VERSION 5.8 ;
BUSBITCHARS "[]" ;
DIVIDERCHAR "/" ;
UNITS
    DATABASE MICRONS 1000 ;
END UNITS

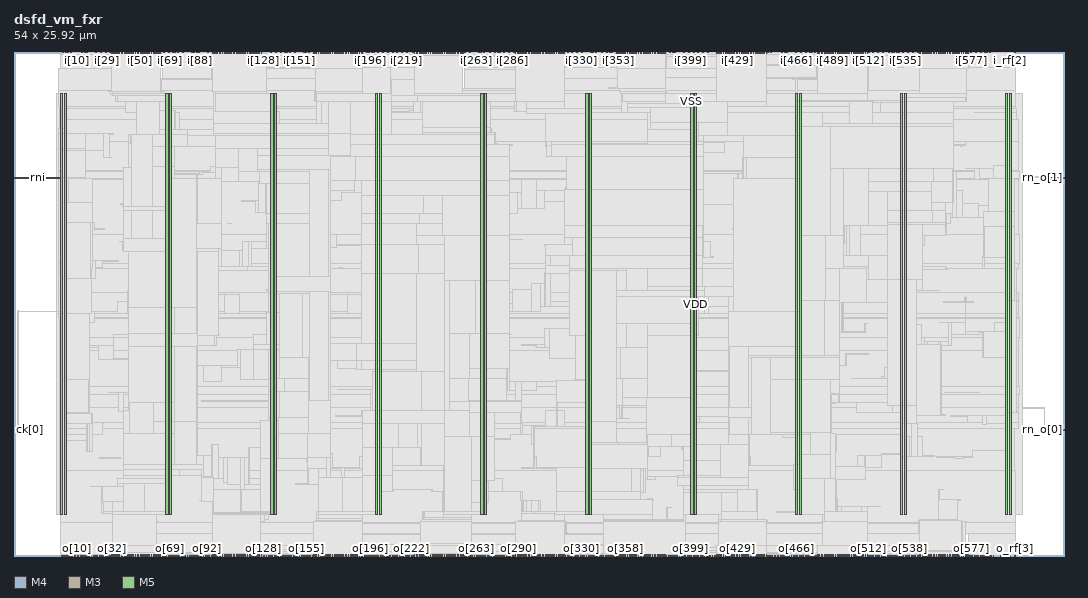
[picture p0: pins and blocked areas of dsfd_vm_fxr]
MACRO dsfd_vm_fxr
  FOREIGN dsfd_vm_fxr 0 0 ;
  CLASS BLOCK ;
  SIZE 54 BY 25.92 ;
  PIN ck[0]
    DIRECTION INPUT ;
    USE SIGNAL ;
    PORT
      LAYER M4 ;
        RECT  0 6.48 0.084 6.504 ;
    END
    PORT
      LAYER M4 ;
        RECT  0.06 6.48 0.227 6.504 ;
    END
  END ck[0]
  PIN i[0]
    DIRECTION INPUT ;
    USE SIGNAL ;
    PORT
      LAYER M3 ;
        RECT  2.448 25.882 2.466 25.92 ;
    END
  END i[0]
  PIN i[100]
    DIRECTION INPUT ;
    USE SIGNAL ;
    PORT
      LAYER M5 ;
        RECT  10.56 25.836 10.584 25.92 ;
    END
  END i[100]
  PIN i[101]
    DIRECTION INPUT ;
    USE SIGNAL ;
    PORT
      LAYER M5 ;
        RECT  10.608 25.836 10.632 25.92 ;
    END
  END i[101]
  PIN i[102]
    DIRECTION INPUT ;
    USE SIGNAL ;
    PORT
      LAYER M5 ;
        RECT  10.704 25.836 10.728 25.92 ;
    END
  END i[102]
  PIN i[103]
    DIRECTION INPUT ;
    USE SIGNAL ;
    PORT
      LAYER M5 ;
        RECT  10.8 25.836 10.824 25.92 ;
    END
  END i[103]
  PIN i[104]
    DIRECTION INPUT ;
    USE SIGNAL ;
    PORT
      LAYER M5 ;
        RECT  10.848 25.836 10.872 25.92 ;
    END
  END i[104]
  PIN i[105]
    DIRECTION INPUT ;
    USE SIGNAL ;
    PORT
      LAYER M5 ;
        RECT  10.944 25.836 10.968 25.92 ;
    END
  END i[105]
  PIN i[106]
    DIRECTION INPUT ;
    USE SIGNAL ;
    PORT
      LAYER M5 ;
        RECT  11.04 25.836 11.064 25.92 ;
    END
  END i[106]
  PIN i[107]
    DIRECTION INPUT ;
    USE SIGNAL ;
    PORT
      LAYER M5 ;
        RECT  11.088 25.836 11.112 25.92 ;
    END
  END i[107]
  PIN i[108]
    DIRECTION INPUT ;
    USE SIGNAL ;
    PORT
      LAYER M5 ;
        RECT  11.184 25.836 11.208 25.92 ;
    END
  END i[108]
  PIN i[109]
    DIRECTION INPUT ;
    USE SIGNAL ;
    PORT
      LAYER M5 ;
        RECT  11.28 25.836 11.304 25.92 ;
    END
  END i[109]
  PIN i[10]
    DIRECTION INPUT ;
    USE SIGNAL ;
    PORT
      LAYER M3 ;
        RECT  3.24 25.882 3.258 25.92 ;
    END
  END i[10]
  PIN i[110]
    DIRECTION INPUT ;
    USE SIGNAL ;
    PORT
      LAYER M5 ;
        RECT  11.328 25.836 11.352 25.92 ;
    END
  END i[110]
  PIN i[111]
    DIRECTION INPUT ;
    USE SIGNAL ;
    PORT
      LAYER M5 ;
        RECT  11.424 25.836 11.448 25.92 ;
    END
  END i[111]
  PIN i[112]
    DIRECTION INPUT ;
    USE SIGNAL ;
    PORT
      LAYER M5 ;
        RECT  11.52 25.836 11.544 25.92 ;
    END
  END i[112]
  PIN i[113]
    DIRECTION INPUT ;
    USE SIGNAL ;
    PORT
      LAYER M5 ;
        RECT  11.568 25.836 11.592 25.92 ;
    END
  END i[113]
  PIN i[114]
    DIRECTION INPUT ;
    USE SIGNAL ;
    PORT
      LAYER M5 ;
        RECT  11.664 25.836 11.688 25.92 ;
    END
  END i[114]
  PIN i[115]
    DIRECTION INPUT ;
    USE SIGNAL ;
    PORT
      LAYER M5 ;
        RECT  11.76 25.836 11.784 25.92 ;
    END
  END i[115]
  PIN i[116]
    DIRECTION INPUT ;
    USE SIGNAL ;
    PORT
      LAYER M5 ;
        RECT  11.856 25.836 11.88 25.92 ;
    END
  END i[116]
  PIN i[117]
    DIRECTION INPUT ;
    USE SIGNAL ;
    PORT
      LAYER M5 ;
        RECT  11.904 25.836 11.928 25.92 ;
    END
  END i[117]
  PIN i[118]
    DIRECTION INPUT ;
    USE SIGNAL ;
    PORT
      LAYER M5 ;
        RECT  12 25.836 12.024 25.92 ;
    END
  END i[118]
  PIN i[119]
    DIRECTION INPUT ;
    USE SIGNAL ;
    PORT
      LAYER M5 ;
        RECT  12.096 25.836 12.12 25.92 ;
    END
  END i[119]
  PIN i[11]
    DIRECTION INPUT ;
    USE SIGNAL ;
    PORT
      LAYER M3 ;
        RECT  3.312 25.882 3.33 25.92 ;
    END
  END i[11]
  PIN i[120]
    DIRECTION INPUT ;
    USE SIGNAL ;
    PORT
      LAYER M5 ;
        RECT  12.144 25.836 12.168 25.92 ;
    END
  END i[120]
  PIN i[121]
    DIRECTION INPUT ;
    USE SIGNAL ;
    PORT
      LAYER M5 ;
        RECT  12.24 25.836 12.264 25.92 ;
    END
  END i[121]
  PIN i[122]
    DIRECTION INPUT ;
    USE SIGNAL ;
    PORT
      LAYER M5 ;
        RECT  12.336 25.836 12.36 25.92 ;
    END
  END i[122]
  PIN i[123]
    DIRECTION INPUT ;
    USE SIGNAL ;
    PORT
      LAYER M5 ;
        RECT  12.384 25.836 12.408 25.92 ;
    END
  END i[123]
  PIN i[124]
    DIRECTION INPUT ;
    USE SIGNAL ;
    PORT
      LAYER M5 ;
        RECT  12.48 25.836 12.504 25.92 ;
    END
  END i[124]
  PIN i[125]
    DIRECTION INPUT ;
    USE SIGNAL ;
    PORT
      LAYER M5 ;
        RECT  12.576 25.836 12.6 25.92 ;
    END
  END i[125]
  PIN i[126]
    DIRECTION INPUT ;
    USE SIGNAL ;
    PORT
      LAYER M5 ;
        RECT  12.624 25.836 12.648 25.92 ;
    END
  END i[126]
  PIN i[127]
    DIRECTION INPUT ;
    USE SIGNAL ;
    PORT
      LAYER M5 ;
        RECT  12.72 25.836 12.744 25.92 ;
    END
  END i[127]
  PIN i[128]
    DIRECTION INPUT ;
    USE SIGNAL ;
    PORT
      LAYER M3 ;
        RECT  12.816 25.882 12.834 25.92 ;
    END
  END i[128]
  PIN i[129]
    DIRECTION INPUT ;
    USE SIGNAL ;
    PORT
      LAYER M3 ;
        RECT  12.888 25.882 12.906 25.92 ;
    END
  END i[129]
  PIN i[12]
    DIRECTION INPUT ;
    USE SIGNAL ;
    PORT
      LAYER M3 ;
        RECT  3.42 25.882 3.438 25.92 ;
    END
  END i[12]
  PIN i[130]
    DIRECTION INPUT ;
    USE SIGNAL ;
    PORT
      LAYER M3 ;
        RECT  12.96 25.882 12.978 25.92 ;
    END
  END i[130]
  PIN i[131]
    DIRECTION INPUT ;
    USE SIGNAL ;
    PORT
      LAYER M3 ;
        RECT  13.068 25.882 13.086 25.92 ;
    END
  END i[131]
  PIN i[132]
    DIRECTION INPUT ;
    USE SIGNAL ;
    PORT
      LAYER M3 ;
        RECT  13.14 25.882 13.158 25.92 ;
    END
  END i[132]
  PIN i[133]
    DIRECTION INPUT ;
    USE SIGNAL ;
    PORT
      LAYER M3 ;
        RECT  13.212 25.882 13.23 25.92 ;
    END
  END i[133]
  PIN i[134]
    DIRECTION INPUT ;
    USE SIGNAL ;
    PORT
      LAYER M3 ;
        RECT  13.284 25.882 13.302 25.92 ;
    END
  END i[134]
  PIN i[135]
    DIRECTION INPUT ;
    USE SIGNAL ;
    PORT
      LAYER M3 ;
        RECT  13.392 25.882 13.41 25.92 ;
    END
  END i[135]
  PIN i[136]
    DIRECTION INPUT ;
    USE SIGNAL ;
    PORT
      LAYER M3 ;
        RECT  13.464 25.882 13.482 25.92 ;
    END
  END i[136]
  PIN i[137]
    DIRECTION INPUT ;
    USE SIGNAL ;
    PORT
      LAYER M3 ;
        RECT  13.536 25.882 13.554 25.92 ;
    END
  END i[137]
  PIN i[138]
    DIRECTION INPUT ;
    USE SIGNAL ;
    PORT
      LAYER M3 ;
        RECT  13.608 25.882 13.626 25.92 ;
    END
  END i[138]
  PIN i[139]
    DIRECTION INPUT ;
    USE SIGNAL ;
    PORT
      LAYER M3 ;
        RECT  13.716 25.882 13.734 25.92 ;
    END
  END i[139]
  PIN i[13]
    DIRECTION INPUT ;
    USE SIGNAL ;
    PORT
      LAYER M3 ;
        RECT  3.492 25.882 3.51 25.92 ;
    END
  END i[13]
  PIN i[140]
    DIRECTION INPUT ;
    USE SIGNAL ;
    PORT
      LAYER M3 ;
        RECT  13.788 25.882 13.806 25.92 ;
    END
  END i[140]
  PIN i[141]
    DIRECTION INPUT ;
    USE SIGNAL ;
    PORT
      LAYER M3 ;
        RECT  13.86 25.882 13.878 25.92 ;
    END
  END i[141]
  PIN i[142]
    DIRECTION INPUT ;
    USE SIGNAL ;
    PORT
      LAYER M3 ;
        RECT  13.932 25.882 13.95 25.92 ;
    END
  END i[142]
  PIN i[143]
    DIRECTION INPUT ;
    USE SIGNAL ;
    PORT
      LAYER M3 ;
        RECT  14.04 25.882 14.058 25.92 ;
    END
  END i[143]
  PIN i[144]
    DIRECTION INPUT ;
    USE SIGNAL ;
    PORT
      LAYER M3 ;
        RECT  14.112 25.882 14.13 25.92 ;
    END
  END i[144]
  PIN i[145]
    DIRECTION INPUT ;
    USE SIGNAL ;
    PORT
      LAYER M3 ;
        RECT  14.184 25.882 14.202 25.92 ;
    END
  END i[145]
  PIN i[146]
    DIRECTION INPUT ;
    USE SIGNAL ;
    PORT
      LAYER M3 ;
        RECT  14.256 25.882 14.274 25.92 ;
    END
  END i[146]
  PIN i[147]
    DIRECTION INPUT ;
    USE SIGNAL ;
    PORT
      LAYER M3 ;
        RECT  14.364 25.882 14.382 25.92 ;
    END
  END i[147]
  PIN i[148]
    DIRECTION INPUT ;
    USE SIGNAL ;
    PORT
      LAYER M3 ;
        RECT  14.436 25.882 14.454 25.92 ;
    END
  END i[148]
  PIN i[149]
    DIRECTION INPUT ;
    USE SIGNAL ;
    PORT
      LAYER M3 ;
        RECT  14.508 25.882 14.526 25.92 ;
    END
  END i[149]
  PIN i[14]
    DIRECTION INPUT ;
    USE SIGNAL ;
    PORT
      LAYER M3 ;
        RECT  3.564 25.882 3.582 25.92 ;
    END
  END i[14]
  PIN i[150]
    DIRECTION INPUT ;
    USE SIGNAL ;
    PORT
      LAYER M3 ;
        RECT  14.58 25.882 14.598 25.92 ;
    END
  END i[150]
  PIN i[151]
    DIRECTION INPUT ;
    USE SIGNAL ;
    PORT
      LAYER M3 ;
        RECT  14.688 25.882 14.706 25.92 ;
    END
  END i[151]
  PIN i[152]
    DIRECTION INPUT ;
    USE SIGNAL ;
    PORT
      LAYER M3 ;
        RECT  14.76 25.882 14.778 25.92 ;
    END
  END i[152]
  PIN i[153]
    DIRECTION INPUT ;
    USE SIGNAL ;
    PORT
      LAYER M3 ;
        RECT  14.832 25.882 14.85 25.92 ;
    END
  END i[153]
  PIN i[154]
    DIRECTION INPUT ;
    USE SIGNAL ;
    PORT
      LAYER M3 ;
        RECT  14.904 25.882 14.922 25.92 ;
    END
  END i[154]
  PIN i[155]
    DIRECTION INPUT ;
    USE SIGNAL ;
    PORT
      LAYER M3 ;
        RECT  15.012 25.882 15.03 25.92 ;
    END
  END i[155]
  PIN i[156]
    DIRECTION INPUT ;
    USE SIGNAL ;
    PORT
      LAYER M3 ;
        RECT  15.084 25.882 15.102 25.92 ;
    END
  END i[156]
  PIN i[157]
    DIRECTION INPUT ;
    USE SIGNAL ;
    PORT
      LAYER M3 ;
        RECT  15.156 25.882 15.174 25.92 ;
    END
  END i[157]
  PIN i[158]
    DIRECTION INPUT ;
    USE SIGNAL ;
    PORT
      LAYER M3 ;
        RECT  15.228 25.882 15.246 25.92 ;
    END
  END i[158]
  PIN i[159]
    DIRECTION INPUT ;
    USE SIGNAL ;
    PORT
      LAYER M3 ;
        RECT  15.336 25.882 15.354 25.92 ;
    END
  END i[159]
  PIN i[15]
    DIRECTION INPUT ;
    USE SIGNAL ;
    PORT
      LAYER M3 ;
        RECT  3.636 25.882 3.654 25.92 ;
    END
  END i[15]
  PIN i[160]
    DIRECTION INPUT ;
    USE SIGNAL ;
    PORT
      LAYER M5 ;
        RECT  15.408 25.836 15.432 25.92 ;
    END
  END i[160]
  PIN i[161]
    DIRECTION INPUT ;
    USE SIGNAL ;
    PORT
      LAYER M5 ;
        RECT  15.504 25.836 15.528 25.92 ;
    END
  END i[161]
  PIN i[162]
    DIRECTION INPUT ;
    USE SIGNAL ;
    PORT
      LAYER M5 ;
        RECT  15.552 25.836 15.576 25.92 ;
    END
  END i[162]
  PIN i[163]
    DIRECTION INPUT ;
    USE SIGNAL ;
    PORT
      LAYER M5 ;
        RECT  15.648 25.836 15.672 25.92 ;
    END
  END i[163]
  PIN i[164]
    DIRECTION INPUT ;
    USE SIGNAL ;
    PORT
      LAYER M5 ;
        RECT  15.744 25.836 15.768 25.92 ;
    END
  END i[164]
  PIN i[165]
    DIRECTION INPUT ;
    USE SIGNAL ;
    PORT
      LAYER M5 ;
        RECT  15.792 25.836 15.816 25.92 ;
    END
  END i[165]
  PIN i[166]
    DIRECTION INPUT ;
    USE SIGNAL ;
    PORT
      LAYER M5 ;
        RECT  15.888 25.836 15.912 25.92 ;
    END
  END i[166]
  PIN i[167]
    DIRECTION INPUT ;
    USE SIGNAL ;
    PORT
      LAYER M5 ;
        RECT  15.984 25.836 16.008 25.92 ;
    END
  END i[167]
  PIN i[168]
    DIRECTION INPUT ;
    USE SIGNAL ;
    PORT
      LAYER M5 ;
        RECT  16.032 25.836 16.056 25.92 ;
    END
  END i[168]
  PIN i[169]
    DIRECTION INPUT ;
    USE SIGNAL ;
    PORT
      LAYER M5 ;
        RECT  16.128 25.836 16.152 25.92 ;
    END
  END i[169]
  PIN i[16]
    DIRECTION INPUT ;
    USE SIGNAL ;
    PORT
      LAYER M3 ;
        RECT  3.744 25.882 3.762 25.92 ;
    END
  END i[16]
  PIN i[170]
    DIRECTION INPUT ;
    USE SIGNAL ;
    PORT
      LAYER M5 ;
        RECT  16.224 25.836 16.248 25.92 ;
    END
  END i[170]
  PIN i[171]
    DIRECTION INPUT ;
    USE SIGNAL ;
    PORT
      LAYER M5 ;
        RECT  16.272 25.836 16.296 25.92 ;
    END
  END i[171]
  PIN i[172]
    DIRECTION INPUT ;
    USE SIGNAL ;
    PORT
      LAYER M5 ;
        RECT  16.368 25.836 16.392 25.92 ;
    END
  END i[172]
  PIN i[173]
    DIRECTION INPUT ;
    USE SIGNAL ;
    PORT
      LAYER M5 ;
        RECT  16.464 25.836 16.488 25.92 ;
    END
  END i[173]
  PIN i[174]
    DIRECTION INPUT ;
    USE SIGNAL ;
    PORT
      LAYER M5 ;
        RECT  16.56 25.836 16.584 25.92 ;
    END
  END i[174]
  PIN i[175]
    DIRECTION INPUT ;
    USE SIGNAL ;
    PORT
      LAYER M5 ;
        RECT  16.608 25.836 16.632 25.92 ;
    END
  END i[175]
  PIN i[176]
    DIRECTION INPUT ;
    USE SIGNAL ;
    PORT
      LAYER M5 ;
        RECT  16.704 25.836 16.728 25.92 ;
    END
  END i[176]
  PIN i[177]
    DIRECTION INPUT ;
    USE SIGNAL ;
    PORT
      LAYER M5 ;
        RECT  16.8 25.836 16.824 25.92 ;
    END
  END i[177]
  PIN i[178]
    DIRECTION INPUT ;
    USE SIGNAL ;
    PORT
      LAYER M5 ;
        RECT  16.848 25.836 16.872 25.92 ;
    END
  END i[178]
  PIN i[179]
    DIRECTION INPUT ;
    USE SIGNAL ;
    PORT
      LAYER M5 ;
        RECT  16.944 25.836 16.968 25.92 ;
    END
  END i[179]
  PIN i[17]
    DIRECTION INPUT ;
    USE SIGNAL ;
    PORT
      LAYER M3 ;
        RECT  3.816 25.882 3.834 25.92 ;
    END
  END i[17]
  PIN i[180]
    DIRECTION INPUT ;
    USE SIGNAL ;
    PORT
      LAYER M5 ;
        RECT  17.04 25.836 17.064 25.92 ;
    END
  END i[180]
  PIN i[181]
    DIRECTION INPUT ;
    USE SIGNAL ;
    PORT
      LAYER M5 ;
        RECT  17.088 25.836 17.112 25.92 ;
    END
  END i[181]
  PIN i[182]
    DIRECTION INPUT ;
    USE SIGNAL ;
    PORT
      LAYER M5 ;
        RECT  17.184 25.836 17.208 25.92 ;
    END
  END i[182]
  PIN i[183]
    DIRECTION INPUT ;
    USE SIGNAL ;
    PORT
      LAYER M5 ;
        RECT  17.28 25.836 17.304 25.92 ;
    END
  END i[183]
  PIN i[184]
    DIRECTION INPUT ;
    USE SIGNAL ;
    PORT
      LAYER M5 ;
        RECT  17.328 25.836 17.352 25.92 ;
    END
  END i[184]
  PIN i[185]
    DIRECTION INPUT ;
    USE SIGNAL ;
    PORT
      LAYER M5 ;
        RECT  17.424 25.836 17.448 25.92 ;
    END
  END i[185]
  PIN i[186]
    DIRECTION INPUT ;
    USE SIGNAL ;
    PORT
      LAYER M5 ;
        RECT  17.52 25.836 17.544 25.92 ;
    END
  END i[186]
  PIN i[187]
    DIRECTION INPUT ;
    USE SIGNAL ;
    PORT
      LAYER M5 ;
        RECT  17.568 25.836 17.592 25.92 ;
    END
  END i[187]
  PIN i[188]
    DIRECTION INPUT ;
    USE SIGNAL ;
    PORT
      LAYER M5 ;
        RECT  17.664 25.836 17.688 25.92 ;
    END
  END i[188]
  PIN i[189]
    DIRECTION INPUT ;
    USE SIGNAL ;
    PORT
      LAYER M5 ;
        RECT  17.76 25.836 17.784 25.92 ;
    END
  END i[189]
  PIN i[18]
    DIRECTION INPUT ;
    USE SIGNAL ;
    PORT
      LAYER M3 ;
        RECT  3.888 25.882 3.906 25.92 ;
    END
  END i[18]
  PIN i[190]
    DIRECTION INPUT ;
    USE SIGNAL ;
    PORT
      LAYER M5 ;
        RECT  17.856 25.836 17.88 25.92 ;
    END
  END i[190]
  PIN i[191]
    DIRECTION INPUT ;
    USE SIGNAL ;
    PORT
      LAYER M5 ;
        RECT  17.904 25.836 17.928 25.92 ;
    END
  END i[191]
  PIN i[192]
    DIRECTION INPUT ;
    USE SIGNAL ;
    PORT
      LAYER M3 ;
        RECT  18 25.882 18.018 25.92 ;
    END
  END i[192]
  PIN i[193]
    DIRECTION INPUT ;
    USE SIGNAL ;
    PORT
      LAYER M3 ;
        RECT  18.072 25.882 18.09 25.92 ;
    END
  END i[193]
  PIN i[194]
    DIRECTION INPUT ;
    USE SIGNAL ;
    PORT
      LAYER M3 ;
        RECT  18.144 25.882 18.162 25.92 ;
    END
  END i[194]
  PIN i[195]
    DIRECTION INPUT ;
    USE SIGNAL ;
    PORT
      LAYER M3 ;
        RECT  18.252 25.882 18.27 25.92 ;
    END
  END i[195]
  PIN i[196]
    DIRECTION INPUT ;
    USE SIGNAL ;
    PORT
      LAYER M3 ;
        RECT  18.324 25.882 18.342 25.92 ;
    END
  END i[196]
  PIN i[197]
    DIRECTION INPUT ;
    USE SIGNAL ;
    PORT
      LAYER M3 ;
        RECT  18.396 25.882 18.414 25.92 ;
    END
  END i[197]
  PIN i[198]
    DIRECTION INPUT ;
    USE SIGNAL ;
    PORT
      LAYER M3 ;
        RECT  18.504 25.882 18.522 25.92 ;
    END
  END i[198]
  PIN i[199]
    DIRECTION INPUT ;
    USE SIGNAL ;
    PORT
      LAYER M3 ;
        RECT  18.576 25.882 18.594 25.92 ;
    END
  END i[199]
  PIN i[19]
    DIRECTION INPUT ;
    USE SIGNAL ;
    PORT
      LAYER M3 ;
        RECT  3.96 25.882 3.978 25.92 ;
    END
  END i[19]
  PIN i[1]
    DIRECTION INPUT ;
    USE SIGNAL ;
    PORT
      LAYER M3 ;
        RECT  2.52 25.882 2.538 25.92 ;
    END
  END i[1]
  PIN i[200]
    DIRECTION INPUT ;
    USE SIGNAL ;
    PORT
      LAYER M3 ;
        RECT  18.648 25.882 18.666 25.92 ;
    END
  END i[200]
  PIN i[201]
    DIRECTION INPUT ;
    USE SIGNAL ;
    PORT
      LAYER M3 ;
        RECT  18.72 25.882 18.738 25.92 ;
    END
  END i[201]
  PIN i[202]
    DIRECTION INPUT ;
    USE SIGNAL ;
    PORT
      LAYER M3 ;
        RECT  18.828 25.882 18.846 25.92 ;
    END
  END i[202]
  PIN i[203]
    DIRECTION INPUT ;
    USE SIGNAL ;
    PORT
      LAYER M3 ;
        RECT  18.9 25.882 18.918 25.92 ;
    END
  END i[203]
  PIN i[204]
    DIRECTION INPUT ;
    USE SIGNAL ;
    PORT
      LAYER M3 ;
        RECT  18.972 25.882 18.99 25.92 ;
    END
  END i[204]
  PIN i[205]
    DIRECTION INPUT ;
    USE SIGNAL ;
    PORT
      LAYER M3 ;
        RECT  19.044 25.882 19.062 25.92 ;
    END
  END i[205]
  PIN i[206]
    DIRECTION INPUT ;
    USE SIGNAL ;
    PORT
      LAYER M3 ;
        RECT  19.152 25.882 19.17 25.92 ;
    END
  END i[206]
  PIN i[207]
    DIRECTION INPUT ;
    USE SIGNAL ;
    PORT
      LAYER M3 ;
        RECT  19.224 25.882 19.242 25.92 ;
    END
  END i[207]
  PIN i[208]
    DIRECTION INPUT ;
    USE SIGNAL ;
    PORT
      LAYER M3 ;
        RECT  19.296 25.882 19.314 25.92 ;
    END
  END i[208]
  PIN i[209]
    DIRECTION INPUT ;
    USE SIGNAL ;
    PORT
      LAYER M3 ;
        RECT  19.368 25.882 19.386 25.92 ;
    END
  END i[209]
  PIN i[20]
    DIRECTION INPUT ;
    USE SIGNAL ;
    PORT
      LAYER M3 ;
        RECT  4.068 25.882 4.086 25.92 ;
    END
  END i[20]
  PIN i[210]
    DIRECTION INPUT ;
    USE SIGNAL ;
    PORT
      LAYER M3 ;
        RECT  19.476 25.882 19.494 25.92 ;
    END
  END i[210]
  PIN i[211]
    DIRECTION INPUT ;
    USE SIGNAL ;
    PORT
      LAYER M3 ;
        RECT  19.548 25.882 19.566 25.92 ;
    END
  END i[211]
  PIN i[212]
    DIRECTION INPUT ;
    USE SIGNAL ;
    PORT
      LAYER M3 ;
        RECT  19.62 25.882 19.638 25.92 ;
    END
  END i[212]
  PIN i[213]
    DIRECTION INPUT ;
    USE SIGNAL ;
    PORT
      LAYER M3 ;
        RECT  19.692 25.882 19.71 25.92 ;
    END
  END i[213]
  PIN i[214]
    DIRECTION INPUT ;
    USE SIGNAL ;
    PORT
      LAYER M3 ;
        RECT  19.8 25.882 19.818 25.92 ;
    END
  END i[214]
  PIN i[215]
    DIRECTION INPUT ;
    USE SIGNAL ;
    PORT
      LAYER M3 ;
        RECT  19.872 25.882 19.89 25.92 ;
    END
  END i[215]
  PIN i[216]
    DIRECTION INPUT ;
    USE SIGNAL ;
    PORT
      LAYER M3 ;
        RECT  19.944 25.882 19.962 25.92 ;
    END
  END i[216]
  PIN i[217]
    DIRECTION INPUT ;
    USE SIGNAL ;
    PORT
      LAYER M3 ;
        RECT  20.016 25.882 20.034 25.92 ;
    END
  END i[217]
  PIN i[218]
    DIRECTION INPUT ;
    USE SIGNAL ;
    PORT
      LAYER M3 ;
        RECT  20.124 25.882 20.142 25.92 ;
    END
  END i[218]
  PIN i[219]
    DIRECTION INPUT ;
    USE SIGNAL ;
    PORT
      LAYER M3 ;
        RECT  20.196 25.882 20.214 25.92 ;
    END
  END i[219]
  PIN i[21]
    DIRECTION INPUT ;
    USE SIGNAL ;
    PORT
      LAYER M3 ;
        RECT  4.14 25.882 4.158 25.92 ;
    END
  END i[21]
  PIN i[220]
    DIRECTION INPUT ;
    USE SIGNAL ;
    PORT
      LAYER M3 ;
        RECT  20.268 25.882 20.286 25.92 ;
    END
  END i[220]
  PIN i[221]
    DIRECTION INPUT ;
    USE SIGNAL ;
    PORT
      LAYER M3 ;
        RECT  20.34 25.882 20.358 25.92 ;
    END
  END i[221]
  PIN i[222]
    DIRECTION INPUT ;
    USE SIGNAL ;
    PORT
      LAYER M3 ;
        RECT  20.448 25.882 20.466 25.92 ;
    END
  END i[222]
  PIN i[223]
    DIRECTION INPUT ;
    USE SIGNAL ;
    PORT
      LAYER M3 ;
        RECT  20.52 25.882 20.538 25.92 ;
    END
  END i[223]
  PIN i[224]
    DIRECTION INPUT ;
    USE SIGNAL ;
    PORT
      LAYER M5 ;
        RECT  20.592 25.836 20.616 25.92 ;
    END
  END i[224]
  PIN i[225]
    DIRECTION INPUT ;
    USE SIGNAL ;
    PORT
      LAYER M5 ;
        RECT  20.688 25.836 20.712 25.92 ;
    END
  END i[225]
  PIN i[226]
    DIRECTION INPUT ;
    USE SIGNAL ;
    PORT
      LAYER M5 ;
        RECT  20.736 25.836 20.76 25.92 ;
    END
  END i[226]
  PIN i[227]
    DIRECTION INPUT ;
    USE SIGNAL ;
    PORT
      LAYER M5 ;
        RECT  20.832 25.836 20.856 25.92 ;
    END
  END i[227]
  PIN i[228]
    DIRECTION INPUT ;
    USE SIGNAL ;
    PORT
      LAYER M5 ;
        RECT  20.928 25.836 20.952 25.92 ;
    END
  END i[228]
  PIN i[229]
    DIRECTION INPUT ;
    USE SIGNAL ;
    PORT
      LAYER M5 ;
        RECT  20.976 25.836 21 25.92 ;
    END
  END i[229]
  PIN i[22]
    DIRECTION INPUT ;
    USE SIGNAL ;
    PORT
      LAYER M3 ;
        RECT  4.212 25.882 4.23 25.92 ;
    END
  END i[22]
  PIN i[230]
    DIRECTION INPUT ;
    USE SIGNAL ;
    PORT
      LAYER M5 ;
        RECT  21.072 25.836 21.096 25.92 ;
    END
  END i[230]
  PIN i[231]
    DIRECTION INPUT ;
    USE SIGNAL ;
    PORT
      LAYER M5 ;
        RECT  21.168 25.836 21.192 25.92 ;
    END
  END i[231]
  PIN i[232]
    DIRECTION INPUT ;
    USE SIGNAL ;
    PORT
      LAYER M5 ;
        RECT  21.216 25.836 21.24 25.92 ;
    END
  END i[232]
  PIN i[233]
    DIRECTION INPUT ;
    USE SIGNAL ;
    PORT
      LAYER M5 ;
        RECT  21.312 25.836 21.336 25.92 ;
    END
  END i[233]
  PIN i[234]
    DIRECTION INPUT ;
    USE SIGNAL ;
    PORT
      LAYER M5 ;
        RECT  21.408 25.836 21.432 25.92 ;
    END
  END i[234]
  PIN i[235]
    DIRECTION INPUT ;
    USE SIGNAL ;
    PORT
      LAYER M5 ;
        RECT  21.504 25.836 21.528 25.92 ;
    END
  END i[235]
  PIN i[236]
    DIRECTION INPUT ;
    USE SIGNAL ;
    PORT
      LAYER M5 ;
        RECT  21.552 25.836 21.576 25.92 ;
    END
  END i[236]
  PIN i[237]
    DIRECTION INPUT ;
    USE SIGNAL ;
    PORT
      LAYER M5 ;
        RECT  21.648 25.836 21.672 25.92 ;
    END
  END i[237]
  PIN i[238]
    DIRECTION INPUT ;
    USE SIGNAL ;
    PORT
      LAYER M5 ;
        RECT  21.744 25.836 21.768 25.92 ;
    END
  END i[238]
  PIN i[239]
    DIRECTION INPUT ;
    USE SIGNAL ;
    PORT
      LAYER M5 ;
        RECT  21.792 25.836 21.816 25.92 ;
    END
  END i[239]
  PIN i[23]
    DIRECTION INPUT ;
    USE SIGNAL ;
    PORT
      LAYER M3 ;
        RECT  4.284 25.882 4.302 25.92 ;
    END
  END i[23]
  PIN i[240]
    DIRECTION INPUT ;
    USE SIGNAL ;
    PORT
      LAYER M5 ;
        RECT  21.888 25.836 21.912 25.92 ;
    END
  END i[240]
  PIN i[241]
    DIRECTION INPUT ;
    USE SIGNAL ;
    PORT
      LAYER M5 ;
        RECT  21.984 25.836 22.008 25.92 ;
    END
  END i[241]
  PIN i[242]
    DIRECTION INPUT ;
    USE SIGNAL ;
    PORT
      LAYER M5 ;
        RECT  22.032 25.836 22.056 25.92 ;
    END
  END i[242]
  PIN i[243]
    DIRECTION INPUT ;
    USE SIGNAL ;
    PORT
      LAYER M5 ;
        RECT  22.128 25.836 22.152 25.92 ;
    END
  END i[243]
  PIN i[244]
    DIRECTION INPUT ;
    USE SIGNAL ;
    PORT
      LAYER M5 ;
        RECT  22.224 25.836 22.248 25.92 ;
    END
  END i[244]
  PIN i[245]
    DIRECTION INPUT ;
    USE SIGNAL ;
    PORT
      LAYER M5 ;
        RECT  22.272 25.836 22.296 25.92 ;
    END
  END i[245]
  PIN i[246]
    DIRECTION INPUT ;
    USE SIGNAL ;
    PORT
      LAYER M5 ;
        RECT  22.368 25.836 22.392 25.92 ;
    END
  END i[246]
  PIN i[247]
    DIRECTION INPUT ;
    USE SIGNAL ;
    PORT
      LAYER M5 ;
        RECT  22.464 25.836 22.488 25.92 ;
    END
  END i[247]
  PIN i[248]
    DIRECTION INPUT ;
    USE SIGNAL ;
    PORT
      LAYER M5 ;
        RECT  22.56 25.836 22.584 25.92 ;
    END
  END i[248]
  PIN i[249]
    DIRECTION INPUT ;
    USE SIGNAL ;
    PORT
      LAYER M5 ;
        RECT  22.608 25.836 22.632 25.92 ;
    END
  END i[249]
  PIN i[24]
    DIRECTION INPUT ;
    USE SIGNAL ;
    PORT
      LAYER M3 ;
        RECT  4.392 25.882 4.41 25.92 ;
    END
  END i[24]
  PIN i[250]
    DIRECTION INPUT ;
    USE SIGNAL ;
    PORT
      LAYER M5 ;
        RECT  22.704 25.836 22.728 25.92 ;
    END
  END i[250]
  PIN i[251]
    DIRECTION INPUT ;
    USE SIGNAL ;
    PORT
      LAYER M5 ;
        RECT  22.8 25.836 22.824 25.92 ;
    END
  END i[251]
  PIN i[252]
    DIRECTION INPUT ;
    USE SIGNAL ;
    PORT
      LAYER M5 ;
        RECT  22.848 25.836 22.872 25.92 ;
    END
  END i[252]
  PIN i[253]
    DIRECTION INPUT ;
    USE SIGNAL ;
    PORT
      LAYER M5 ;
        RECT  22.944 25.836 22.968 25.92 ;
    END
  END i[253]
  PIN i[254]
    DIRECTION INPUT ;
    USE SIGNAL ;
    PORT
      LAYER M5 ;
        RECT  23.04 25.836 23.064 25.92 ;
    END
  END i[254]
  PIN i[255]
    DIRECTION INPUT ;
    USE SIGNAL ;
    PORT
      LAYER M5 ;
        RECT  23.088 25.836 23.112 25.92 ;
    END
  END i[255]
  PIN i[256]
    DIRECTION INPUT ;
    USE SIGNAL ;
    PORT
      LAYER M3 ;
        RECT  23.184 25.882 23.202 25.92 ;
    END
  END i[256]
  PIN i[257]
    DIRECTION INPUT ;
    USE SIGNAL ;
    PORT
      LAYER M3 ;
        RECT  23.256 25.882 23.274 25.92 ;
    END
  END i[257]
  PIN i[258]
    DIRECTION INPUT ;
    USE SIGNAL ;
    PORT
      LAYER M3 ;
        RECT  23.364 25.882 23.382 25.92 ;
    END
  END i[258]
  PIN i[259]
    DIRECTION INPUT ;
    USE SIGNAL ;
    PORT
      LAYER M3 ;
        RECT  23.436 25.882 23.454 25.92 ;
    END
  END i[259]
  PIN i[25]
    DIRECTION INPUT ;
    USE SIGNAL ;
    PORT
      LAYER M3 ;
        RECT  4.464 25.882 4.482 25.92 ;
    END
  END i[25]
  PIN i[260]
    DIRECTION INPUT ;
    USE SIGNAL ;
    PORT
      LAYER M3 ;
        RECT  23.508 25.882 23.526 25.92 ;
    END
  END i[260]
  PIN i[261]
    DIRECTION INPUT ;
    USE SIGNAL ;
    PORT
      LAYER M3 ;
        RECT  23.58 25.882 23.598 25.92 ;
    END
  END i[261]
  PIN i[262]
    DIRECTION INPUT ;
    USE SIGNAL ;
    PORT
      LAYER M3 ;
        RECT  23.688 25.882 23.706 25.92 ;
    END
  END i[262]
  PIN i[263]
    DIRECTION INPUT ;
    USE SIGNAL ;
    PORT
      LAYER M3 ;
        RECT  23.76 25.882 23.778 25.92 ;
    END
  END i[263]
  PIN i[264]
    DIRECTION INPUT ;
    USE SIGNAL ;
    PORT
      LAYER M3 ;
        RECT  23.832 25.882 23.85 25.92 ;
    END
  END i[264]
  PIN i[265]
    DIRECTION INPUT ;
    USE SIGNAL ;
    PORT
      LAYER M3 ;
        RECT  23.904 25.882 23.922 25.92 ;
    END
  END i[265]
  PIN i[266]
    DIRECTION INPUT ;
    USE SIGNAL ;
    PORT
      LAYER M3 ;
        RECT  24.012 25.882 24.03 25.92 ;
    END
  END i[266]
  PIN i[267]
    DIRECTION INPUT ;
    USE SIGNAL ;
    PORT
      LAYER M3 ;
        RECT  24.084 25.882 24.102 25.92 ;
    END
  END i[267]
  PIN i[268]
    DIRECTION INPUT ;
    USE SIGNAL ;
    PORT
      LAYER M3 ;
        RECT  24.156 25.882 24.174 25.92 ;
    END
  END i[268]
  PIN i[269]
    DIRECTION INPUT ;
    USE SIGNAL ;
    PORT
      LAYER M3 ;
        RECT  24.228 25.882 24.246 25.92 ;
    END
  END i[269]
  PIN i[26]
    DIRECTION INPUT ;
    USE SIGNAL ;
    PORT
      LAYER M3 ;
        RECT  4.536 25.882 4.554 25.92 ;
    END
  END i[26]
  PIN i[270]
    DIRECTION INPUT ;
    USE SIGNAL ;
    PORT
      LAYER M3 ;
        RECT  24.336 25.882 24.354 25.92 ;
    END
  END i[270]
  PIN i[271]
    DIRECTION INPUT ;
    USE SIGNAL ;
    PORT
      LAYER M3 ;
        RECT  24.408 25.882 24.426 25.92 ;
    END
  END i[271]
  PIN i[272]
    DIRECTION INPUT ;
    USE SIGNAL ;
    PORT
      LAYER M3 ;
        RECT  24.48 25.882 24.498 25.92 ;
    END
  END i[272]
  PIN i[273]
    DIRECTION INPUT ;
    USE SIGNAL ;
    PORT
      LAYER M3 ;
        RECT  24.552 25.882 24.57 25.92 ;
    END
  END i[273]
  PIN i[274]
    DIRECTION INPUT ;
    USE SIGNAL ;
    PORT
      LAYER M3 ;
        RECT  24.66 25.882 24.678 25.92 ;
    END
  END i[274]
  PIN i[275]
    DIRECTION INPUT ;
    USE SIGNAL ;
    PORT
      LAYER M3 ;
        RECT  24.732 25.882 24.75 25.92 ;
    END
  END i[275]
  PIN i[276]
    DIRECTION INPUT ;
    USE SIGNAL ;
    PORT
      LAYER M3 ;
        RECT  24.804 25.882 24.822 25.92 ;
    END
  END i[276]
  PIN i[277]
    DIRECTION INPUT ;
    USE SIGNAL ;
    PORT
      LAYER M3 ;
        RECT  24.876 25.882 24.894 25.92 ;
    END
  END i[277]
  PIN i[278]
    DIRECTION INPUT ;
    USE SIGNAL ;
    PORT
      LAYER M3 ;
        RECT  24.984 25.882 25.002 25.92 ;
    END
  END i[278]
  PIN i[279]
    DIRECTION INPUT ;
    USE SIGNAL ;
    PORT
      LAYER M3 ;
        RECT  25.056 25.882 25.074 25.92 ;
    END
  END i[279]
  PIN i[27]
    DIRECTION INPUT ;
    USE SIGNAL ;
    PORT
      LAYER M3 ;
        RECT  4.608 25.882 4.626 25.92 ;
    END
  END i[27]
  PIN i[280]
    DIRECTION INPUT ;
    USE SIGNAL ;
    PORT
      LAYER M3 ;
        RECT  25.128 25.882 25.146 25.92 ;
    END
  END i[280]
  PIN i[281]
    DIRECTION INPUT ;
    USE SIGNAL ;
    PORT
      LAYER M3 ;
        RECT  25.2 25.882 25.218 25.92 ;
    END
  END i[281]
  PIN i[282]
    DIRECTION INPUT ;
    USE SIGNAL ;
    PORT
      LAYER M3 ;
        RECT  25.308 25.882 25.326 25.92 ;
    END
  END i[282]
  PIN i[283]
    DIRECTION INPUT ;
    USE SIGNAL ;
    PORT
      LAYER M3 ;
        RECT  25.38 25.882 25.398 25.92 ;
    END
  END i[283]
  PIN i[284]
    DIRECTION INPUT ;
    USE SIGNAL ;
    PORT
      LAYER M3 ;
        RECT  25.452 25.882 25.47 25.92 ;
    END
  END i[284]
  PIN i[285]
    DIRECTION INPUT ;
    USE SIGNAL ;
    PORT
      LAYER M3 ;
        RECT  25.524 25.882 25.542 25.92 ;
    END
  END i[285]
  PIN i[286]
    DIRECTION INPUT ;
    USE SIGNAL ;
    PORT
      LAYER M3 ;
        RECT  25.632 25.882 25.65 25.92 ;
    END
  END i[286]
  PIN i[287]
    DIRECTION INPUT ;
    USE SIGNAL ;
    PORT
      LAYER M3 ;
        RECT  25.704 25.882 25.722 25.92 ;
    END
  END i[287]
  PIN i[288]
    DIRECTION INPUT ;
    USE SIGNAL ;
    PORT
      LAYER M5 ;
        RECT  25.776 25.836 25.8 25.92 ;
    END
  END i[288]
  PIN i[289]
    DIRECTION INPUT ;
    USE SIGNAL ;
    PORT
      LAYER M5 ;
        RECT  25.872 25.836 25.896 25.92 ;
    END
  END i[289]
  PIN i[28]
    DIRECTION INPUT ;
    USE SIGNAL ;
    PORT
      LAYER M3 ;
        RECT  4.716 25.882 4.734 25.92 ;
    END
  END i[28]
  PIN i[290]
    DIRECTION INPUT ;
    USE SIGNAL ;
    PORT
      LAYER M5 ;
        RECT  25.92 25.836 25.944 25.92 ;
    END
  END i[290]
  PIN i[291]
    DIRECTION INPUT ;
    USE SIGNAL ;
    PORT
      LAYER M5 ;
        RECT  26.016 25.836 26.04 25.92 ;
    END
  END i[291]
  PIN i[292]
    DIRECTION INPUT ;
    USE SIGNAL ;
    PORT
      LAYER M5 ;
        RECT  26.112 25.836 26.136 25.92 ;
    END
  END i[292]
  PIN i[293]
    DIRECTION INPUT ;
    USE SIGNAL ;
    PORT
      LAYER M5 ;
        RECT  26.208 25.836 26.232 25.92 ;
    END
  END i[293]
  PIN i[294]
    DIRECTION INPUT ;
    USE SIGNAL ;
    PORT
      LAYER M5 ;
        RECT  26.256 25.836 26.28 25.92 ;
    END
  END i[294]
  PIN i[295]
    DIRECTION INPUT ;
    USE SIGNAL ;
    PORT
      LAYER M5 ;
        RECT  26.352 25.836 26.376 25.92 ;
    END
  END i[295]
  PIN i[296]
    DIRECTION INPUT ;
    USE SIGNAL ;
    PORT
      LAYER M5 ;
        RECT  26.448 25.836 26.472 25.92 ;
    END
  END i[296]
  PIN i[297]
    DIRECTION INPUT ;
    USE SIGNAL ;
    PORT
      LAYER M5 ;
        RECT  26.496 25.836 26.52 25.92 ;
    END
  END i[297]
  PIN i[298]
    DIRECTION INPUT ;
    USE SIGNAL ;
    PORT
      LAYER M5 ;
        RECT  26.592 25.836 26.616 25.92 ;
    END
  END i[298]
  PIN i[299]
    DIRECTION INPUT ;
    USE SIGNAL ;
    PORT
      LAYER M5 ;
        RECT  26.688 25.836 26.712 25.92 ;
    END
  END i[299]
  PIN i[29]
    DIRECTION INPUT ;
    USE SIGNAL ;
    PORT
      LAYER M3 ;
        RECT  4.788 25.882 4.806 25.92 ;
    END
  END i[29]
  PIN i[2]
    DIRECTION INPUT ;
    USE SIGNAL ;
    PORT
      LAYER M3 ;
        RECT  2.592 25.882 2.61 25.92 ;
    END
  END i[2]
  PIN i[300]
    DIRECTION INPUT ;
    USE SIGNAL ;
    PORT
      LAYER M5 ;
        RECT  26.736 25.836 26.76 25.92 ;
    END
  END i[300]
  PIN i[301]
    DIRECTION INPUT ;
    USE SIGNAL ;
    PORT
      LAYER M5 ;
        RECT  26.832 25.836 26.856 25.92 ;
    END
  END i[301]
  PIN i[302]
    DIRECTION INPUT ;
    USE SIGNAL ;
    PORT
      LAYER M5 ;
        RECT  26.928 25.836 26.952 25.92 ;
    END
  END i[302]
  PIN i[303]
    DIRECTION INPUT ;
    USE SIGNAL ;
    PORT
      LAYER M5 ;
        RECT  26.976 25.836 27 25.92 ;
    END
  END i[303]
  PIN i[304]
    DIRECTION INPUT ;
    USE SIGNAL ;
    PORT
      LAYER M5 ;
        RECT  27.072 25.836 27.096 25.92 ;
    END
  END i[304]
  PIN i[305]
    DIRECTION INPUT ;
    USE SIGNAL ;
    PORT
      LAYER M5 ;
        RECT  27.168 25.836 27.192 25.92 ;
    END
  END i[305]
  PIN i[306]
    DIRECTION INPUT ;
    USE SIGNAL ;
    PORT
      LAYER M5 ;
        RECT  27.216 25.836 27.24 25.92 ;
    END
  END i[306]
  PIN i[307]
    DIRECTION INPUT ;
    USE SIGNAL ;
    PORT
      LAYER M5 ;
        RECT  27.312 25.836 27.336 25.92 ;
    END
  END i[307]
  PIN i[308]
    DIRECTION INPUT ;
    USE SIGNAL ;
    PORT
      LAYER M5 ;
        RECT  27.408 25.836 27.432 25.92 ;
    END
  END i[308]
  PIN i[309]
    DIRECTION INPUT ;
    USE SIGNAL ;
    PORT
      LAYER M5 ;
        RECT  27.504 25.836 27.528 25.92 ;
    END
  END i[309]
  PIN i[30]
    DIRECTION INPUT ;
    USE SIGNAL ;
    PORT
      LAYER M3 ;
        RECT  4.86 25.882 4.878 25.92 ;
    END
  END i[30]
  PIN i[310]
    DIRECTION INPUT ;
    USE SIGNAL ;
    PORT
      LAYER M5 ;
        RECT  27.552 25.836 27.576 25.92 ;
    END
  END i[310]
  PIN i[311]
    DIRECTION INPUT ;
    USE SIGNAL ;
    PORT
      LAYER M5 ;
        RECT  27.648 25.836 27.672 25.92 ;
    END
  END i[311]
  PIN i[312]
    DIRECTION INPUT ;
    USE SIGNAL ;
    PORT
      LAYER M5 ;
        RECT  27.744 25.836 27.768 25.92 ;
    END
  END i[312]
  PIN i[313]
    DIRECTION INPUT ;
    USE SIGNAL ;
    PORT
      LAYER M5 ;
        RECT  27.792 25.836 27.816 25.92 ;
    END
  END i[313]
  PIN i[314]
    DIRECTION INPUT ;
    USE SIGNAL ;
    PORT
      LAYER M5 ;
        RECT  27.888 25.836 27.912 25.92 ;
    END
  END i[314]
  PIN i[315]
    DIRECTION INPUT ;
    USE SIGNAL ;
    PORT
      LAYER M5 ;
        RECT  27.984 25.836 28.008 25.92 ;
    END
  END i[315]
  PIN i[316]
    DIRECTION INPUT ;
    USE SIGNAL ;
    PORT
      LAYER M5 ;
        RECT  28.032 25.836 28.056 25.92 ;
    END
  END i[316]
  PIN i[317]
    DIRECTION INPUT ;
    USE SIGNAL ;
    PORT
      LAYER M5 ;
        RECT  28.128 25.836 28.152 25.92 ;
    END
  END i[317]
  PIN i[318]
    DIRECTION INPUT ;
    USE SIGNAL ;
    PORT
      LAYER M5 ;
        RECT  28.224 25.836 28.248 25.92 ;
    END
  END i[318]
  PIN i[319]
    DIRECTION INPUT ;
    USE SIGNAL ;
    PORT
      LAYER M5 ;
        RECT  28.272 25.836 28.296 25.92 ;
    END
  END i[319]
  PIN i[31]
    DIRECTION INPUT ;
    USE SIGNAL ;
    PORT
      LAYER M3 ;
        RECT  4.932 25.882 4.95 25.92 ;
    END
  END i[31]
  PIN i[320]
    DIRECTION INPUT ;
    USE SIGNAL ;
    PORT
      LAYER M3 ;
        RECT  28.368 25.882 28.386 25.92 ;
    END
  END i[320]
  PIN i[321]
    DIRECTION INPUT ;
    USE SIGNAL ;
    PORT
      LAYER M3 ;
        RECT  28.476 25.882 28.494 25.92 ;
    END
  END i[321]
  PIN i[322]
    DIRECTION INPUT ;
    USE SIGNAL ;
    PORT
      LAYER M3 ;
        RECT  28.548 25.882 28.566 25.92 ;
    END
  END i[322]
  PIN i[323]
    DIRECTION INPUT ;
    USE SIGNAL ;
    PORT
      LAYER M3 ;
        RECT  28.62 25.882 28.638 25.92 ;
    END
  END i[323]
  PIN i[324]
    DIRECTION INPUT ;
    USE SIGNAL ;
    PORT
      LAYER M3 ;
        RECT  28.692 25.882 28.71 25.92 ;
    END
  END i[324]
  PIN i[325]
    DIRECTION INPUT ;
    USE SIGNAL ;
    PORT
      LAYER M3 ;
        RECT  28.8 25.882 28.818 25.92 ;
    END
  END i[325]
  PIN i[326]
    DIRECTION INPUT ;
    USE SIGNAL ;
    PORT
      LAYER M3 ;
        RECT  28.872 25.882 28.89 25.92 ;
    END
  END i[326]
  PIN i[327]
    DIRECTION INPUT ;
    USE SIGNAL ;
    PORT
      LAYER M3 ;
        RECT  28.944 25.882 28.962 25.92 ;
    END
  END i[327]
  PIN i[328]
    DIRECTION INPUT ;
    USE SIGNAL ;
    PORT
      LAYER M3 ;
        RECT  29.016 25.882 29.034 25.92 ;
    END
  END i[328]
  PIN i[329]
    DIRECTION INPUT ;
    USE SIGNAL ;
    PORT
      LAYER M3 ;
        RECT  29.124 25.882 29.142 25.92 ;
    END
  END i[329]
  PIN i[32]
    DIRECTION INPUT ;
    USE SIGNAL ;
    PORT
      LAYER M5 ;
        RECT  5.04 25.836 5.064 25.92 ;
    END
  END i[32]
  PIN i[330]
    DIRECTION INPUT ;
    USE SIGNAL ;
    PORT
      LAYER M3 ;
        RECT  29.196 25.882 29.214 25.92 ;
    END
  END i[330]
  PIN i[331]
    DIRECTION INPUT ;
    USE SIGNAL ;
    PORT
      LAYER M3 ;
        RECT  29.268 25.882 29.286 25.92 ;
    END
  END i[331]
  PIN i[332]
    DIRECTION INPUT ;
    USE SIGNAL ;
    PORT
      LAYER M3 ;
        RECT  29.34 25.882 29.358 25.92 ;
    END
  END i[332]
  PIN i[333]
    DIRECTION INPUT ;
    USE SIGNAL ;
    PORT
      LAYER M3 ;
        RECT  29.448 25.882 29.466 25.92 ;
    END
  END i[333]
  PIN i[334]
    DIRECTION INPUT ;
    USE SIGNAL ;
    PORT
      LAYER M3 ;
        RECT  29.52 25.882 29.538 25.92 ;
    END
  END i[334]
  PIN i[335]
    DIRECTION INPUT ;
    USE SIGNAL ;
    PORT
      LAYER M3 ;
        RECT  29.592 25.882 29.61 25.92 ;
    END
  END i[335]
  PIN i[336]
    DIRECTION INPUT ;
    USE SIGNAL ;
    PORT
      LAYER M3 ;
        RECT  29.664 25.882 29.682 25.92 ;
    END
  END i[336]
  PIN i[337]
    DIRECTION INPUT ;
    USE SIGNAL ;
    PORT
      LAYER M3 ;
        RECT  29.772 25.882 29.79 25.92 ;
    END
  END i[337]
  PIN i[338]
    DIRECTION INPUT ;
    USE SIGNAL ;
    PORT
      LAYER M3 ;
        RECT  29.844 25.882 29.862 25.92 ;
    END
  END i[338]
  PIN i[339]
    DIRECTION INPUT ;
    USE SIGNAL ;
    PORT
      LAYER M3 ;
        RECT  29.916 25.882 29.934 25.92 ;
    END
  END i[339]
  PIN i[33]
    DIRECTION INPUT ;
    USE SIGNAL ;
    PORT
      LAYER M5 ;
        RECT  5.088 25.836 5.112 25.92 ;
    END
  END i[33]
  PIN i[340]
    DIRECTION INPUT ;
    USE SIGNAL ;
    PORT
      LAYER M3 ;
        RECT  29.988 25.882 30.006 25.92 ;
    END
  END i[340]
  PIN i[341]
    DIRECTION INPUT ;
    USE SIGNAL ;
    PORT
      LAYER M3 ;
        RECT  30.096 25.882 30.114 25.92 ;
    END
  END i[341]
  PIN i[342]
    DIRECTION INPUT ;
    USE SIGNAL ;
    PORT
      LAYER M3 ;
        RECT  30.168 25.882 30.186 25.92 ;
    END
  END i[342]
  PIN i[343]
    DIRECTION INPUT ;
    USE SIGNAL ;
    PORT
      LAYER M3 ;
        RECT  30.24 25.882 30.258 25.92 ;
    END
  END i[343]
  PIN i[344]
    DIRECTION INPUT ;
    USE SIGNAL ;
    PORT
      LAYER M3 ;
        RECT  30.312 25.882 30.33 25.92 ;
    END
  END i[344]
  PIN i[345]
    DIRECTION INPUT ;
    USE SIGNAL ;
    PORT
      LAYER M3 ;
        RECT  30.42 25.882 30.438 25.92 ;
    END
  END i[345]
  PIN i[346]
    DIRECTION INPUT ;
    USE SIGNAL ;
    PORT
      LAYER M3 ;
        RECT  30.492 25.882 30.51 25.92 ;
    END
  END i[346]
  PIN i[347]
    DIRECTION INPUT ;
    USE SIGNAL ;
    PORT
      LAYER M3 ;
        RECT  30.564 25.882 30.582 25.92 ;
    END
  END i[347]
  PIN i[348]
    DIRECTION INPUT ;
    USE SIGNAL ;
    PORT
      LAYER M3 ;
        RECT  30.636 25.882 30.654 25.92 ;
    END
  END i[348]
  PIN i[349]
    DIRECTION INPUT ;
    USE SIGNAL ;
    PORT
      LAYER M3 ;
        RECT  30.744 25.882 30.762 25.92 ;
    END
  END i[349]
  PIN i[34]
    DIRECTION INPUT ;
    USE SIGNAL ;
    PORT
      LAYER M5 ;
        RECT  5.184 25.836 5.208 25.92 ;
    END
  END i[34]
  PIN i[350]
    DIRECTION INPUT ;
    USE SIGNAL ;
    PORT
      LAYER M3 ;
        RECT  30.816 25.882 30.834 25.92 ;
    END
  END i[350]
  PIN i[351]
    DIRECTION INPUT ;
    USE SIGNAL ;
    PORT
      LAYER M3 ;
        RECT  30.888 25.882 30.906 25.92 ;
    END
  END i[351]
  PIN i[352]
    DIRECTION INPUT ;
    USE SIGNAL ;
    PORT
      LAYER M5 ;
        RECT  30.96 25.836 30.984 25.92 ;
    END
  END i[352]
  PIN i[353]
    DIRECTION INPUT ;
    USE SIGNAL ;
    PORT
      LAYER M5 ;
        RECT  31.056 25.836 31.08 25.92 ;
    END
  END i[353]
  PIN i[354]
    DIRECTION INPUT ;
    USE SIGNAL ;
    PORT
      LAYER M5 ;
        RECT  31.152 25.836 31.176 25.92 ;
    END
  END i[354]
  PIN i[355]
    DIRECTION INPUT ;
    USE SIGNAL ;
    PORT
      LAYER M5 ;
        RECT  31.2 25.836 31.224 25.92 ;
    END
  END i[355]
  PIN i[356]
    DIRECTION INPUT ;
    USE SIGNAL ;
    PORT
      LAYER M5 ;
        RECT  31.296 25.836 31.32 25.92 ;
    END
  END i[356]
  PIN i[357]
    DIRECTION INPUT ;
    USE SIGNAL ;
    PORT
      LAYER M5 ;
        RECT  31.392 25.836 31.416 25.92 ;
    END
  END i[357]
  PIN i[358]
    DIRECTION INPUT ;
    USE SIGNAL ;
    PORT
      LAYER M5 ;
        RECT  31.44 25.836 31.464 25.92 ;
    END
  END i[358]
  PIN i[359]
    DIRECTION INPUT ;
    USE SIGNAL ;
    PORT
      LAYER M5 ;
        RECT  31.536 25.836 31.56 25.92 ;
    END
  END i[359]
  PIN i[35]
    DIRECTION INPUT ;
    USE SIGNAL ;
    PORT
      LAYER M5 ;
        RECT  5.28 25.836 5.304 25.92 ;
    END
  END i[35]
  PIN i[360]
    DIRECTION INPUT ;
    USE SIGNAL ;
    PORT
      LAYER M5 ;
        RECT  31.632 25.836 31.656 25.92 ;
    END
  END i[360]
  PIN i[361]
    DIRECTION INPUT ;
    USE SIGNAL ;
    PORT
      LAYER M5 ;
        RECT  31.68 25.836 31.704 25.92 ;
    END
  END i[361]
  PIN i[362]
    DIRECTION INPUT ;
    USE SIGNAL ;
    PORT
      LAYER M5 ;
        RECT  31.776 25.836 31.8 25.92 ;
    END
  END i[362]
  PIN i[363]
    DIRECTION INPUT ;
    USE SIGNAL ;
    PORT
      LAYER M5 ;
        RECT  31.872 25.836 31.896 25.92 ;
    END
  END i[363]
  PIN i[364]
    DIRECTION INPUT ;
    USE SIGNAL ;
    PORT
      LAYER M5 ;
        RECT  31.92 25.836 31.944 25.92 ;
    END
  END i[364]
  PIN i[365]
    DIRECTION INPUT ;
    USE SIGNAL ;
    PORT
      LAYER M5 ;
        RECT  32.016 25.836 32.04 25.92 ;
    END
  END i[365]
  PIN i[366]
    DIRECTION INPUT ;
    USE SIGNAL ;
    PORT
      LAYER M5 ;
        RECT  32.112 25.836 32.136 25.92 ;
    END
  END i[366]
  PIN i[367]
    DIRECTION INPUT ;
    USE SIGNAL ;
    PORT
      LAYER M5 ;
        RECT  32.208 25.836 32.232 25.92 ;
    END
  END i[367]
  PIN i[368]
    DIRECTION INPUT ;
    USE SIGNAL ;
    PORT
      LAYER M5 ;
        RECT  32.256 25.836 32.28 25.92 ;
    END
  END i[368]
  PIN i[369]
    DIRECTION INPUT ;
    USE SIGNAL ;
    PORT
      LAYER M5 ;
        RECT  32.352 25.836 32.376 25.92 ;
    END
  END i[369]
  PIN i[36]
    DIRECTION INPUT ;
    USE SIGNAL ;
    PORT
      LAYER M5 ;
        RECT  5.328 25.836 5.352 25.92 ;
    END
  END i[36]
  PIN i[370]
    DIRECTION INPUT ;
    USE SIGNAL ;
    PORT
      LAYER M5 ;
        RECT  32.448 25.836 32.472 25.92 ;
    END
  END i[370]
  PIN i[371]
    DIRECTION INPUT ;
    USE SIGNAL ;
    PORT
      LAYER M5 ;
        RECT  32.496 25.836 32.52 25.92 ;
    END
  END i[371]
  PIN i[372]
    DIRECTION INPUT ;
    USE SIGNAL ;
    PORT
      LAYER M5 ;
        RECT  32.592 25.836 32.616 25.92 ;
    END
  END i[372]
  PIN i[373]
    DIRECTION INPUT ;
    USE SIGNAL ;
    PORT
      LAYER M5 ;
        RECT  32.688 25.836 32.712 25.92 ;
    END
  END i[373]
  PIN i[374]
    DIRECTION INPUT ;
    USE SIGNAL ;
    PORT
      LAYER M5 ;
        RECT  32.736 25.836 32.76 25.92 ;
    END
  END i[374]
  PIN i[375]
    DIRECTION INPUT ;
    USE SIGNAL ;
    PORT
      LAYER M5 ;
        RECT  32.832 25.836 32.856 25.92 ;
    END
  END i[375]
  PIN i[376]
    DIRECTION INPUT ;
    USE SIGNAL ;
    PORT
      LAYER M5 ;
        RECT  32.928 25.836 32.952 25.92 ;
    END
  END i[376]
  PIN i[377]
    DIRECTION INPUT ;
    USE SIGNAL ;
    PORT
      LAYER M5 ;
        RECT  32.976 25.836 33 25.92 ;
    END
  END i[377]
  PIN i[378]
    DIRECTION INPUT ;
    USE SIGNAL ;
    PORT
      LAYER M5 ;
        RECT  33.072 25.836 33.096 25.92 ;
    END
  END i[378]
  PIN i[379]
    DIRECTION INPUT ;
    USE SIGNAL ;
    PORT
      LAYER M5 ;
        RECT  33.168 25.836 33.192 25.92 ;
    END
  END i[379]
  PIN i[37]
    DIRECTION INPUT ;
    USE SIGNAL ;
    PORT
      LAYER M5 ;
        RECT  5.424 25.836 5.448 25.92 ;
    END
  END i[37]
  PIN i[380]
    DIRECTION INPUT ;
    USE SIGNAL ;
    PORT
      LAYER M5 ;
        RECT  33.216 25.836 33.24 25.92 ;
    END
  END i[380]
  PIN i[381]
    DIRECTION INPUT ;
    USE SIGNAL ;
    PORT
      LAYER M5 ;
        RECT  33.312 25.836 33.336 25.92 ;
    END
  END i[381]
  PIN i[382]
    DIRECTION INPUT ;
    USE SIGNAL ;
    PORT
      LAYER M5 ;
        RECT  33.408 25.836 33.432 25.92 ;
    END
  END i[382]
  PIN i[383]
    DIRECTION INPUT ;
    USE SIGNAL ;
    PORT
      LAYER M5 ;
        RECT  33.504 25.836 33.528 25.92 ;
    END
  END i[383]
  PIN i[384]
    DIRECTION INPUT ;
    USE SIGNAL ;
    PORT
      LAYER M3 ;
        RECT  33.552 25.882 33.57 25.92 ;
    END
  END i[384]
  PIN i[385]
    DIRECTION INPUT ;
    USE SIGNAL ;
    PORT
      LAYER M3 ;
        RECT  33.66 25.882 33.678 25.92 ;
    END
  END i[385]
  PIN i[386]
    DIRECTION INPUT ;
    USE SIGNAL ;
    PORT
      LAYER M3 ;
        RECT  33.732 25.882 33.75 25.92 ;
    END
  END i[386]
  PIN i[387]
    DIRECTION INPUT ;
    USE SIGNAL ;
    PORT
      LAYER M3 ;
        RECT  33.804 25.882 33.822 25.92 ;
    END
  END i[387]
  PIN i[388]
    DIRECTION INPUT ;
    USE SIGNAL ;
    PORT
      LAYER M3 ;
        RECT  33.876 25.882 33.894 25.92 ;
    END
  END i[388]
  PIN i[389]
    DIRECTION INPUT ;
    USE SIGNAL ;
    PORT
      LAYER M3 ;
        RECT  33.984 25.882 34.002 25.92 ;
    END
  END i[389]
  PIN i[38]
    DIRECTION INPUT ;
    USE SIGNAL ;
    PORT
      LAYER M5 ;
        RECT  5.52 25.836 5.544 25.92 ;
    END
  END i[38]
  PIN i[390]
    DIRECTION INPUT ;
    USE SIGNAL ;
    PORT
      LAYER M3 ;
        RECT  34.056 25.882 34.074 25.92 ;
    END
  END i[390]
  PIN i[391]
    DIRECTION INPUT ;
    USE SIGNAL ;
    PORT
      LAYER M3 ;
        RECT  34.128 25.882 34.146 25.92 ;
    END
  END i[391]
  PIN i[392]
    DIRECTION INPUT ;
    USE SIGNAL ;
    PORT
      LAYER M3 ;
        RECT  34.2 25.882 34.218 25.92 ;
    END
  END i[392]
  PIN i[393]
    DIRECTION INPUT ;
    USE SIGNAL ;
    PORT
      LAYER M3 ;
        RECT  34.308 25.882 34.326 25.92 ;
    END
  END i[393]
  PIN i[394]
    DIRECTION INPUT ;
    USE SIGNAL ;
    PORT
      LAYER M3 ;
        RECT  34.38 25.882 34.398 25.92 ;
    END
  END i[394]
  PIN i[395]
    DIRECTION INPUT ;
    USE SIGNAL ;
    PORT
      LAYER M3 ;
        RECT  34.452 25.882 34.47 25.92 ;
    END
  END i[395]
  PIN i[396]
    DIRECTION INPUT ;
    USE SIGNAL ;
    PORT
      LAYER M3 ;
        RECT  34.524 25.882 34.542 25.92 ;
    END
  END i[396]
  PIN i[397]
    DIRECTION INPUT ;
    USE SIGNAL ;
    PORT
      LAYER M3 ;
        RECT  34.632 25.882 34.65 25.92 ;
    END
  END i[397]
  PIN i[398]
    DIRECTION INPUT ;
    USE SIGNAL ;
    PORT
      LAYER M3 ;
        RECT  34.704 25.882 34.722 25.92 ;
    END
  END i[398]
  PIN i[399]
    DIRECTION INPUT ;
    USE SIGNAL ;
    PORT
      LAYER M3 ;
        RECT  34.776 25.882 34.794 25.92 ;
    END
  END i[399]
  PIN i[39]
    DIRECTION INPUT ;
    USE SIGNAL ;
    PORT
      LAYER M5 ;
        RECT  5.568 25.836 5.592 25.92 ;
    END
  END i[39]
  PIN i[3]
    DIRECTION INPUT ;
    USE SIGNAL ;
    PORT
      LAYER M3 ;
        RECT  2.664 25.882 2.682 25.92 ;
    END
  END i[3]
  PIN i[400]
    DIRECTION INPUT ;
    USE SIGNAL ;
    PORT
      LAYER M3 ;
        RECT  34.848 25.882 34.866 25.92 ;
    END
  END i[400]
  PIN i[401]
    DIRECTION INPUT ;
    USE SIGNAL ;
    PORT
      LAYER M3 ;
        RECT  34.956 25.882 34.974 25.92 ;
    END
  END i[401]
  PIN i[402]
    DIRECTION INPUT ;
    USE SIGNAL ;
    PORT
      LAYER M3 ;
        RECT  35.028 25.882 35.046 25.92 ;
    END
  END i[402]
  PIN i[403]
    DIRECTION INPUT ;
    USE SIGNAL ;
    PORT
      LAYER M3 ;
        RECT  35.1 25.882 35.118 25.92 ;
    END
  END i[403]
  PIN i[404]
    DIRECTION INPUT ;
    USE SIGNAL ;
    PORT
      LAYER M3 ;
        RECT  35.172 25.882 35.19 25.92 ;
    END
  END i[404]
  PIN i[405]
    DIRECTION INPUT ;
    USE SIGNAL ;
    PORT
      LAYER M3 ;
        RECT  35.28 25.882 35.298 25.92 ;
    END
  END i[405]
  PIN i[406]
    DIRECTION INPUT ;
    USE SIGNAL ;
    PORT
      LAYER M3 ;
        RECT  35.352 25.882 35.37 25.92 ;
    END
  END i[406]
  PIN i[407]
    DIRECTION INPUT ;
    USE SIGNAL ;
    PORT
      LAYER M3 ;
        RECT  35.424 25.882 35.442 25.92 ;
    END
  END i[407]
  PIN i[408]
    DIRECTION INPUT ;
    USE SIGNAL ;
    PORT
      LAYER M3 ;
        RECT  35.496 25.882 35.514 25.92 ;
    END
  END i[408]
  PIN i[409]
    DIRECTION INPUT ;
    USE SIGNAL ;
    PORT
      LAYER M3 ;
        RECT  35.604 25.882 35.622 25.92 ;
    END
  END i[409]
  PIN i[40]
    DIRECTION INPUT ;
    USE SIGNAL ;
    PORT
      LAYER M5 ;
        RECT  5.664 25.836 5.688 25.92 ;
    END
  END i[40]
  PIN i[410]
    DIRECTION INPUT ;
    USE SIGNAL ;
    PORT
      LAYER M3 ;
        RECT  35.676 25.882 35.694 25.92 ;
    END
  END i[410]
  PIN i[411]
    DIRECTION INPUT ;
    USE SIGNAL ;
    PORT
      LAYER M3 ;
        RECT  35.748 25.882 35.766 25.92 ;
    END
  END i[411]
  PIN i[412]
    DIRECTION INPUT ;
    USE SIGNAL ;
    PORT
      LAYER M3 ;
        RECT  35.82 25.882 35.838 25.92 ;
    END
  END i[412]
  PIN i[413]
    DIRECTION INPUT ;
    USE SIGNAL ;
    PORT
      LAYER M3 ;
        RECT  35.928 25.882 35.946 25.92 ;
    END
  END i[413]
  PIN i[414]
    DIRECTION INPUT ;
    USE SIGNAL ;
    PORT
      LAYER M3 ;
        RECT  36 25.882 36.018 25.92 ;
    END
  END i[414]
  PIN i[415]
    DIRECTION INPUT ;
    USE SIGNAL ;
    PORT
      LAYER M3 ;
        RECT  36.072 25.882 36.09 25.92 ;
    END
  END i[415]
  PIN i[416]
    DIRECTION INPUT ;
    USE SIGNAL ;
    PORT
      LAYER M5 ;
        RECT  36.144 25.836 36.168 25.92 ;
    END
  END i[416]
  PIN i[417]
    DIRECTION INPUT ;
    USE SIGNAL ;
    PORT
      LAYER M5 ;
        RECT  36.24 25.836 36.264 25.92 ;
    END
  END i[417]
  PIN i[418]
    DIRECTION INPUT ;
    USE SIGNAL ;
    PORT
      LAYER M5 ;
        RECT  36.336 25.836 36.36 25.92 ;
    END
  END i[418]
  PIN i[419]
    DIRECTION INPUT ;
    USE SIGNAL ;
    PORT
      LAYER M5 ;
        RECT  36.384 25.836 36.408 25.92 ;
    END
  END i[419]
  PIN i[41]
    DIRECTION INPUT ;
    USE SIGNAL ;
    PORT
      LAYER M5 ;
        RECT  5.76 25.836 5.784 25.92 ;
    END
  END i[41]
  PIN i[420]
    DIRECTION INPUT ;
    USE SIGNAL ;
    PORT
      LAYER M5 ;
        RECT  36.48 25.836 36.504 25.92 ;
    END
  END i[420]
  PIN i[421]
    DIRECTION INPUT ;
    USE SIGNAL ;
    PORT
      LAYER M5 ;
        RECT  36.576 25.836 36.6 25.92 ;
    END
  END i[421]
  PIN i[422]
    DIRECTION INPUT ;
    USE SIGNAL ;
    PORT
      LAYER M5 ;
        RECT  36.624 25.836 36.648 25.92 ;
    END
  END i[422]
  PIN i[423]
    DIRECTION INPUT ;
    USE SIGNAL ;
    PORT
      LAYER M5 ;
        RECT  36.72 25.836 36.744 25.92 ;
    END
  END i[423]
  PIN i[424]
    DIRECTION INPUT ;
    USE SIGNAL ;
    PORT
      LAYER M5 ;
        RECT  36.816 25.836 36.84 25.92 ;
    END
  END i[424]
  PIN i[425]
    DIRECTION INPUT ;
    USE SIGNAL ;
    PORT
      LAYER M5 ;
        RECT  36.912 25.836 36.936 25.92 ;
    END
  END i[425]
  PIN i[426]
    DIRECTION INPUT ;
    USE SIGNAL ;
    PORT
      LAYER M5 ;
        RECT  36.96 25.836 36.984 25.92 ;
    END
  END i[426]
  PIN i[427]
    DIRECTION INPUT ;
    USE SIGNAL ;
    PORT
      LAYER M5 ;
        RECT  37.056 25.836 37.08 25.92 ;
    END
  END i[427]
  PIN i[428]
    DIRECTION INPUT ;
    USE SIGNAL ;
    PORT
      LAYER M5 ;
        RECT  37.152 25.836 37.176 25.92 ;
    END
  END i[428]
  PIN i[429]
    DIRECTION INPUT ;
    USE SIGNAL ;
    PORT
      LAYER M5 ;
        RECT  37.2 25.836 37.224 25.92 ;
    END
  END i[429]
  PIN i[42]
    DIRECTION INPUT ;
    USE SIGNAL ;
    PORT
      LAYER M5 ;
        RECT  5.856 25.836 5.88 25.92 ;
    END
  END i[42]
  PIN i[430]
    DIRECTION INPUT ;
    USE SIGNAL ;
    PORT
      LAYER M5 ;
        RECT  37.296 25.836 37.32 25.92 ;
    END
  END i[430]
  PIN i[431]
    DIRECTION INPUT ;
    USE SIGNAL ;
    PORT
      LAYER M5 ;
        RECT  37.392 25.836 37.416 25.92 ;
    END
  END i[431]
  PIN i[432]
    DIRECTION INPUT ;
    USE SIGNAL ;
    PORT
      LAYER M5 ;
        RECT  37.44 25.836 37.464 25.92 ;
    END
  END i[432]
  PIN i[433]
    DIRECTION INPUT ;
    USE SIGNAL ;
    PORT
      LAYER M5 ;
        RECT  37.536 25.836 37.56 25.92 ;
    END
  END i[433]
  PIN i[434]
    DIRECTION INPUT ;
    USE SIGNAL ;
    PORT
      LAYER M5 ;
        RECT  37.632 25.836 37.656 25.92 ;
    END
  END i[434]
  PIN i[435]
    DIRECTION INPUT ;
    USE SIGNAL ;
    PORT
      LAYER M5 ;
        RECT  37.68 25.836 37.704 25.92 ;
    END
  END i[435]
  PIN i[436]
    DIRECTION INPUT ;
    USE SIGNAL ;
    PORT
      LAYER M5 ;
        RECT  37.776 25.836 37.8 25.92 ;
    END
  END i[436]
  PIN i[437]
    DIRECTION INPUT ;
    USE SIGNAL ;
    PORT
      LAYER M5 ;
        RECT  37.872 25.836 37.896 25.92 ;
    END
  END i[437]
  PIN i[438]
    DIRECTION INPUT ;
    USE SIGNAL ;
    PORT
      LAYER M5 ;
        RECT  37.92 25.836 37.944 25.92 ;
    END
  END i[438]
  PIN i[439]
    DIRECTION INPUT ;
    USE SIGNAL ;
    PORT
      LAYER M5 ;
        RECT  38.016 25.836 38.04 25.92 ;
    END
  END i[439]
  PIN i[43]
    DIRECTION INPUT ;
    USE SIGNAL ;
    PORT
      LAYER M5 ;
        RECT  5.904 25.836 5.928 25.92 ;
    END
  END i[43]
  PIN i[440]
    DIRECTION INPUT ;
    USE SIGNAL ;
    PORT
      LAYER M5 ;
        RECT  38.112 25.836 38.136 25.92 ;
    END
  END i[440]
  PIN i[441]
    DIRECTION INPUT ;
    USE SIGNAL ;
    PORT
      LAYER M5 ;
        RECT  38.208 25.836 38.232 25.92 ;
    END
  END i[441]
  PIN i[442]
    DIRECTION INPUT ;
    USE SIGNAL ;
    PORT
      LAYER M5 ;
        RECT  38.256 25.836 38.28 25.92 ;
    END
  END i[442]
  PIN i[443]
    DIRECTION INPUT ;
    USE SIGNAL ;
    PORT
      LAYER M5 ;
        RECT  38.352 25.836 38.376 25.92 ;
    END
  END i[443]
  PIN i[444]
    DIRECTION INPUT ;
    USE SIGNAL ;
    PORT
      LAYER M5 ;
        RECT  38.448 25.836 38.472 25.92 ;
    END
  END i[444]
  PIN i[445]
    DIRECTION INPUT ;
    USE SIGNAL ;
    PORT
      LAYER M5 ;
        RECT  38.496 25.836 38.52 25.92 ;
    END
  END i[445]
  PIN i[446]
    DIRECTION INPUT ;
    USE SIGNAL ;
    PORT
      LAYER M5 ;
        RECT  38.592 25.836 38.616 25.92 ;
    END
  END i[446]
  PIN i[447]
    DIRECTION INPUT ;
    USE SIGNAL ;
    PORT
      LAYER M5 ;
        RECT  38.688 25.836 38.712 25.92 ;
    END
  END i[447]
  PIN i[448]
    DIRECTION INPUT ;
    USE SIGNAL ;
    PORT
      LAYER M3 ;
        RECT  38.772 25.882 38.79 25.92 ;
    END
  END i[448]
  PIN i[449]
    DIRECTION INPUT ;
    USE SIGNAL ;
    PORT
      LAYER M3 ;
        RECT  38.844 25.882 38.862 25.92 ;
    END
  END i[449]
  PIN i[44]
    DIRECTION INPUT ;
    USE SIGNAL ;
    PORT
      LAYER M5 ;
        RECT  6 25.836 6.024 25.92 ;
    END
  END i[44]
  PIN i[450]
    DIRECTION INPUT ;
    USE SIGNAL ;
    PORT
      LAYER M3 ;
        RECT  38.916 25.882 38.934 25.92 ;
    END
  END i[450]
  PIN i[451]
    DIRECTION INPUT ;
    USE SIGNAL ;
    PORT
      LAYER M3 ;
        RECT  38.988 25.882 39.006 25.92 ;
    END
  END i[451]
  PIN i[452]
    DIRECTION INPUT ;
    USE SIGNAL ;
    PORT
      LAYER M3 ;
        RECT  39.096 25.882 39.114 25.92 ;
    END
  END i[452]
  PIN i[453]
    DIRECTION INPUT ;
    USE SIGNAL ;
    PORT
      LAYER M3 ;
        RECT  39.168 25.882 39.186 25.92 ;
    END
  END i[453]
  PIN i[454]
    DIRECTION INPUT ;
    USE SIGNAL ;
    PORT
      LAYER M3 ;
        RECT  39.24 25.882 39.258 25.92 ;
    END
  END i[454]
  PIN i[455]
    DIRECTION INPUT ;
    USE SIGNAL ;
    PORT
      LAYER M3 ;
        RECT  39.312 25.882 39.33 25.92 ;
    END
  END i[455]
  PIN i[456]
    DIRECTION INPUT ;
    USE SIGNAL ;
    PORT
      LAYER M3 ;
        RECT  39.42 25.882 39.438 25.92 ;
    END
  END i[456]
  PIN i[457]
    DIRECTION INPUT ;
    USE SIGNAL ;
    PORT
      LAYER M3 ;
        RECT  39.492 25.882 39.51 25.92 ;
    END
  END i[457]
  PIN i[458]
    DIRECTION INPUT ;
    USE SIGNAL ;
    PORT
      LAYER M3 ;
        RECT  39.564 25.882 39.582 25.92 ;
    END
  END i[458]
  PIN i[459]
    DIRECTION INPUT ;
    USE SIGNAL ;
    PORT
      LAYER M3 ;
        RECT  39.636 25.882 39.654 25.92 ;
    END
  END i[459]
  PIN i[45]
    DIRECTION INPUT ;
    USE SIGNAL ;
    PORT
      LAYER M5 ;
        RECT  6.096 25.836 6.12 25.92 ;
    END
  END i[45]
  PIN i[460]
    DIRECTION INPUT ;
    USE SIGNAL ;
    PORT
      LAYER M3 ;
        RECT  39.744 25.882 39.762 25.92 ;
    END
  END i[460]
  PIN i[461]
    DIRECTION INPUT ;
    USE SIGNAL ;
    PORT
      LAYER M3 ;
        RECT  39.816 25.882 39.834 25.92 ;
    END
  END i[461]
  PIN i[462]
    DIRECTION INPUT ;
    USE SIGNAL ;
    PORT
      LAYER M3 ;
        RECT  39.888 25.882 39.906 25.92 ;
    END
  END i[462]
  PIN i[463]
    DIRECTION INPUT ;
    USE SIGNAL ;
    PORT
      LAYER M3 ;
        RECT  39.96 25.882 39.978 25.92 ;
    END
  END i[463]
  PIN i[464]
    DIRECTION INPUT ;
    USE SIGNAL ;
    PORT
      LAYER M3 ;
        RECT  40.068 25.882 40.086 25.92 ;
    END
  END i[464]
  PIN i[465]
    DIRECTION INPUT ;
    USE SIGNAL ;
    PORT
      LAYER M3 ;
        RECT  40.14 25.882 40.158 25.92 ;
    END
  END i[465]
  PIN i[466]
    DIRECTION INPUT ;
    USE SIGNAL ;
    PORT
      LAYER M3 ;
        RECT  40.212 25.882 40.23 25.92 ;
    END
  END i[466]
  PIN i[467]
    DIRECTION INPUT ;
    USE SIGNAL ;
    PORT
      LAYER M3 ;
        RECT  40.284 25.882 40.302 25.92 ;
    END
  END i[467]
  PIN i[468]
    DIRECTION INPUT ;
    USE SIGNAL ;
    PORT
      LAYER M3 ;
        RECT  40.392 25.882 40.41 25.92 ;
    END
  END i[468]
  PIN i[469]
    DIRECTION INPUT ;
    USE SIGNAL ;
    PORT
      LAYER M3 ;
        RECT  40.464 25.882 40.482 25.92 ;
    END
  END i[469]
  PIN i[46]
    DIRECTION INPUT ;
    USE SIGNAL ;
    PORT
      LAYER M5 ;
        RECT  6.144 25.836 6.168 25.92 ;
    END
  END i[46]
  PIN i[470]
    DIRECTION INPUT ;
    USE SIGNAL ;
    PORT
      LAYER M3 ;
        RECT  40.536 25.882 40.554 25.92 ;
    END
  END i[470]
  PIN i[471]
    DIRECTION INPUT ;
    USE SIGNAL ;
    PORT
      LAYER M3 ;
        RECT  40.608 25.882 40.626 25.92 ;
    END
  END i[471]
  PIN i[472]
    DIRECTION INPUT ;
    USE SIGNAL ;
    PORT
      LAYER M3 ;
        RECT  40.716 25.882 40.734 25.92 ;
    END
  END i[472]
  PIN i[473]
    DIRECTION INPUT ;
    USE SIGNAL ;
    PORT
      LAYER M3 ;
        RECT  40.788 25.882 40.806 25.92 ;
    END
  END i[473]
  PIN i[474]
    DIRECTION INPUT ;
    USE SIGNAL ;
    PORT
      LAYER M3 ;
        RECT  40.86 25.882 40.878 25.92 ;
    END
  END i[474]
  PIN i[475]
    DIRECTION INPUT ;
    USE SIGNAL ;
    PORT
      LAYER M3 ;
        RECT  40.932 25.882 40.95 25.92 ;
    END
  END i[475]
  PIN i[476]
    DIRECTION INPUT ;
    USE SIGNAL ;
    PORT
      LAYER M3 ;
        RECT  41.04 25.882 41.058 25.92 ;
    END
  END i[476]
  PIN i[477]
    DIRECTION INPUT ;
    USE SIGNAL ;
    PORT
      LAYER M3 ;
        RECT  41.112 25.882 41.13 25.92 ;
    END
  END i[477]
  PIN i[478]
    DIRECTION INPUT ;
    USE SIGNAL ;
    PORT
      LAYER M3 ;
        RECT  41.184 25.882 41.202 25.92 ;
    END
  END i[478]
  PIN i[479]
    DIRECTION INPUT ;
    USE SIGNAL ;
    PORT
      LAYER M3 ;
        RECT  41.256 25.882 41.274 25.92 ;
    END
  END i[479]
  PIN i[47]
    DIRECTION INPUT ;
    USE SIGNAL ;
    PORT
      LAYER M5 ;
        RECT  6.24 25.836 6.264 25.92 ;
    END
  END i[47]
  PIN i[480]
    DIRECTION INPUT ;
    USE SIGNAL ;
    PORT
      LAYER M5 ;
        RECT  41.328 25.836 41.352 25.92 ;
    END
  END i[480]
  PIN i[481]
    DIRECTION INPUT ;
    USE SIGNAL ;
    PORT
      LAYER M5 ;
        RECT  41.424 25.836 41.448 25.92 ;
    END
  END i[481]
  PIN i[482]
    DIRECTION INPUT ;
    USE SIGNAL ;
    PORT
      LAYER M5 ;
        RECT  41.52 25.836 41.544 25.92 ;
    END
  END i[482]
  PIN i[483]
    DIRECTION INPUT ;
    USE SIGNAL ;
    PORT
      LAYER M5 ;
        RECT  41.568 25.836 41.592 25.92 ;
    END
  END i[483]
  PIN i[484]
    DIRECTION INPUT ;
    USE SIGNAL ;
    PORT
      LAYER M5 ;
        RECT  41.664 25.836 41.688 25.92 ;
    END
  END i[484]
  PIN i[485]
    DIRECTION INPUT ;
    USE SIGNAL ;
    PORT
      LAYER M5 ;
        RECT  41.76 25.836 41.784 25.92 ;
    END
  END i[485]
  PIN i[486]
    DIRECTION INPUT ;
    USE SIGNAL ;
    PORT
      LAYER M5 ;
        RECT  41.856 25.836 41.88 25.92 ;
    END
  END i[486]
  PIN i[487]
    DIRECTION INPUT ;
    USE SIGNAL ;
    PORT
      LAYER M5 ;
        RECT  41.904 25.836 41.928 25.92 ;
    END
  END i[487]
  PIN i[488]
    DIRECTION INPUT ;
    USE SIGNAL ;
    PORT
      LAYER M5 ;
        RECT  42 25.836 42.024 25.92 ;
    END
  END i[488]
  PIN i[489]
    DIRECTION INPUT ;
    USE SIGNAL ;
    PORT
      LAYER M5 ;
        RECT  42.096 25.836 42.12 25.92 ;
    END
  END i[489]
  PIN i[48]
    DIRECTION INPUT ;
    USE SIGNAL ;
    PORT
      LAYER M5 ;
        RECT  6.336 25.836 6.36 25.92 ;
    END
  END i[48]
  PIN i[490]
    DIRECTION INPUT ;
    USE SIGNAL ;
    PORT
      LAYER M5 ;
        RECT  42.144 25.836 42.168 25.92 ;
    END
  END i[490]
  PIN i[491]
    DIRECTION INPUT ;
    USE SIGNAL ;
    PORT
      LAYER M5 ;
        RECT  42.24 25.836 42.264 25.92 ;
    END
  END i[491]
  PIN i[492]
    DIRECTION INPUT ;
    USE SIGNAL ;
    PORT
      LAYER M5 ;
        RECT  42.336 25.836 42.36 25.92 ;
    END
  END i[492]
  PIN i[493]
    DIRECTION INPUT ;
    USE SIGNAL ;
    PORT
      LAYER M5 ;
        RECT  42.384 25.836 42.408 25.92 ;
    END
  END i[493]
  PIN i[494]
    DIRECTION INPUT ;
    USE SIGNAL ;
    PORT
      LAYER M5 ;
        RECT  42.48 25.836 42.504 25.92 ;
    END
  END i[494]
  PIN i[495]
    DIRECTION INPUT ;
    USE SIGNAL ;
    PORT
      LAYER M5 ;
        RECT  42.576 25.836 42.6 25.92 ;
    END
  END i[495]
  PIN i[496]
    DIRECTION INPUT ;
    USE SIGNAL ;
    PORT
      LAYER M5 ;
        RECT  42.624 25.836 42.648 25.92 ;
    END
  END i[496]
  PIN i[497]
    DIRECTION INPUT ;
    USE SIGNAL ;
    PORT
      LAYER M5 ;
        RECT  42.72 25.836 42.744 25.92 ;
    END
  END i[497]
  PIN i[498]
    DIRECTION INPUT ;
    USE SIGNAL ;
    PORT
      LAYER M5 ;
        RECT  42.816 25.836 42.84 25.92 ;
    END
  END i[498]
  PIN i[499]
    DIRECTION INPUT ;
    USE SIGNAL ;
    PORT
      LAYER M5 ;
        RECT  42.912 25.836 42.936 25.92 ;
    END
  END i[499]
  PIN i[49]
    DIRECTION INPUT ;
    USE SIGNAL ;
    PORT
      LAYER M5 ;
        RECT  6.384 25.836 6.408 25.92 ;
    END
  END i[49]
  PIN i[4]
    DIRECTION INPUT ;
    USE SIGNAL ;
    PORT
      LAYER M3 ;
        RECT  2.772 25.882 2.79 25.92 ;
    END
  END i[4]
  PIN i[500]
    DIRECTION INPUT ;
    USE SIGNAL ;
    PORT
      LAYER M5 ;
        RECT  42.96 25.836 42.984 25.92 ;
    END
  END i[500]
  PIN i[501]
    DIRECTION INPUT ;
    USE SIGNAL ;
    PORT
      LAYER M5 ;
        RECT  43.056 25.836 43.08 25.92 ;
    END
  END i[501]
  PIN i[502]
    DIRECTION INPUT ;
    USE SIGNAL ;
    PORT
      LAYER M5 ;
        RECT  43.152 25.836 43.176 25.92 ;
    END
  END i[502]
  PIN i[503]
    DIRECTION INPUT ;
    USE SIGNAL ;
    PORT
      LAYER M5 ;
        RECT  43.2 25.836 43.224 25.92 ;
    END
  END i[503]
  PIN i[504]
    DIRECTION INPUT ;
    USE SIGNAL ;
    PORT
      LAYER M5 ;
        RECT  43.296 25.836 43.32 25.92 ;
    END
  END i[504]
  PIN i[505]
    DIRECTION INPUT ;
    USE SIGNAL ;
    PORT
      LAYER M5 ;
        RECT  43.392 25.836 43.416 25.92 ;
    END
  END i[505]
  PIN i[506]
    DIRECTION INPUT ;
    USE SIGNAL ;
    PORT
      LAYER M5 ;
        RECT  43.44 25.836 43.464 25.92 ;
    END
  END i[506]
  PIN i[507]
    DIRECTION INPUT ;
    USE SIGNAL ;
    PORT
      LAYER M5 ;
        RECT  43.536 25.836 43.56 25.92 ;
    END
  END i[507]
  PIN i[508]
    DIRECTION INPUT ;
    USE SIGNAL ;
    PORT
      LAYER M5 ;
        RECT  43.632 25.836 43.656 25.92 ;
    END
  END i[508]
  PIN i[509]
    DIRECTION INPUT ;
    USE SIGNAL ;
    PORT
      LAYER M5 ;
        RECT  43.68 25.836 43.704 25.92 ;
    END
  END i[509]
  PIN i[50]
    DIRECTION INPUT ;
    USE SIGNAL ;
    PORT
      LAYER M5 ;
        RECT  6.48 25.836 6.504 25.92 ;
    END
  END i[50]
  PIN i[510]
    DIRECTION INPUT ;
    USE SIGNAL ;
    PORT
      LAYER M5 ;
        RECT  43.776 25.836 43.8 25.92 ;
    END
  END i[510]
  PIN i[511]
    DIRECTION INPUT ;
    USE SIGNAL ;
    PORT
      LAYER M5 ;
        RECT  43.872 25.836 43.896 25.92 ;
    END
  END i[511]
  PIN i[512]
    DIRECTION INPUT ;
    USE SIGNAL ;
    PORT
      LAYER M3 ;
        RECT  43.956 25.882 43.974 25.92 ;
    END
  END i[512]
  PIN i[513]
    DIRECTION INPUT ;
    USE SIGNAL ;
    PORT
      LAYER M3 ;
        RECT  44.028 25.882 44.046 25.92 ;
    END
  END i[513]
  PIN i[514]
    DIRECTION INPUT ;
    USE SIGNAL ;
    PORT
      LAYER M3 ;
        RECT  44.1 25.882 44.118 25.92 ;
    END
  END i[514]
  PIN i[515]
    DIRECTION INPUT ;
    USE SIGNAL ;
    PORT
      LAYER M3 ;
        RECT  44.172 25.882 44.19 25.92 ;
    END
  END i[515]
  PIN i[516]
    DIRECTION INPUT ;
    USE SIGNAL ;
    PORT
      LAYER M3 ;
        RECT  44.28 25.882 44.298 25.92 ;
    END
  END i[516]
  PIN i[517]
    DIRECTION INPUT ;
    USE SIGNAL ;
    PORT
      LAYER M3 ;
        RECT  44.352 25.882 44.37 25.92 ;
    END
  END i[517]
  PIN i[518]
    DIRECTION INPUT ;
    USE SIGNAL ;
    PORT
      LAYER M3 ;
        RECT  44.424 25.882 44.442 25.92 ;
    END
  END i[518]
  PIN i[519]
    DIRECTION INPUT ;
    USE SIGNAL ;
    PORT
      LAYER M3 ;
        RECT  44.496 25.882 44.514 25.92 ;
    END
  END i[519]
  PIN i[51]
    DIRECTION INPUT ;
    USE SIGNAL ;
    PORT
      LAYER M5 ;
        RECT  6.576 25.836 6.6 25.92 ;
    END
  END i[51]
  PIN i[520]
    DIRECTION INPUT ;
    USE SIGNAL ;
    PORT
      LAYER M3 ;
        RECT  44.604 25.882 44.622 25.92 ;
    END
  END i[520]
  PIN i[521]
    DIRECTION INPUT ;
    USE SIGNAL ;
    PORT
      LAYER M3 ;
        RECT  44.676 25.882 44.694 25.92 ;
    END
  END i[521]
  PIN i[522]
    DIRECTION INPUT ;
    USE SIGNAL ;
    PORT
      LAYER M3 ;
        RECT  44.748 25.882 44.766 25.92 ;
    END
  END i[522]
  PIN i[523]
    DIRECTION INPUT ;
    USE SIGNAL ;
    PORT
      LAYER M3 ;
        RECT  44.82 25.882 44.838 25.92 ;
    END
  END i[523]
  PIN i[524]
    DIRECTION INPUT ;
    USE SIGNAL ;
    PORT
      LAYER M3 ;
        RECT  44.928 25.882 44.946 25.92 ;
    END
  END i[524]
  PIN i[525]
    DIRECTION INPUT ;
    USE SIGNAL ;
    PORT
      LAYER M3 ;
        RECT  45 25.882 45.018 25.92 ;
    END
  END i[525]
  PIN i[526]
    DIRECTION INPUT ;
    USE SIGNAL ;
    PORT
      LAYER M3 ;
        RECT  45.072 25.882 45.09 25.92 ;
    END
  END i[526]
  PIN i[527]
    DIRECTION INPUT ;
    USE SIGNAL ;
    PORT
      LAYER M3 ;
        RECT  45.144 25.882 45.162 25.92 ;
    END
  END i[527]
  PIN i[528]
    DIRECTION INPUT ;
    USE SIGNAL ;
    PORT
      LAYER M3 ;
        RECT  45.252 25.882 45.27 25.92 ;
    END
  END i[528]
  PIN i[529]
    DIRECTION INPUT ;
    USE SIGNAL ;
    PORT
      LAYER M3 ;
        RECT  45.324 25.882 45.342 25.92 ;
    END
  END i[529]
  PIN i[52]
    DIRECTION INPUT ;
    USE SIGNAL ;
    PORT
      LAYER M5 ;
        RECT  6.624 25.836 6.648 25.92 ;
    END
  END i[52]
  PIN i[530]
    DIRECTION INPUT ;
    USE SIGNAL ;
    PORT
      LAYER M3 ;
        RECT  45.396 25.882 45.414 25.92 ;
    END
  END i[530]
  PIN i[531]
    DIRECTION INPUT ;
    USE SIGNAL ;
    PORT
      LAYER M3 ;
        RECT  45.504 25.882 45.522 25.92 ;
    END
  END i[531]
  PIN i[532]
    DIRECTION INPUT ;
    USE SIGNAL ;
    PORT
      LAYER M3 ;
        RECT  45.576 25.882 45.594 25.92 ;
    END
  END i[532]
  PIN i[533]
    DIRECTION INPUT ;
    USE SIGNAL ;
    PORT
      LAYER M3 ;
        RECT  45.648 25.882 45.666 25.92 ;
    END
  END i[533]
  PIN i[534]
    DIRECTION INPUT ;
    USE SIGNAL ;
    PORT
      LAYER M3 ;
        RECT  45.72 25.882 45.738 25.92 ;
    END
  END i[534]
  PIN i[535]
    DIRECTION INPUT ;
    USE SIGNAL ;
    PORT
      LAYER M3 ;
        RECT  45.828 25.882 45.846 25.92 ;
    END
  END i[535]
  PIN i[536]
    DIRECTION INPUT ;
    USE SIGNAL ;
    PORT
      LAYER M3 ;
        RECT  45.9 25.882 45.918 25.92 ;
    END
  END i[536]
  PIN i[537]
    DIRECTION INPUT ;
    USE SIGNAL ;
    PORT
      LAYER M3 ;
        RECT  45.972 25.882 45.99 25.92 ;
    END
  END i[537]
  PIN i[538]
    DIRECTION INPUT ;
    USE SIGNAL ;
    PORT
      LAYER M3 ;
        RECT  46.044 25.882 46.062 25.92 ;
    END
  END i[538]
  PIN i[539]
    DIRECTION INPUT ;
    USE SIGNAL ;
    PORT
      LAYER M3 ;
        RECT  46.152 25.882 46.17 25.92 ;
    END
  END i[539]
  PIN i[53]
    DIRECTION INPUT ;
    USE SIGNAL ;
    PORT
      LAYER M5 ;
        RECT  6.72 25.836 6.744 25.92 ;
    END
  END i[53]
  PIN i[540]
    DIRECTION INPUT ;
    USE SIGNAL ;
    PORT
      LAYER M3 ;
        RECT  46.224 25.882 46.242 25.92 ;
    END
  END i[540]
  PIN i[541]
    DIRECTION INPUT ;
    USE SIGNAL ;
    PORT
      LAYER M3 ;
        RECT  46.296 25.882 46.314 25.92 ;
    END
  END i[541]
  PIN i[542]
    DIRECTION INPUT ;
    USE SIGNAL ;
    PORT
      LAYER M3 ;
        RECT  46.368 25.882 46.386 25.92 ;
    END
  END i[542]
  PIN i[543]
    DIRECTION INPUT ;
    USE SIGNAL ;
    PORT
      LAYER M3 ;
        RECT  46.476 25.882 46.494 25.92 ;
    END
  END i[543]
  PIN i[544]
    DIRECTION INPUT ;
    USE SIGNAL ;
    PORT
      LAYER M5 ;
        RECT  46.56 25.836 46.584 25.92 ;
    END
  END i[544]
  PIN i[545]
    DIRECTION INPUT ;
    USE SIGNAL ;
    PORT
      LAYER M5 ;
        RECT  46.608 25.836 46.632 25.92 ;
    END
  END i[545]
  PIN i[546]
    DIRECTION INPUT ;
    USE SIGNAL ;
    PORT
      LAYER M5 ;
        RECT  46.704 25.836 46.728 25.92 ;
    END
  END i[546]
  PIN i[547]
    DIRECTION INPUT ;
    USE SIGNAL ;
    PORT
      LAYER M5 ;
        RECT  46.8 25.836 46.824 25.92 ;
    END
  END i[547]
  PIN i[548]
    DIRECTION INPUT ;
    USE SIGNAL ;
    PORT
      LAYER M5 ;
        RECT  46.848 25.836 46.872 25.92 ;
    END
  END i[548]
  PIN i[549]
    DIRECTION INPUT ;
    USE SIGNAL ;
    PORT
      LAYER M5 ;
        RECT  46.944 25.836 46.968 25.92 ;
    END
  END i[549]
  PIN i[54]
    DIRECTION INPUT ;
    USE SIGNAL ;
    PORT
      LAYER M5 ;
        RECT  6.816 25.836 6.84 25.92 ;
    END
  END i[54]
  PIN i[550]
    DIRECTION INPUT ;
    USE SIGNAL ;
    PORT
      LAYER M5 ;
        RECT  47.04 25.836 47.064 25.92 ;
    END
  END i[550]
  PIN i[551]
    DIRECTION INPUT ;
    USE SIGNAL ;
    PORT
      LAYER M5 ;
        RECT  47.088 25.836 47.112 25.92 ;
    END
  END i[551]
  PIN i[552]
    DIRECTION INPUT ;
    USE SIGNAL ;
    PORT
      LAYER M5 ;
        RECT  47.184 25.836 47.208 25.92 ;
    END
  END i[552]
  PIN i[553]
    DIRECTION INPUT ;
    USE SIGNAL ;
    PORT
      LAYER M5 ;
        RECT  47.28 25.836 47.304 25.92 ;
    END
  END i[553]
  PIN i[554]
    DIRECTION INPUT ;
    USE SIGNAL ;
    PORT
      LAYER M5 ;
        RECT  47.328 25.836 47.352 25.92 ;
    END
  END i[554]
  PIN i[555]
    DIRECTION INPUT ;
    USE SIGNAL ;
    PORT
      LAYER M5 ;
        RECT  47.424 25.836 47.448 25.92 ;
    END
  END i[555]
  PIN i[556]
    DIRECTION INPUT ;
    USE SIGNAL ;
    PORT
      LAYER M5 ;
        RECT  47.52 25.836 47.544 25.92 ;
    END
  END i[556]
  PIN i[557]
    DIRECTION INPUT ;
    USE SIGNAL ;
    PORT
      LAYER M5 ;
        RECT  47.568 25.836 47.592 25.92 ;
    END
  END i[557]
  PIN i[558]
    DIRECTION INPUT ;
    USE SIGNAL ;
    PORT
      LAYER M5 ;
        RECT  47.664 25.836 47.688 25.92 ;
    END
  END i[558]
  PIN i[559]
    DIRECTION INPUT ;
    USE SIGNAL ;
    PORT
      LAYER M5 ;
        RECT  47.76 25.836 47.784 25.92 ;
    END
  END i[559]
  PIN i[55]
    DIRECTION INPUT ;
    USE SIGNAL ;
    PORT
      LAYER M5 ;
        RECT  6.912 25.836 6.936 25.92 ;
    END
  END i[55]
  PIN i[560]
    DIRECTION INPUT ;
    USE SIGNAL ;
    PORT
      LAYER M5 ;
        RECT  47.856 25.836 47.88 25.92 ;
    END
  END i[560]
  PIN i[561]
    DIRECTION INPUT ;
    USE SIGNAL ;
    PORT
      LAYER M5 ;
        RECT  47.904 25.836 47.928 25.92 ;
    END
  END i[561]
  PIN i[562]
    DIRECTION INPUT ;
    USE SIGNAL ;
    PORT
      LAYER M5 ;
        RECT  48 25.836 48.024 25.92 ;
    END
  END i[562]
  PIN i[563]
    DIRECTION INPUT ;
    USE SIGNAL ;
    PORT
      LAYER M5 ;
        RECT  48.096 25.836 48.12 25.92 ;
    END
  END i[563]
  PIN i[564]
    DIRECTION INPUT ;
    USE SIGNAL ;
    PORT
      LAYER M5 ;
        RECT  48.144 25.836 48.168 25.92 ;
    END
  END i[564]
  PIN i[565]
    DIRECTION INPUT ;
    USE SIGNAL ;
    PORT
      LAYER M5 ;
        RECT  48.24 25.836 48.264 25.92 ;
    END
  END i[565]
  PIN i[566]
    DIRECTION INPUT ;
    USE SIGNAL ;
    PORT
      LAYER M5 ;
        RECT  48.336 25.836 48.36 25.92 ;
    END
  END i[566]
  PIN i[567]
    DIRECTION INPUT ;
    USE SIGNAL ;
    PORT
      LAYER M5 ;
        RECT  48.384 25.836 48.408 25.92 ;
    END
  END i[567]
  PIN i[568]
    DIRECTION INPUT ;
    USE SIGNAL ;
    PORT
      LAYER M5 ;
        RECT  48.48 25.836 48.504 25.92 ;
    END
  END i[568]
  PIN i[569]
    DIRECTION INPUT ;
    USE SIGNAL ;
    PORT
      LAYER M5 ;
        RECT  48.576 25.836 48.6 25.92 ;
    END
  END i[569]
  PIN i[56]
    DIRECTION INPUT ;
    USE SIGNAL ;
    PORT
      LAYER M5 ;
        RECT  6.96 25.836 6.984 25.92 ;
    END
  END i[56]
  PIN i[570]
    DIRECTION INPUT ;
    USE SIGNAL ;
    PORT
      LAYER M5 ;
        RECT  48.624 25.836 48.648 25.92 ;
    END
  END i[570]
  PIN i[571]
    DIRECTION INPUT ;
    USE SIGNAL ;
    PORT
      LAYER M5 ;
        RECT  48.72 25.836 48.744 25.92 ;
    END
  END i[571]
  PIN i[572]
    DIRECTION INPUT ;
    USE SIGNAL ;
    PORT
      LAYER M5 ;
        RECT  48.816 25.836 48.84 25.92 ;
    END
  END i[572]
  PIN i[573]
    DIRECTION INPUT ;
    USE SIGNAL ;
    PORT
      LAYER M5 ;
        RECT  48.912 25.836 48.936 25.92 ;
    END
  END i[573]
  PIN i[574]
    DIRECTION INPUT ;
    USE SIGNAL ;
    PORT
      LAYER M5 ;
        RECT  48.96 25.836 48.984 25.92 ;
    END
  END i[574]
  PIN i[575]
    DIRECTION INPUT ;
    USE SIGNAL ;
    PORT
      LAYER M5 ;
        RECT  49.056 25.836 49.08 25.92 ;
    END
  END i[575]
  PIN i[576]
    DIRECTION INPUT ;
    USE SIGNAL ;
    PORT
      LAYER M3 ;
        RECT  49.14 25.882 49.158 25.92 ;
    END
  END i[576]
  PIN i[577]
    DIRECTION INPUT ;
    USE SIGNAL ;
    PORT
      LAYER M3 ;
        RECT  49.212 25.882 49.23 25.92 ;
    END
  END i[577]
  PIN i[578]
    DIRECTION INPUT ;
    USE SIGNAL ;
    PORT
      LAYER M3 ;
        RECT  49.284 25.882 49.302 25.92 ;
    END
  END i[578]
  PIN i[579]
    DIRECTION INPUT ;
    USE SIGNAL ;
    PORT
      LAYER M3 ;
        RECT  49.392 25.882 49.41 25.92 ;
    END
  END i[579]
  PIN i[57]
    DIRECTION INPUT ;
    USE SIGNAL ;
    PORT
      LAYER M5 ;
        RECT  7.056 25.836 7.08 25.92 ;
    END
  END i[57]
  PIN i[580]
    DIRECTION INPUT ;
    USE SIGNAL ;
    PORT
      LAYER M3 ;
        RECT  49.464 25.882 49.482 25.92 ;
    END
  END i[580]
  PIN i[581]
    DIRECTION INPUT ;
    USE SIGNAL ;
    PORT
      LAYER M3 ;
        RECT  49.536 25.882 49.554 25.92 ;
    END
  END i[581]
  PIN i[582]
    DIRECTION INPUT ;
    USE SIGNAL ;
    PORT
      LAYER M3 ;
        RECT  49.608 25.882 49.626 25.92 ;
    END
  END i[582]
  PIN i[583]
    DIRECTION INPUT ;
    USE SIGNAL ;
    PORT
      LAYER M3 ;
        RECT  49.716 25.882 49.734 25.92 ;
    END
  END i[583]
  PIN i[584]
    DIRECTION INPUT ;
    USE SIGNAL ;
    PORT
      LAYER M3 ;
        RECT  49.788 25.882 49.806 25.92 ;
    END
  END i[584]
  PIN i[585]
    DIRECTION INPUT ;
    USE SIGNAL ;
    PORT
      LAYER M3 ;
        RECT  49.86 25.882 49.878 25.92 ;
    END
  END i[585]
  PIN i[586]
    DIRECTION INPUT ;
    USE SIGNAL ;
    PORT
      LAYER M3 ;
        RECT  49.932 25.882 49.95 25.92 ;
    END
  END i[586]
  PIN i[587]
    DIRECTION INPUT ;
    USE SIGNAL ;
    PORT
      LAYER M3 ;
        RECT  50.04 25.882 50.058 25.92 ;
    END
  END i[587]
  PIN i[588]
    DIRECTION INPUT ;
    USE SIGNAL ;
    PORT
      LAYER M3 ;
        RECT  50.112 25.882 50.13 25.92 ;
    END
  END i[588]
  PIN i[589]
    DIRECTION INPUT ;
    USE SIGNAL ;
    PORT
      LAYER M3 ;
        RECT  50.184 25.882 50.202 25.92 ;
    END
  END i[589]
  PIN i[58]
    DIRECTION INPUT ;
    USE SIGNAL ;
    PORT
      LAYER M5 ;
        RECT  7.152 25.836 7.176 25.92 ;
    END
  END i[58]
  PIN i[590]
    DIRECTION INPUT ;
    USE SIGNAL ;
    PORT
      LAYER M3 ;
        RECT  50.256 25.882 50.274 25.92 ;
    END
  END i[590]
  PIN i[591]
    DIRECTION INPUT ;
    USE SIGNAL ;
    PORT
      LAYER M3 ;
        RECT  50.364 25.882 50.382 25.92 ;
    END
  END i[591]
  PIN i[59]
    DIRECTION INPUT ;
    USE SIGNAL ;
    PORT
      LAYER M5 ;
        RECT  7.2 25.836 7.224 25.92 ;
    END
  END i[59]
  PIN i[5]
    DIRECTION INPUT ;
    USE SIGNAL ;
    PORT
      LAYER M3 ;
        RECT  2.844 25.882 2.862 25.92 ;
    END
  END i[5]
  PIN i[60]
    DIRECTION INPUT ;
    USE SIGNAL ;
    PORT
      LAYER M5 ;
        RECT  7.296 25.836 7.32 25.92 ;
    END
  END i[60]
  PIN i[61]
    DIRECTION INPUT ;
    USE SIGNAL ;
    PORT
      LAYER M5 ;
        RECT  7.392 25.836 7.416 25.92 ;
    END
  END i[61]
  PIN i[62]
    DIRECTION INPUT ;
    USE SIGNAL ;
    PORT
      LAYER M5 ;
        RECT  7.44 25.836 7.464 25.92 ;
    END
  END i[62]
  PIN i[63]
    DIRECTION INPUT ;
    USE SIGNAL ;
    PORT
      LAYER M5 ;
        RECT  7.536 25.836 7.56 25.92 ;
    END
  END i[63]
  PIN i[64]
    DIRECTION INPUT ;
    USE SIGNAL ;
    PORT
      LAYER M3 ;
        RECT  7.632 25.882 7.65 25.92 ;
    END
  END i[64]
  PIN i[65]
    DIRECTION INPUT ;
    USE SIGNAL ;
    PORT
      LAYER M3 ;
        RECT  7.704 25.882 7.722 25.92 ;
    END
  END i[65]
  PIN i[66]
    DIRECTION INPUT ;
    USE SIGNAL ;
    PORT
      LAYER M3 ;
        RECT  7.776 25.882 7.794 25.92 ;
    END
  END i[66]
  PIN i[67]
    DIRECTION INPUT ;
    USE SIGNAL ;
    PORT
      LAYER M3 ;
        RECT  7.848 25.882 7.866 25.92 ;
    END
  END i[67]
  PIN i[68]
    DIRECTION INPUT ;
    USE SIGNAL ;
    PORT
      LAYER M3 ;
        RECT  7.956 25.882 7.974 25.92 ;
    END
  END i[68]
  PIN i[69]
    DIRECTION INPUT ;
    USE SIGNAL ;
    PORT
      LAYER M3 ;
        RECT  8.028 25.882 8.046 25.92 ;
    END
  END i[69]
  PIN i[6]
    DIRECTION INPUT ;
    USE SIGNAL ;
    PORT
      LAYER M3 ;
        RECT  2.916 25.882 2.934 25.92 ;
    END
  END i[6]
  PIN i[70]
    DIRECTION INPUT ;
    USE SIGNAL ;
    PORT
      LAYER M3 ;
        RECT  8.1 25.882 8.118 25.92 ;
    END
  END i[70]
  PIN i[71]
    DIRECTION INPUT ;
    USE SIGNAL ;
    PORT
      LAYER M3 ;
        RECT  8.172 25.882 8.19 25.92 ;
    END
  END i[71]
  PIN i[72]
    DIRECTION INPUT ;
    USE SIGNAL ;
    PORT
      LAYER M3 ;
        RECT  8.28 25.882 8.298 25.92 ;
    END
  END i[72]
  PIN i[73]
    DIRECTION INPUT ;
    USE SIGNAL ;
    PORT
      LAYER M3 ;
        RECT  8.352 25.882 8.37 25.92 ;
    END
  END i[73]
  PIN i[74]
    DIRECTION INPUT ;
    USE SIGNAL ;
    PORT
      LAYER M3 ;
        RECT  8.424 25.882 8.442 25.92 ;
    END
  END i[74]
  PIN i[75]
    DIRECTION INPUT ;
    USE SIGNAL ;
    PORT
      LAYER M3 ;
        RECT  8.496 25.882 8.514 25.92 ;
    END
  END i[75]
  PIN i[76]
    DIRECTION INPUT ;
    USE SIGNAL ;
    PORT
      LAYER M3 ;
        RECT  8.604 25.882 8.622 25.92 ;
    END
  END i[76]
  PIN i[77]
    DIRECTION INPUT ;
    USE SIGNAL ;
    PORT
      LAYER M3 ;
        RECT  8.676 25.882 8.694 25.92 ;
    END
  END i[77]
  PIN i[78]
    DIRECTION INPUT ;
    USE SIGNAL ;
    PORT
      LAYER M3 ;
        RECT  8.748 25.882 8.766 25.92 ;
    END
  END i[78]
  PIN i[79]
    DIRECTION INPUT ;
    USE SIGNAL ;
    PORT
      LAYER M3 ;
        RECT  8.82 25.882 8.838 25.92 ;
    END
  END i[79]
  PIN i[7]
    DIRECTION INPUT ;
    USE SIGNAL ;
    PORT
      LAYER M3 ;
        RECT  2.988 25.882 3.006 25.92 ;
    END
  END i[7]
  PIN i[80]
    DIRECTION INPUT ;
    USE SIGNAL ;
    PORT
      LAYER M3 ;
        RECT  8.928 25.882 8.946 25.92 ;
    END
  END i[80]
  PIN i[81]
    DIRECTION INPUT ;
    USE SIGNAL ;
    PORT
      LAYER M3 ;
        RECT  9 25.882 9.018 25.92 ;
    END
  END i[81]
  PIN i[82]
    DIRECTION INPUT ;
    USE SIGNAL ;
    PORT
      LAYER M3 ;
        RECT  9.072 25.882 9.09 25.92 ;
    END
  END i[82]
  PIN i[83]
    DIRECTION INPUT ;
    USE SIGNAL ;
    PORT
      LAYER M3 ;
        RECT  9.144 25.882 9.162 25.92 ;
    END
  END i[83]
  PIN i[84]
    DIRECTION INPUT ;
    USE SIGNAL ;
    PORT
      LAYER M3 ;
        RECT  9.252 25.882 9.27 25.92 ;
    END
  END i[84]
  PIN i[85]
    DIRECTION INPUT ;
    USE SIGNAL ;
    PORT
      LAYER M3 ;
        RECT  9.324 25.882 9.342 25.92 ;
    END
  END i[85]
  PIN i[86]
    DIRECTION INPUT ;
    USE SIGNAL ;
    PORT
      LAYER M3 ;
        RECT  9.396 25.882 9.414 25.92 ;
    END
  END i[86]
  PIN i[87]
    DIRECTION INPUT ;
    USE SIGNAL ;
    PORT
      LAYER M3 ;
        RECT  9.504 25.882 9.522 25.92 ;
    END
  END i[87]
  PIN i[88]
    DIRECTION INPUT ;
    USE SIGNAL ;
    PORT
      LAYER M3 ;
        RECT  9.576 25.882 9.594 25.92 ;
    END
  END i[88]
  PIN i[89]
    DIRECTION INPUT ;
    USE SIGNAL ;
    PORT
      LAYER M3 ;
        RECT  9.648 25.882 9.666 25.92 ;
    END
  END i[89]
  PIN i[8]
    DIRECTION INPUT ;
    USE SIGNAL ;
    PORT
      LAYER M3 ;
        RECT  3.096 25.882 3.114 25.92 ;
    END
  END i[8]
  PIN i[90]
    DIRECTION INPUT ;
    USE SIGNAL ;
    PORT
      LAYER M3 ;
        RECT  9.72 25.882 9.738 25.92 ;
    END
  END i[90]
  PIN i[91]
    DIRECTION INPUT ;
    USE SIGNAL ;
    PORT
      LAYER M3 ;
        RECT  9.828 25.882 9.846 25.92 ;
    END
  END i[91]
  PIN i[92]
    DIRECTION INPUT ;
    USE SIGNAL ;
    PORT
      LAYER M3 ;
        RECT  9.9 25.882 9.918 25.92 ;
    END
  END i[92]
  PIN i[93]
    DIRECTION INPUT ;
    USE SIGNAL ;
    PORT
      LAYER M3 ;
        RECT  9.972 25.882 9.99 25.92 ;
    END
  END i[93]
  PIN i[94]
    DIRECTION INPUT ;
    USE SIGNAL ;
    PORT
      LAYER M3 ;
        RECT  10.044 25.882 10.062 25.92 ;
    END
  END i[94]
  PIN i[95]
    DIRECTION INPUT ;
    USE SIGNAL ;
    PORT
      LAYER M3 ;
        RECT  10.152 25.882 10.17 25.92 ;
    END
  END i[95]
  PIN i[96]
    DIRECTION INPUT ;
    USE SIGNAL ;
    PORT
      LAYER M5 ;
        RECT  10.224 25.836 10.248 25.92 ;
    END
  END i[96]
  PIN i[97]
    DIRECTION INPUT ;
    USE SIGNAL ;
    PORT
      LAYER M5 ;
        RECT  10.272 25.836 10.296 25.92 ;
    END
  END i[97]
  PIN i[98]
    DIRECTION INPUT ;
    USE SIGNAL ;
    PORT
      LAYER M5 ;
        RECT  10.368 25.836 10.392 25.92 ;
    END
  END i[98]
  PIN i[99]
    DIRECTION INPUT ;
    USE SIGNAL ;
    PORT
      LAYER M5 ;
        RECT  10.464 25.836 10.488 25.92 ;
    END
  END i[99]
  PIN i[9]
    DIRECTION INPUT ;
    USE SIGNAL ;
    PORT
      LAYER M3 ;
        RECT  3.168 25.882 3.186 25.92 ;
    END
  END i[9]
  PIN i_rf[0]
    DIRECTION INPUT ;
    USE SIGNAL ;
    PORT
      LAYER M3 ;
        RECT  50.724 25.882 50.742 25.92 ;
    END
  END i_rf[0]
  PIN i_rf[1]
    DIRECTION INPUT ;
    USE SIGNAL ;
    PORT
      LAYER M3 ;
        RECT  50.976 25.882 50.994 25.92 ;
    END
  END i_rf[1]
  PIN i_rf[2]
    DIRECTION INPUT ;
    USE SIGNAL ;
    PORT
      LAYER M3 ;
        RECT  51.228 25.882 51.246 25.92 ;
    END
  END i_rf[2]
  PIN i_rf[3]
    DIRECTION INPUT ;
    USE SIGNAL ;
    PORT
      LAYER M3 ;
        RECT  51.48 25.882 51.498 25.92 ;
    END
  END i_rf[3]
  PIN o[0]
    DIRECTION OUTPUT ;
    USE SIGNAL ;
    PORT
      LAYER M3 ;
        RECT  2.448 0 2.466 0.038 ;
    END
  END o[0]
  PIN o[100]
    DIRECTION OUTPUT ;
    USE SIGNAL ;
    PORT
      LAYER M5 ;
        RECT  10.56 0 10.584 0.084 ;
    END
  END o[100]
  PIN o[101]
    DIRECTION OUTPUT ;
    USE SIGNAL ;
    PORT
      LAYER M5 ;
        RECT  10.608 0 10.632 0.084 ;
    END
  END o[101]
  PIN o[102]
    DIRECTION OUTPUT ;
    USE SIGNAL ;
    PORT
      LAYER M5 ;
        RECT  10.704 0 10.728 0.084 ;
    END
  END o[102]
  PIN o[103]
    DIRECTION OUTPUT ;
    USE SIGNAL ;
    PORT
      LAYER M5 ;
        RECT  10.8 0 10.824 0.084 ;
    END
  END o[103]
  PIN o[104]
    DIRECTION OUTPUT ;
    USE SIGNAL ;
    PORT
      LAYER M5 ;
        RECT  10.848 0 10.872 0.084 ;
    END
  END o[104]
  PIN o[105]
    DIRECTION OUTPUT ;
    USE SIGNAL ;
    PORT
      LAYER M5 ;
        RECT  10.944 0 10.968 0.084 ;
    END
  END o[105]
  PIN o[106]
    DIRECTION OUTPUT ;
    USE SIGNAL ;
    PORT
      LAYER M5 ;
        RECT  11.04 0 11.064 0.084 ;
    END
  END o[106]
  PIN o[107]
    DIRECTION OUTPUT ;
    USE SIGNAL ;
    PORT
      LAYER M5 ;
        RECT  11.088 0 11.112 0.084 ;
    END
  END o[107]
  PIN o[108]
    DIRECTION OUTPUT ;
    USE SIGNAL ;
    PORT
      LAYER M5 ;
        RECT  11.184 0 11.208 0.084 ;
    END
  END o[108]
  PIN o[109]
    DIRECTION OUTPUT ;
    USE SIGNAL ;
    PORT
      LAYER M5 ;
        RECT  11.28 0 11.304 0.084 ;
    END
  END o[109]
  PIN o[10]
    DIRECTION OUTPUT ;
    USE SIGNAL ;
    PORT
      LAYER M3 ;
        RECT  3.24 0 3.258 0.038 ;
    END
  END o[10]
  PIN o[110]
    DIRECTION OUTPUT ;
    USE SIGNAL ;
    PORT
      LAYER M5 ;
        RECT  11.328 0 11.352 0.084 ;
    END
  END o[110]
  PIN o[111]
    DIRECTION OUTPUT ;
    USE SIGNAL ;
    PORT
      LAYER M5 ;
        RECT  11.424 0 11.448 0.084 ;
    END
  END o[111]
  PIN o[112]
    DIRECTION OUTPUT ;
    USE SIGNAL ;
    PORT
      LAYER M5 ;
        RECT  11.52 0 11.544 0.084 ;
    END
  END o[112]
  PIN o[113]
    DIRECTION OUTPUT ;
    USE SIGNAL ;
    PORT
      LAYER M5 ;
        RECT  11.568 0 11.592 0.084 ;
    END
  END o[113]
  PIN o[114]
    DIRECTION OUTPUT ;
    USE SIGNAL ;
    PORT
      LAYER M5 ;
        RECT  11.664 0 11.688 0.084 ;
    END
  END o[114]
  PIN o[115]
    DIRECTION OUTPUT ;
    USE SIGNAL ;
    PORT
      LAYER M5 ;
        RECT  11.76 0 11.784 0.084 ;
    END
  END o[115]
  PIN o[116]
    DIRECTION OUTPUT ;
    USE SIGNAL ;
    PORT
      LAYER M5 ;
        RECT  11.856 0 11.88 0.084 ;
    END
  END o[116]
  PIN o[117]
    DIRECTION OUTPUT ;
    USE SIGNAL ;
    PORT
      LAYER M5 ;
        RECT  11.904 0 11.928 0.084 ;
    END
  END o[117]
  PIN o[118]
    DIRECTION OUTPUT ;
    USE SIGNAL ;
    PORT
      LAYER M5 ;
        RECT  12 0 12.024 0.084 ;
    END
  END o[118]
  PIN o[119]
    DIRECTION OUTPUT ;
    USE SIGNAL ;
    PORT
      LAYER M5 ;
        RECT  12.096 0 12.12 0.084 ;
    END
  END o[119]
  PIN o[11]
    DIRECTION OUTPUT ;
    USE SIGNAL ;
    PORT
      LAYER M3 ;
        RECT  3.312 0 3.33 0.038 ;
    END
  END o[11]
  PIN o[120]
    DIRECTION OUTPUT ;
    USE SIGNAL ;
    PORT
      LAYER M5 ;
        RECT  12.144 0 12.168 0.084 ;
    END
  END o[120]
  PIN o[121]
    DIRECTION OUTPUT ;
    USE SIGNAL ;
    PORT
      LAYER M5 ;
        RECT  12.24 0 12.264 0.084 ;
    END
  END o[121]
  PIN o[122]
    DIRECTION OUTPUT ;
    USE SIGNAL ;
    PORT
      LAYER M5 ;
        RECT  12.336 0 12.36 0.084 ;
    END
  END o[122]
  PIN o[123]
    DIRECTION OUTPUT ;
    USE SIGNAL ;
    PORT
      LAYER M5 ;
        RECT  12.384 0 12.408 0.084 ;
    END
  END o[123]
  PIN o[124]
    DIRECTION OUTPUT ;
    USE SIGNAL ;
    PORT
      LAYER M5 ;
        RECT  12.48 0 12.504 0.084 ;
    END
  END o[124]
  PIN o[125]
    DIRECTION OUTPUT ;
    USE SIGNAL ;
    PORT
      LAYER M5 ;
        RECT  12.576 0 12.6 0.084 ;
    END
  END o[125]
  PIN o[126]
    DIRECTION OUTPUT ;
    USE SIGNAL ;
    PORT
      LAYER M5 ;
        RECT  12.624 0 12.648 0.084 ;
    END
  END o[126]
  PIN o[127]
    DIRECTION OUTPUT ;
    USE SIGNAL ;
    PORT
      LAYER M5 ;
        RECT  12.72 0 12.744 0.084 ;
    END
  END o[127]
  PIN o[128]
    DIRECTION OUTPUT ;
    USE SIGNAL ;
    PORT
      LAYER M3 ;
        RECT  12.816 0 12.834 0.038 ;
    END
  END o[128]
  PIN o[129]
    DIRECTION OUTPUT ;
    USE SIGNAL ;
    PORT
      LAYER M3 ;
        RECT  12.888 0 12.906 0.038 ;
    END
  END o[129]
  PIN o[12]
    DIRECTION OUTPUT ;
    USE SIGNAL ;
    PORT
      LAYER M3 ;
        RECT  3.42 0 3.438 0.038 ;
    END
  END o[12]
  PIN o[130]
    DIRECTION OUTPUT ;
    USE SIGNAL ;
    PORT
      LAYER M3 ;
        RECT  12.96 0 12.978 0.038 ;
    END
  END o[130]
  PIN o[131]
    DIRECTION OUTPUT ;
    USE SIGNAL ;
    PORT
      LAYER M3 ;
        RECT  13.068 0 13.086 0.038 ;
    END
  END o[131]
  PIN o[132]
    DIRECTION OUTPUT ;
    USE SIGNAL ;
    PORT
      LAYER M3 ;
        RECT  13.14 0 13.158 0.038 ;
    END
  END o[132]
  PIN o[133]
    DIRECTION OUTPUT ;
    USE SIGNAL ;
    PORT
      LAYER M3 ;
        RECT  13.212 0 13.23 0.038 ;
    END
  END o[133]
  PIN o[134]
    DIRECTION OUTPUT ;
    USE SIGNAL ;
    PORT
      LAYER M3 ;
        RECT  13.284 0 13.302 0.038 ;
    END
  END o[134]
  PIN o[135]
    DIRECTION OUTPUT ;
    USE SIGNAL ;
    PORT
      LAYER M3 ;
        RECT  13.392 0 13.41 0.038 ;
    END
  END o[135]
  PIN o[136]
    DIRECTION OUTPUT ;
    USE SIGNAL ;
    PORT
      LAYER M3 ;
        RECT  13.464 0 13.482 0.038 ;
    END
  END o[136]
  PIN o[137]
    DIRECTION OUTPUT ;
    USE SIGNAL ;
    PORT
      LAYER M3 ;
        RECT  13.536 0 13.554 0.038 ;
    END
  END o[137]
  PIN o[138]
    DIRECTION OUTPUT ;
    USE SIGNAL ;
    PORT
      LAYER M3 ;
        RECT  13.608 0 13.626 0.038 ;
    END
  END o[138]
  PIN o[139]
    DIRECTION OUTPUT ;
    USE SIGNAL ;
    PORT
      LAYER M3 ;
        RECT  13.716 0 13.734 0.038 ;
    END
  END o[139]
  PIN o[13]
    DIRECTION OUTPUT ;
    USE SIGNAL ;
    PORT
      LAYER M3 ;
        RECT  3.492 0 3.51 0.038 ;
    END
  END o[13]
  PIN o[140]
    DIRECTION OUTPUT ;
    USE SIGNAL ;
    PORT
      LAYER M3 ;
        RECT  13.788 0 13.806 0.038 ;
    END
  END o[140]
  PIN o[141]
    DIRECTION OUTPUT ;
    USE SIGNAL ;
    PORT
      LAYER M3 ;
        RECT  13.86 0 13.878 0.038 ;
    END
  END o[141]
  PIN o[142]
    DIRECTION OUTPUT ;
    USE SIGNAL ;
    PORT
      LAYER M3 ;
        RECT  13.932 0 13.95 0.038 ;
    END
  END o[142]
  PIN o[143]
    DIRECTION OUTPUT ;
    USE SIGNAL ;
    PORT
      LAYER M3 ;
        RECT  14.04 0 14.058 0.038 ;
    END
  END o[143]
  PIN o[144]
    DIRECTION OUTPUT ;
    USE SIGNAL ;
    PORT
      LAYER M3 ;
        RECT  14.112 0 14.13 0.038 ;
    END
  END o[144]
  PIN o[145]
    DIRECTION OUTPUT ;
    USE SIGNAL ;
    PORT
      LAYER M3 ;
        RECT  14.184 0 14.202 0.038 ;
    END
  END o[145]
  PIN o[146]
    DIRECTION OUTPUT ;
    USE SIGNAL ;
    PORT
      LAYER M3 ;
        RECT  14.256 0 14.274 0.038 ;
    END
  END o[146]
  PIN o[147]
    DIRECTION OUTPUT ;
    USE SIGNAL ;
    PORT
      LAYER M3 ;
        RECT  14.364 0 14.382 0.038 ;
    END
  END o[147]
  PIN o[148]
    DIRECTION OUTPUT ;
    USE SIGNAL ;
    PORT
      LAYER M3 ;
        RECT  14.436 0 14.454 0.038 ;
    END
  END o[148]
  PIN o[149]
    DIRECTION OUTPUT ;
    USE SIGNAL ;
    PORT
      LAYER M3 ;
        RECT  14.508 0 14.526 0.038 ;
    END
  END o[149]
  PIN o[14]
    DIRECTION OUTPUT ;
    USE SIGNAL ;
    PORT
      LAYER M3 ;
        RECT  3.564 0 3.582 0.038 ;
    END
  END o[14]
  PIN o[150]
    DIRECTION OUTPUT ;
    USE SIGNAL ;
    PORT
      LAYER M3 ;
        RECT  14.58 0 14.598 0.038 ;
    END
  END o[150]
  PIN o[151]
    DIRECTION OUTPUT ;
    USE SIGNAL ;
    PORT
      LAYER M3 ;
        RECT  14.688 0 14.706 0.038 ;
    END
  END o[151]
  PIN o[152]
    DIRECTION OUTPUT ;
    USE SIGNAL ;
    PORT
      LAYER M3 ;
        RECT  14.76 0 14.778 0.038 ;
    END
  END o[152]
  PIN o[153]
    DIRECTION OUTPUT ;
    USE SIGNAL ;
    PORT
      LAYER M3 ;
        RECT  14.832 0 14.85 0.038 ;
    END
  END o[153]
  PIN o[154]
    DIRECTION OUTPUT ;
    USE SIGNAL ;
    PORT
      LAYER M3 ;
        RECT  14.904 0 14.922 0.038 ;
    END
  END o[154]
  PIN o[155]
    DIRECTION OUTPUT ;
    USE SIGNAL ;
    PORT
      LAYER M3 ;
        RECT  15.012 0 15.03 0.038 ;
    END
  END o[155]
  PIN o[156]
    DIRECTION OUTPUT ;
    USE SIGNAL ;
    PORT
      LAYER M3 ;
        RECT  15.084 0 15.102 0.038 ;
    END
  END o[156]
  PIN o[157]
    DIRECTION OUTPUT ;
    USE SIGNAL ;
    PORT
      LAYER M3 ;
        RECT  15.156 0 15.174 0.038 ;
    END
  END o[157]
  PIN o[158]
    DIRECTION OUTPUT ;
    USE SIGNAL ;
    PORT
      LAYER M3 ;
        RECT  15.228 0 15.246 0.038 ;
    END
  END o[158]
  PIN o[159]
    DIRECTION OUTPUT ;
    USE SIGNAL ;
    PORT
      LAYER M3 ;
        RECT  15.336 0 15.354 0.038 ;
    END
  END o[159]
  PIN o[15]
    DIRECTION OUTPUT ;
    USE SIGNAL ;
    PORT
      LAYER M3 ;
        RECT  3.636 0 3.654 0.038 ;
    END
  END o[15]
  PIN o[160]
    DIRECTION OUTPUT ;
    USE SIGNAL ;
    PORT
      LAYER M5 ;
        RECT  15.408 0 15.432 0.084 ;
    END
  END o[160]
  PIN o[161]
    DIRECTION OUTPUT ;
    USE SIGNAL ;
    PORT
      LAYER M5 ;
        RECT  15.504 0 15.528 0.084 ;
    END
  END o[161]
  PIN o[162]
    DIRECTION OUTPUT ;
    USE SIGNAL ;
    PORT
      LAYER M5 ;
        RECT  15.552 0 15.576 0.084 ;
    END
  END o[162]
  PIN o[163]
    DIRECTION OUTPUT ;
    USE SIGNAL ;
    PORT
      LAYER M5 ;
        RECT  15.648 0 15.672 0.084 ;
    END
  END o[163]
  PIN o[164]
    DIRECTION OUTPUT ;
    USE SIGNAL ;
    PORT
      LAYER M5 ;
        RECT  15.744 0 15.768 0.084 ;
    END
  END o[164]
  PIN o[165]
    DIRECTION OUTPUT ;
    USE SIGNAL ;
    PORT
      LAYER M5 ;
        RECT  15.792 0 15.816 0.084 ;
    END
  END o[165]
  PIN o[166]
    DIRECTION OUTPUT ;
    USE SIGNAL ;
    PORT
      LAYER M5 ;
        RECT  15.888 0 15.912 0.084 ;
    END
  END o[166]
  PIN o[167]
    DIRECTION OUTPUT ;
    USE SIGNAL ;
    PORT
      LAYER M5 ;
        RECT  15.984 0 16.008 0.084 ;
    END
  END o[167]
  PIN o[168]
    DIRECTION OUTPUT ;
    USE SIGNAL ;
    PORT
      LAYER M5 ;
        RECT  16.032 0 16.056 0.084 ;
    END
  END o[168]
  PIN o[169]
    DIRECTION OUTPUT ;
    USE SIGNAL ;
    PORT
      LAYER M5 ;
        RECT  16.128 0 16.152 0.084 ;
    END
  END o[169]
  PIN o[16]
    DIRECTION OUTPUT ;
    USE SIGNAL ;
    PORT
      LAYER M3 ;
        RECT  3.744 0 3.762 0.038 ;
    END
  END o[16]
  PIN o[170]
    DIRECTION OUTPUT ;
    USE SIGNAL ;
    PORT
      LAYER M5 ;
        RECT  16.224 0 16.248 0.084 ;
    END
  END o[170]
  PIN o[171]
    DIRECTION OUTPUT ;
    USE SIGNAL ;
    PORT
      LAYER M5 ;
        RECT  16.272 0 16.296 0.084 ;
    END
  END o[171]
  PIN o[172]
    DIRECTION OUTPUT ;
    USE SIGNAL ;
    PORT
      LAYER M5 ;
        RECT  16.368 0 16.392 0.084 ;
    END
  END o[172]
  PIN o[173]
    DIRECTION OUTPUT ;
    USE SIGNAL ;
    PORT
      LAYER M5 ;
        RECT  16.464 0 16.488 0.084 ;
    END
  END o[173]
  PIN o[174]
    DIRECTION OUTPUT ;
    USE SIGNAL ;
    PORT
      LAYER M5 ;
        RECT  16.56 0 16.584 0.084 ;
    END
  END o[174]
  PIN o[175]
    DIRECTION OUTPUT ;
    USE SIGNAL ;
    PORT
      LAYER M5 ;
        RECT  16.608 0 16.632 0.084 ;
    END
  END o[175]
  PIN o[176]
    DIRECTION OUTPUT ;
    USE SIGNAL ;
    PORT
      LAYER M5 ;
        RECT  16.704 0 16.728 0.084 ;
    END
  END o[176]
  PIN o[177]
    DIRECTION OUTPUT ;
    USE SIGNAL ;
    PORT
      LAYER M5 ;
        RECT  16.8 0 16.824 0.084 ;
    END
  END o[177]
  PIN o[178]
    DIRECTION OUTPUT ;
    USE SIGNAL ;
    PORT
      LAYER M5 ;
        RECT  16.848 0 16.872 0.084 ;
    END
  END o[178]
  PIN o[179]
    DIRECTION OUTPUT ;
    USE SIGNAL ;
    PORT
      LAYER M5 ;
        RECT  16.944 0 16.968 0.084 ;
    END
  END o[179]
  PIN o[17]
    DIRECTION OUTPUT ;
    USE SIGNAL ;
    PORT
      LAYER M3 ;
        RECT  3.816 0 3.834 0.038 ;
    END
  END o[17]
  PIN o[180]
    DIRECTION OUTPUT ;
    USE SIGNAL ;
    PORT
      LAYER M5 ;
        RECT  17.04 0 17.064 0.084 ;
    END
  END o[180]
  PIN o[181]
    DIRECTION OUTPUT ;
    USE SIGNAL ;
    PORT
      LAYER M5 ;
        RECT  17.088 0 17.112 0.084 ;
    END
  END o[181]
  PIN o[182]
    DIRECTION OUTPUT ;
    USE SIGNAL ;
    PORT
      LAYER M5 ;
        RECT  17.184 0 17.208 0.084 ;
    END
  END o[182]
  PIN o[183]
    DIRECTION OUTPUT ;
    USE SIGNAL ;
    PORT
      LAYER M5 ;
        RECT  17.28 0 17.304 0.084 ;
    END
  END o[183]
  PIN o[184]
    DIRECTION OUTPUT ;
    USE SIGNAL ;
    PORT
      LAYER M5 ;
        RECT  17.328 0 17.352 0.084 ;
    END
  END o[184]
  PIN o[185]
    DIRECTION OUTPUT ;
    USE SIGNAL ;
    PORT
      LAYER M5 ;
        RECT  17.424 0 17.448 0.084 ;
    END
  END o[185]
  PIN o[186]
    DIRECTION OUTPUT ;
    USE SIGNAL ;
    PORT
      LAYER M5 ;
        RECT  17.52 0 17.544 0.084 ;
    END
  END o[186]
  PIN o[187]
    DIRECTION OUTPUT ;
    USE SIGNAL ;
    PORT
      LAYER M5 ;
        RECT  17.568 0 17.592 0.084 ;
    END
  END o[187]
  PIN o[188]
    DIRECTION OUTPUT ;
    USE SIGNAL ;
    PORT
      LAYER M5 ;
        RECT  17.664 0 17.688 0.084 ;
    END
  END o[188]
  PIN o[189]
    DIRECTION OUTPUT ;
    USE SIGNAL ;
    PORT
      LAYER M5 ;
        RECT  17.76 0 17.784 0.084 ;
    END
  END o[189]
  PIN o[18]
    DIRECTION OUTPUT ;
    USE SIGNAL ;
    PORT
      LAYER M3 ;
        RECT  3.888 0 3.906 0.038 ;
    END
  END o[18]
  PIN o[190]
    DIRECTION OUTPUT ;
    USE SIGNAL ;
    PORT
      LAYER M5 ;
        RECT  17.856 0 17.88 0.084 ;
    END
  END o[190]
  PIN o[191]
    DIRECTION OUTPUT ;
    USE SIGNAL ;
    PORT
      LAYER M5 ;
        RECT  17.904 0 17.928 0.084 ;
    END
  END o[191]
  PIN o[192]
    DIRECTION OUTPUT ;
    USE SIGNAL ;
    PORT
      LAYER M3 ;
        RECT  18 0 18.018 0.038 ;
    END
  END o[192]
  PIN o[193]
    DIRECTION OUTPUT ;
    USE SIGNAL ;
    PORT
      LAYER M3 ;
        RECT  18.072 0 18.09 0.038 ;
    END
  END o[193]
  PIN o[194]
    DIRECTION OUTPUT ;
    USE SIGNAL ;
    PORT
      LAYER M3 ;
        RECT  18.144 0 18.162 0.038 ;
    END
  END o[194]
  PIN o[195]
    DIRECTION OUTPUT ;
    USE SIGNAL ;
    PORT
      LAYER M3 ;
        RECT  18.252 0 18.27 0.038 ;
    END
  END o[195]
  PIN o[196]
    DIRECTION OUTPUT ;
    USE SIGNAL ;
    PORT
      LAYER M3 ;
        RECT  18.324 0 18.342 0.038 ;
    END
  END o[196]
  PIN o[197]
    DIRECTION OUTPUT ;
    USE SIGNAL ;
    PORT
      LAYER M3 ;
        RECT  18.396 0 18.414 0.038 ;
    END
  END o[197]
  PIN o[198]
    DIRECTION OUTPUT ;
    USE SIGNAL ;
    PORT
      LAYER M3 ;
        RECT  18.504 0 18.522 0.038 ;
    END
  END o[198]
  PIN o[199]
    DIRECTION OUTPUT ;
    USE SIGNAL ;
    PORT
      LAYER M3 ;
        RECT  18.576 0 18.594 0.038 ;
    END
  END o[199]
  PIN o[19]
    DIRECTION OUTPUT ;
    USE SIGNAL ;
    PORT
      LAYER M3 ;
        RECT  3.96 0 3.978 0.038 ;
    END
  END o[19]
  PIN o[1]
    DIRECTION OUTPUT ;
    USE SIGNAL ;
    PORT
      LAYER M3 ;
        RECT  2.52 0 2.538 0.038 ;
    END
  END o[1]
  PIN o[200]
    DIRECTION OUTPUT ;
    USE SIGNAL ;
    PORT
      LAYER M3 ;
        RECT  18.648 0 18.666 0.038 ;
    END
  END o[200]
  PIN o[201]
    DIRECTION OUTPUT ;
    USE SIGNAL ;
    PORT
      LAYER M3 ;
        RECT  18.72 0 18.738 0.038 ;
    END
  END o[201]
  PIN o[202]
    DIRECTION OUTPUT ;
    USE SIGNAL ;
    PORT
      LAYER M3 ;
        RECT  18.828 0 18.846 0.038 ;
    END
  END o[202]
  PIN o[203]
    DIRECTION OUTPUT ;
    USE SIGNAL ;
    PORT
      LAYER M3 ;
        RECT  18.9 0 18.918 0.038 ;
    END
  END o[203]
  PIN o[204]
    DIRECTION OUTPUT ;
    USE SIGNAL ;
    PORT
      LAYER M3 ;
        RECT  18.972 0 18.99 0.038 ;
    END
  END o[204]
  PIN o[205]
    DIRECTION OUTPUT ;
    USE SIGNAL ;
    PORT
      LAYER M3 ;
        RECT  19.044 0 19.062 0.038 ;
    END
  END o[205]
  PIN o[206]
    DIRECTION OUTPUT ;
    USE SIGNAL ;
    PORT
      LAYER M3 ;
        RECT  19.152 0 19.17 0.038 ;
    END
  END o[206]
  PIN o[207]
    DIRECTION OUTPUT ;
    USE SIGNAL ;
    PORT
      LAYER M3 ;
        RECT  19.224 0 19.242 0.038 ;
    END
  END o[207]
  PIN o[208]
    DIRECTION OUTPUT ;
    USE SIGNAL ;
    PORT
      LAYER M3 ;
        RECT  19.296 0 19.314 0.038 ;
    END
  END o[208]
  PIN o[209]
    DIRECTION OUTPUT ;
    USE SIGNAL ;
    PORT
      LAYER M3 ;
        RECT  19.368 0 19.386 0.038 ;
    END
  END o[209]
  PIN o[20]
    DIRECTION OUTPUT ;
    USE SIGNAL ;
    PORT
      LAYER M3 ;
        RECT  4.068 0 4.086 0.038 ;
    END
  END o[20]
  PIN o[210]
    DIRECTION OUTPUT ;
    USE SIGNAL ;
    PORT
      LAYER M3 ;
        RECT  19.476 0 19.494 0.038 ;
    END
  END o[210]
  PIN o[211]
    DIRECTION OUTPUT ;
    USE SIGNAL ;
    PORT
      LAYER M3 ;
        RECT  19.548 0 19.566 0.038 ;
    END
  END o[211]
  PIN o[212]
    DIRECTION OUTPUT ;
    USE SIGNAL ;
    PORT
      LAYER M3 ;
        RECT  19.62 0 19.638 0.038 ;
    END
  END o[212]
  PIN o[213]
    DIRECTION OUTPUT ;
    USE SIGNAL ;
    PORT
      LAYER M3 ;
        RECT  19.692 0 19.71 0.038 ;
    END
  END o[213]
  PIN o[214]
    DIRECTION OUTPUT ;
    USE SIGNAL ;
    PORT
      LAYER M3 ;
        RECT  19.8 0 19.818 0.038 ;
    END
  END o[214]
  PIN o[215]
    DIRECTION OUTPUT ;
    USE SIGNAL ;
    PORT
      LAYER M3 ;
        RECT  19.872 0 19.89 0.038 ;
    END
  END o[215]
  PIN o[216]
    DIRECTION OUTPUT ;
    USE SIGNAL ;
    PORT
      LAYER M3 ;
        RECT  19.944 0 19.962 0.038 ;
    END
  END o[216]
  PIN o[217]
    DIRECTION OUTPUT ;
    USE SIGNAL ;
    PORT
      LAYER M3 ;
        RECT  20.016 0 20.034 0.038 ;
    END
  END o[217]
  PIN o[218]
    DIRECTION OUTPUT ;
    USE SIGNAL ;
    PORT
      LAYER M3 ;
        RECT  20.124 0 20.142 0.038 ;
    END
  END o[218]
  PIN o[219]
    DIRECTION OUTPUT ;
    USE SIGNAL ;
    PORT
      LAYER M3 ;
        RECT  20.196 0 20.214 0.038 ;
    END
  END o[219]
  PIN o[21]
    DIRECTION OUTPUT ;
    USE SIGNAL ;
    PORT
      LAYER M3 ;
        RECT  4.14 0 4.158 0.038 ;
    END
  END o[21]
  PIN o[220]
    DIRECTION OUTPUT ;
    USE SIGNAL ;
    PORT
      LAYER M3 ;
        RECT  20.268 0 20.286 0.038 ;
    END
  END o[220]
  PIN o[221]
    DIRECTION OUTPUT ;
    USE SIGNAL ;
    PORT
      LAYER M3 ;
        RECT  20.34 0 20.358 0.038 ;
    END
  END o[221]
  PIN o[222]
    DIRECTION OUTPUT ;
    USE SIGNAL ;
    PORT
      LAYER M3 ;
        RECT  20.448 0 20.466 0.038 ;
    END
  END o[222]
  PIN o[223]
    DIRECTION OUTPUT ;
    USE SIGNAL ;
    PORT
      LAYER M3 ;
        RECT  20.52 0 20.538 0.038 ;
    END
  END o[223]
  PIN o[224]
    DIRECTION OUTPUT ;
    USE SIGNAL ;
    PORT
      LAYER M5 ;
        RECT  20.592 0 20.616 0.084 ;
    END
  END o[224]
  PIN o[225]
    DIRECTION OUTPUT ;
    USE SIGNAL ;
    PORT
      LAYER M5 ;
        RECT  20.688 0 20.712 0.084 ;
    END
  END o[225]
  PIN o[226]
    DIRECTION OUTPUT ;
    USE SIGNAL ;
    PORT
      LAYER M5 ;
        RECT  20.736 0 20.76 0.084 ;
    END
  END o[226]
  PIN o[227]
    DIRECTION OUTPUT ;
    USE SIGNAL ;
    PORT
      LAYER M5 ;
        RECT  20.832 0 20.856 0.084 ;
    END
  END o[227]
  PIN o[228]
    DIRECTION OUTPUT ;
    USE SIGNAL ;
    PORT
      LAYER M5 ;
        RECT  20.928 0 20.952 0.084 ;
    END
  END o[228]
  PIN o[229]
    DIRECTION OUTPUT ;
    USE SIGNAL ;
    PORT
      LAYER M5 ;
        RECT  20.976 0 21 0.084 ;
    END
  END o[229]
  PIN o[22]
    DIRECTION OUTPUT ;
    USE SIGNAL ;
    PORT
      LAYER M3 ;
        RECT  4.212 0 4.23 0.038 ;
    END
  END o[22]
  PIN o[230]
    DIRECTION OUTPUT ;
    USE SIGNAL ;
    PORT
      LAYER M5 ;
        RECT  21.072 0 21.096 0.084 ;
    END
  END o[230]
  PIN o[231]
    DIRECTION OUTPUT ;
    USE SIGNAL ;
    PORT
      LAYER M5 ;
        RECT  21.168 0 21.192 0.084 ;
    END
  END o[231]
  PIN o[232]
    DIRECTION OUTPUT ;
    USE SIGNAL ;
    PORT
      LAYER M5 ;
        RECT  21.216 0 21.24 0.084 ;
    END
  END o[232]
  PIN o[233]
    DIRECTION OUTPUT ;
    USE SIGNAL ;
    PORT
      LAYER M5 ;
        RECT  21.312 0 21.336 0.084 ;
    END
  END o[233]
  PIN o[234]
    DIRECTION OUTPUT ;
    USE SIGNAL ;
    PORT
      LAYER M5 ;
        RECT  21.408 0 21.432 0.084 ;
    END
  END o[234]
  PIN o[235]
    DIRECTION OUTPUT ;
    USE SIGNAL ;
    PORT
      LAYER M5 ;
        RECT  21.504 0 21.528 0.084 ;
    END
  END o[235]
  PIN o[236]
    DIRECTION OUTPUT ;
    USE SIGNAL ;
    PORT
      LAYER M5 ;
        RECT  21.552 0 21.576 0.084 ;
    END
  END o[236]
  PIN o[237]
    DIRECTION OUTPUT ;
    USE SIGNAL ;
    PORT
      LAYER M5 ;
        RECT  21.648 0 21.672 0.084 ;
    END
  END o[237]
  PIN o[238]
    DIRECTION OUTPUT ;
    USE SIGNAL ;
    PORT
      LAYER M5 ;
        RECT  21.744 0 21.768 0.084 ;
    END
  END o[238]
  PIN o[239]
    DIRECTION OUTPUT ;
    USE SIGNAL ;
    PORT
      LAYER M5 ;
        RECT  21.792 0 21.816 0.084 ;
    END
  END o[239]
  PIN o[23]
    DIRECTION OUTPUT ;
    USE SIGNAL ;
    PORT
      LAYER M3 ;
        RECT  4.284 0 4.302 0.038 ;
    END
  END o[23]
  PIN o[240]
    DIRECTION OUTPUT ;
    USE SIGNAL ;
    PORT
      LAYER M5 ;
        RECT  21.888 0 21.912 0.084 ;
    END
  END o[240]
  PIN o[241]
    DIRECTION OUTPUT ;
    USE SIGNAL ;
    PORT
      LAYER M5 ;
        RECT  21.984 0 22.008 0.084 ;
    END
  END o[241]
  PIN o[242]
    DIRECTION OUTPUT ;
    USE SIGNAL ;
    PORT
      LAYER M5 ;
        RECT  22.032 0 22.056 0.084 ;
    END
  END o[242]
  PIN o[243]
    DIRECTION OUTPUT ;
    USE SIGNAL ;
    PORT
      LAYER M5 ;
        RECT  22.128 0 22.152 0.084 ;
    END
  END o[243]
  PIN o[244]
    DIRECTION OUTPUT ;
    USE SIGNAL ;
    PORT
      LAYER M5 ;
        RECT  22.224 0 22.248 0.084 ;
    END
  END o[244]
  PIN o[245]
    DIRECTION OUTPUT ;
    USE SIGNAL ;
    PORT
      LAYER M5 ;
        RECT  22.272 0 22.296 0.084 ;
    END
  END o[245]
  PIN o[246]
    DIRECTION OUTPUT ;
    USE SIGNAL ;
    PORT
      LAYER M5 ;
        RECT  22.368 0 22.392 0.084 ;
    END
  END o[246]
  PIN o[247]
    DIRECTION OUTPUT ;
    USE SIGNAL ;
    PORT
      LAYER M5 ;
        RECT  22.464 0 22.488 0.084 ;
    END
  END o[247]
  PIN o[248]
    DIRECTION OUTPUT ;
    USE SIGNAL ;
    PORT
      LAYER M5 ;
        RECT  22.56 0 22.584 0.084 ;
    END
  END o[248]
  PIN o[249]
    DIRECTION OUTPUT ;
    USE SIGNAL ;
    PORT
      LAYER M5 ;
        RECT  22.608 0 22.632 0.084 ;
    END
  END o[249]
  PIN o[24]
    DIRECTION OUTPUT ;
    USE SIGNAL ;
    PORT
      LAYER M3 ;
        RECT  4.392 0 4.41 0.038 ;
    END
  END o[24]
  PIN o[250]
    DIRECTION OUTPUT ;
    USE SIGNAL ;
    PORT
      LAYER M5 ;
        RECT  22.704 0 22.728 0.084 ;
    END
  END o[250]
  PIN o[251]
    DIRECTION OUTPUT ;
    USE SIGNAL ;
    PORT
      LAYER M5 ;
        RECT  22.8 0 22.824 0.084 ;
    END
  END o[251]
  PIN o[252]
    DIRECTION OUTPUT ;
    USE SIGNAL ;
    PORT
      LAYER M5 ;
        RECT  22.848 0 22.872 0.084 ;
    END
  END o[252]
  PIN o[253]
    DIRECTION OUTPUT ;
    USE SIGNAL ;
    PORT
      LAYER M5 ;
        RECT  22.944 0 22.968 0.084 ;
    END
  END o[253]
  PIN o[254]
    DIRECTION OUTPUT ;
    USE SIGNAL ;
    PORT
      LAYER M5 ;
        RECT  23.04 0 23.064 0.084 ;
    END
  END o[254]
  PIN o[255]
    DIRECTION OUTPUT ;
    USE SIGNAL ;
    PORT
      LAYER M5 ;
        RECT  23.088 0 23.112 0.084 ;
    END
  END o[255]
  PIN o[256]
    DIRECTION OUTPUT ;
    USE SIGNAL ;
    PORT
      LAYER M3 ;
        RECT  23.184 0 23.202 0.038 ;
    END
  END o[256]
  PIN o[257]
    DIRECTION OUTPUT ;
    USE SIGNAL ;
    PORT
      LAYER M3 ;
        RECT  23.256 0 23.274 0.038 ;
    END
  END o[257]
  PIN o[258]
    DIRECTION OUTPUT ;
    USE SIGNAL ;
    PORT
      LAYER M3 ;
        RECT  23.364 0 23.382 0.038 ;
    END
  END o[258]
  PIN o[259]
    DIRECTION OUTPUT ;
    USE SIGNAL ;
    PORT
      LAYER M3 ;
        RECT  23.436 0 23.454 0.038 ;
    END
  END o[259]
  PIN o[25]
    DIRECTION OUTPUT ;
    USE SIGNAL ;
    PORT
      LAYER M3 ;
        RECT  4.464 0 4.482 0.038 ;
    END
  END o[25]
  PIN o[260]
    DIRECTION OUTPUT ;
    USE SIGNAL ;
    PORT
      LAYER M3 ;
        RECT  23.508 0 23.526 0.038 ;
    END
  END o[260]
  PIN o[261]
    DIRECTION OUTPUT ;
    USE SIGNAL ;
    PORT
      LAYER M3 ;
        RECT  23.58 0 23.598 0.038 ;
    END
  END o[261]
  PIN o[262]
    DIRECTION OUTPUT ;
    USE SIGNAL ;
    PORT
      LAYER M3 ;
        RECT  23.688 0 23.706 0.038 ;
    END
  END o[262]
  PIN o[263]
    DIRECTION OUTPUT ;
    USE SIGNAL ;
    PORT
      LAYER M3 ;
        RECT  23.76 0 23.778 0.038 ;
    END
  END o[263]
  PIN o[264]
    DIRECTION OUTPUT ;
    USE SIGNAL ;
    PORT
      LAYER M3 ;
        RECT  23.832 0 23.85 0.038 ;
    END
  END o[264]
  PIN o[265]
    DIRECTION OUTPUT ;
    USE SIGNAL ;
    PORT
      LAYER M3 ;
        RECT  23.904 0 23.922 0.038 ;
    END
  END o[265]
  PIN o[266]
    DIRECTION OUTPUT ;
    USE SIGNAL ;
    PORT
      LAYER M3 ;
        RECT  24.012 0 24.03 0.038 ;
    END
  END o[266]
  PIN o[267]
    DIRECTION OUTPUT ;
    USE SIGNAL ;
    PORT
      LAYER M3 ;
        RECT  24.084 0 24.102 0.038 ;
    END
  END o[267]
  PIN o[268]
    DIRECTION OUTPUT ;
    USE SIGNAL ;
    PORT
      LAYER M3 ;
        RECT  24.156 0 24.174 0.038 ;
    END
  END o[268]
  PIN o[269]
    DIRECTION OUTPUT ;
    USE SIGNAL ;
    PORT
      LAYER M3 ;
        RECT  24.228 0 24.246 0.038 ;
    END
  END o[269]
  PIN o[26]
    DIRECTION OUTPUT ;
    USE SIGNAL ;
    PORT
      LAYER M3 ;
        RECT  4.536 0 4.554 0.038 ;
    END
  END o[26]
  PIN o[270]
    DIRECTION OUTPUT ;
    USE SIGNAL ;
    PORT
      LAYER M3 ;
        RECT  24.336 0 24.354 0.038 ;
    END
  END o[270]
  PIN o[271]
    DIRECTION OUTPUT ;
    USE SIGNAL ;
    PORT
      LAYER M3 ;
        RECT  24.408 0 24.426 0.038 ;
    END
  END o[271]
  PIN o[272]
    DIRECTION OUTPUT ;
    USE SIGNAL ;
    PORT
      LAYER M3 ;
        RECT  24.48 0 24.498 0.038 ;
    END
  END o[272]
  PIN o[273]
    DIRECTION OUTPUT ;
    USE SIGNAL ;
    PORT
      LAYER M3 ;
        RECT  24.552 0 24.57 0.038 ;
    END
  END o[273]
  PIN o[274]
    DIRECTION OUTPUT ;
    USE SIGNAL ;
    PORT
      LAYER M3 ;
        RECT  24.66 0 24.678 0.038 ;
    END
  END o[274]
  PIN o[275]
    DIRECTION OUTPUT ;
    USE SIGNAL ;
    PORT
      LAYER M3 ;
        RECT  24.732 0 24.75 0.038 ;
    END
  END o[275]
  PIN o[276]
    DIRECTION OUTPUT ;
    USE SIGNAL ;
    PORT
      LAYER M3 ;
        RECT  24.804 0 24.822 0.038 ;
    END
  END o[276]
  PIN o[277]
    DIRECTION OUTPUT ;
    USE SIGNAL ;
    PORT
      LAYER M3 ;
        RECT  24.876 0 24.894 0.038 ;
    END
  END o[277]
  PIN o[278]
    DIRECTION OUTPUT ;
    USE SIGNAL ;
    PORT
      LAYER M3 ;
        RECT  24.984 0 25.002 0.038 ;
    END
  END o[278]
  PIN o[279]
    DIRECTION OUTPUT ;
    USE SIGNAL ;
    PORT
      LAYER M3 ;
        RECT  25.056 0 25.074 0.038 ;
    END
  END o[279]
  PIN o[27]
    DIRECTION OUTPUT ;
    USE SIGNAL ;
    PORT
      LAYER M3 ;
        RECT  4.608 0 4.626 0.038 ;
    END
  END o[27]
  PIN o[280]
    DIRECTION OUTPUT ;
    USE SIGNAL ;
    PORT
      LAYER M3 ;
        RECT  25.128 0 25.146 0.038 ;
    END
  END o[280]
  PIN o[281]
    DIRECTION OUTPUT ;
    USE SIGNAL ;
    PORT
      LAYER M3 ;
        RECT  25.2 0 25.218 0.038 ;
    END
  END o[281]
  PIN o[282]
    DIRECTION OUTPUT ;
    USE SIGNAL ;
    PORT
      LAYER M3 ;
        RECT  25.308 0 25.326 0.038 ;
    END
  END o[282]
  PIN o[283]
    DIRECTION OUTPUT ;
    USE SIGNAL ;
    PORT
      LAYER M3 ;
        RECT  25.38 0 25.398 0.038 ;
    END
  END o[283]
  PIN o[284]
    DIRECTION OUTPUT ;
    USE SIGNAL ;
    PORT
      LAYER M3 ;
        RECT  25.452 0 25.47 0.038 ;
    END
  END o[284]
  PIN o[285]
    DIRECTION OUTPUT ;
    USE SIGNAL ;
    PORT
      LAYER M3 ;
        RECT  25.524 0 25.542 0.038 ;
    END
  END o[285]
  PIN o[286]
    DIRECTION OUTPUT ;
    USE SIGNAL ;
    PORT
      LAYER M3 ;
        RECT  25.632 0 25.65 0.038 ;
    END
  END o[286]
  PIN o[287]
    DIRECTION OUTPUT ;
    USE SIGNAL ;
    PORT
      LAYER M3 ;
        RECT  25.704 0 25.722 0.038 ;
    END
  END o[287]
  PIN o[288]
    DIRECTION OUTPUT ;
    USE SIGNAL ;
    PORT
      LAYER M5 ;
        RECT  25.776 0 25.8 0.084 ;
    END
  END o[288]
  PIN o[289]
    DIRECTION OUTPUT ;
    USE SIGNAL ;
    PORT
      LAYER M5 ;
        RECT  25.872 0 25.896 0.084 ;
    END
  END o[289]
  PIN o[28]
    DIRECTION OUTPUT ;
    USE SIGNAL ;
    PORT
      LAYER M3 ;
        RECT  4.716 0 4.734 0.038 ;
    END
  END o[28]
  PIN o[290]
    DIRECTION OUTPUT ;
    USE SIGNAL ;
    PORT
      LAYER M5 ;
        RECT  25.92 0 25.944 0.084 ;
    END
  END o[290]
  PIN o[291]
    DIRECTION OUTPUT ;
    USE SIGNAL ;
    PORT
      LAYER M5 ;
        RECT  26.016 0 26.04 0.084 ;
    END
  END o[291]
  PIN o[292]
    DIRECTION OUTPUT ;
    USE SIGNAL ;
    PORT
      LAYER M5 ;
        RECT  26.112 0 26.136 0.084 ;
    END
  END o[292]
  PIN o[293]
    DIRECTION OUTPUT ;
    USE SIGNAL ;
    PORT
      LAYER M5 ;
        RECT  26.208 0 26.232 0.084 ;
    END
  END o[293]
  PIN o[294]
    DIRECTION OUTPUT ;
    USE SIGNAL ;
    PORT
      LAYER M5 ;
        RECT  26.256 0 26.28 0.084 ;
    END
  END o[294]
  PIN o[295]
    DIRECTION OUTPUT ;
    USE SIGNAL ;
    PORT
      LAYER M5 ;
        RECT  26.352 0 26.376 0.084 ;
    END
  END o[295]
  PIN o[296]
    DIRECTION OUTPUT ;
    USE SIGNAL ;
    PORT
      LAYER M5 ;
        RECT  26.448 0 26.472 0.084 ;
    END
  END o[296]
  PIN o[297]
    DIRECTION OUTPUT ;
    USE SIGNAL ;
    PORT
      LAYER M5 ;
        RECT  26.496 0 26.52 0.084 ;
    END
  END o[297]
  PIN o[298]
    DIRECTION OUTPUT ;
    USE SIGNAL ;
    PORT
      LAYER M5 ;
        RECT  26.592 0 26.616 0.084 ;
    END
  END o[298]
  PIN o[299]
    DIRECTION OUTPUT ;
    USE SIGNAL ;
    PORT
      LAYER M5 ;
        RECT  26.688 0 26.712 0.084 ;
    END
  END o[299]
  PIN o[29]
    DIRECTION OUTPUT ;
    USE SIGNAL ;
    PORT
      LAYER M3 ;
        RECT  4.788 0 4.806 0.038 ;
    END
  END o[29]
  PIN o[2]
    DIRECTION OUTPUT ;
    USE SIGNAL ;
    PORT
      LAYER M3 ;
        RECT  2.592 0 2.61 0.038 ;
    END
  END o[2]
  PIN o[300]
    DIRECTION OUTPUT ;
    USE SIGNAL ;
    PORT
      LAYER M5 ;
        RECT  26.736 0 26.76 0.084 ;
    END
  END o[300]
  PIN o[301]
    DIRECTION OUTPUT ;
    USE SIGNAL ;
    PORT
      LAYER M5 ;
        RECT  26.832 0 26.856 0.084 ;
    END
  END o[301]
  PIN o[302]
    DIRECTION OUTPUT ;
    USE SIGNAL ;
    PORT
      LAYER M5 ;
        RECT  26.928 0 26.952 0.084 ;
    END
  END o[302]
  PIN o[303]
    DIRECTION OUTPUT ;
    USE SIGNAL ;
    PORT
      LAYER M5 ;
        RECT  26.976 0 27 0.084 ;
    END
  END o[303]
  PIN o[304]
    DIRECTION OUTPUT ;
    USE SIGNAL ;
    PORT
      LAYER M5 ;
        RECT  27.072 0 27.096 0.084 ;
    END
  END o[304]
  PIN o[305]
    DIRECTION OUTPUT ;
    USE SIGNAL ;
    PORT
      LAYER M5 ;
        RECT  27.168 0 27.192 0.084 ;
    END
  END o[305]
  PIN o[306]
    DIRECTION OUTPUT ;
    USE SIGNAL ;
    PORT
      LAYER M5 ;
        RECT  27.216 0 27.24 0.084 ;
    END
  END o[306]
  PIN o[307]
    DIRECTION OUTPUT ;
    USE SIGNAL ;
    PORT
      LAYER M5 ;
        RECT  27.312 0 27.336 0.084 ;
    END
  END o[307]
  PIN o[308]
    DIRECTION OUTPUT ;
    USE SIGNAL ;
    PORT
      LAYER M5 ;
        RECT  27.408 0 27.432 0.084 ;
    END
  END o[308]
  PIN o[309]
    DIRECTION OUTPUT ;
    USE SIGNAL ;
    PORT
      LAYER M5 ;
        RECT  27.504 0 27.528 0.084 ;
    END
  END o[309]
  PIN o[30]
    DIRECTION OUTPUT ;
    USE SIGNAL ;
    PORT
      LAYER M3 ;
        RECT  4.86 0 4.878 0.038 ;
    END
  END o[30]
  PIN o[310]
    DIRECTION OUTPUT ;
    USE SIGNAL ;
    PORT
      LAYER M5 ;
        RECT  27.552 0 27.576 0.084 ;
    END
  END o[310]
  PIN o[311]
    DIRECTION OUTPUT ;
    USE SIGNAL ;
    PORT
      LAYER M5 ;
        RECT  27.648 0 27.672 0.084 ;
    END
  END o[311]
  PIN o[312]
    DIRECTION OUTPUT ;
    USE SIGNAL ;
    PORT
      LAYER M5 ;
        RECT  27.744 0 27.768 0.084 ;
    END
  END o[312]
  PIN o[313]
    DIRECTION OUTPUT ;
    USE SIGNAL ;
    PORT
      LAYER M5 ;
        RECT  27.792 0 27.816 0.084 ;
    END
  END o[313]
  PIN o[314]
    DIRECTION OUTPUT ;
    USE SIGNAL ;
    PORT
      LAYER M5 ;
        RECT  27.888 0 27.912 0.084 ;
    END
  END o[314]
  PIN o[315]
    DIRECTION OUTPUT ;
    USE SIGNAL ;
    PORT
      LAYER M5 ;
        RECT  27.984 0 28.008 0.084 ;
    END
  END o[315]
  PIN o[316]
    DIRECTION OUTPUT ;
    USE SIGNAL ;
    PORT
      LAYER M5 ;
        RECT  28.032 0 28.056 0.084 ;
    END
  END o[316]
  PIN o[317]
    DIRECTION OUTPUT ;
    USE SIGNAL ;
    PORT
      LAYER M5 ;
        RECT  28.128 0 28.152 0.084 ;
    END
  END o[317]
  PIN o[318]
    DIRECTION OUTPUT ;
    USE SIGNAL ;
    PORT
      LAYER M5 ;
        RECT  28.224 0 28.248 0.084 ;
    END
  END o[318]
  PIN o[319]
    DIRECTION OUTPUT ;
    USE SIGNAL ;
    PORT
      LAYER M5 ;
        RECT  28.272 0 28.296 0.084 ;
    END
  END o[319]
  PIN o[31]
    DIRECTION OUTPUT ;
    USE SIGNAL ;
    PORT
      LAYER M3 ;
        RECT  4.932 0 4.95 0.038 ;
    END
  END o[31]
  PIN o[320]
    DIRECTION OUTPUT ;
    USE SIGNAL ;
    PORT
      LAYER M3 ;
        RECT  28.368 0 28.386 0.038 ;
    END
  END o[320]
  PIN o[321]
    DIRECTION OUTPUT ;
    USE SIGNAL ;
    PORT
      LAYER M3 ;
        RECT  28.476 0 28.494 0.038 ;
    END
  END o[321]
  PIN o[322]
    DIRECTION OUTPUT ;
    USE SIGNAL ;
    PORT
      LAYER M3 ;
        RECT  28.548 0 28.566 0.038 ;
    END
  END o[322]
  PIN o[323]
    DIRECTION OUTPUT ;
    USE SIGNAL ;
    PORT
      LAYER M3 ;
        RECT  28.62 0 28.638 0.038 ;
    END
  END o[323]
  PIN o[324]
    DIRECTION OUTPUT ;
    USE SIGNAL ;
    PORT
      LAYER M3 ;
        RECT  28.692 0 28.71 0.038 ;
    END
  END o[324]
  PIN o[325]
    DIRECTION OUTPUT ;
    USE SIGNAL ;
    PORT
      LAYER M3 ;
        RECT  28.8 0 28.818 0.038 ;
    END
  END o[325]
  PIN o[326]
    DIRECTION OUTPUT ;
    USE SIGNAL ;
    PORT
      LAYER M3 ;
        RECT  28.872 0 28.89 0.038 ;
    END
  END o[326]
  PIN o[327]
    DIRECTION OUTPUT ;
    USE SIGNAL ;
    PORT
      LAYER M3 ;
        RECT  28.944 0 28.962 0.038 ;
    END
  END o[327]
  PIN o[328]
    DIRECTION OUTPUT ;
    USE SIGNAL ;
    PORT
      LAYER M3 ;
        RECT  29.016 0 29.034 0.038 ;
    END
  END o[328]
  PIN o[329]
    DIRECTION OUTPUT ;
    USE SIGNAL ;
    PORT
      LAYER M3 ;
        RECT  29.124 0 29.142 0.038 ;
    END
  END o[329]
  PIN o[32]
    DIRECTION OUTPUT ;
    USE SIGNAL ;
    PORT
      LAYER M5 ;
        RECT  5.04 0 5.064 0.084 ;
    END
  END o[32]
  PIN o[330]
    DIRECTION OUTPUT ;
    USE SIGNAL ;
    PORT
      LAYER M3 ;
        RECT  29.196 0 29.214 0.038 ;
    END
  END o[330]
  PIN o[331]
    DIRECTION OUTPUT ;
    USE SIGNAL ;
    PORT
      LAYER M3 ;
        RECT  29.268 0 29.286 0.038 ;
    END
  END o[331]
  PIN o[332]
    DIRECTION OUTPUT ;
    USE SIGNAL ;
    PORT
      LAYER M3 ;
        RECT  29.34 0 29.358 0.038 ;
    END
  END o[332]
  PIN o[333]
    DIRECTION OUTPUT ;
    USE SIGNAL ;
    PORT
      LAYER M3 ;
        RECT  29.448 0 29.466 0.038 ;
    END
  END o[333]
  PIN o[334]
    DIRECTION OUTPUT ;
    USE SIGNAL ;
    PORT
      LAYER M3 ;
        RECT  29.52 0 29.538 0.038 ;
    END
  END o[334]
  PIN o[335]
    DIRECTION OUTPUT ;
    USE SIGNAL ;
    PORT
      LAYER M3 ;
        RECT  29.592 0 29.61 0.038 ;
    END
  END o[335]
  PIN o[336]
    DIRECTION OUTPUT ;
    USE SIGNAL ;
    PORT
      LAYER M3 ;
        RECT  29.664 0 29.682 0.038 ;
    END
  END o[336]
  PIN o[337]
    DIRECTION OUTPUT ;
    USE SIGNAL ;
    PORT
      LAYER M3 ;
        RECT  29.772 0 29.79 0.038 ;
    END
  END o[337]
  PIN o[338]
    DIRECTION OUTPUT ;
    USE SIGNAL ;
    PORT
      LAYER M3 ;
        RECT  29.844 0 29.862 0.038 ;
    END
  END o[338]
  PIN o[339]
    DIRECTION OUTPUT ;
    USE SIGNAL ;
    PORT
      LAYER M3 ;
        RECT  29.916 0 29.934 0.038 ;
    END
  END o[339]
  PIN o[33]
    DIRECTION OUTPUT ;
    USE SIGNAL ;
    PORT
      LAYER M5 ;
        RECT  5.088 0 5.112 0.084 ;
    END
  END o[33]
  PIN o[340]
    DIRECTION OUTPUT ;
    USE SIGNAL ;
    PORT
      LAYER M3 ;
        RECT  29.988 0 30.006 0.038 ;
    END
  END o[340]
  PIN o[341]
    DIRECTION OUTPUT ;
    USE SIGNAL ;
    PORT
      LAYER M3 ;
        RECT  30.096 0 30.114 0.038 ;
    END
  END o[341]
  PIN o[342]
    DIRECTION OUTPUT ;
    USE SIGNAL ;
    PORT
      LAYER M3 ;
        RECT  30.168 0 30.186 0.038 ;
    END
  END o[342]
  PIN o[343]
    DIRECTION OUTPUT ;
    USE SIGNAL ;
    PORT
      LAYER M3 ;
        RECT  30.24 0 30.258 0.038 ;
    END
  END o[343]
  PIN o[344]
    DIRECTION OUTPUT ;
    USE SIGNAL ;
    PORT
      LAYER M3 ;
        RECT  30.312 0 30.33 0.038 ;
    END
  END o[344]
  PIN o[345]
    DIRECTION OUTPUT ;
    USE SIGNAL ;
    PORT
      LAYER M3 ;
        RECT  30.42 0 30.438 0.038 ;
    END
  END o[345]
  PIN o[346]
    DIRECTION OUTPUT ;
    USE SIGNAL ;
    PORT
      LAYER M3 ;
        RECT  30.492 0 30.51 0.038 ;
    END
  END o[346]
  PIN o[347]
    DIRECTION OUTPUT ;
    USE SIGNAL ;
    PORT
      LAYER M3 ;
        RECT  30.564 0 30.582 0.038 ;
    END
  END o[347]
  PIN o[348]
    DIRECTION OUTPUT ;
    USE SIGNAL ;
    PORT
      LAYER M3 ;
        RECT  30.636 0 30.654 0.038 ;
    END
  END o[348]
  PIN o[349]
    DIRECTION OUTPUT ;
    USE SIGNAL ;
    PORT
      LAYER M3 ;
        RECT  30.744 0 30.762 0.038 ;
    END
  END o[349]
  PIN o[34]
    DIRECTION OUTPUT ;
    USE SIGNAL ;
    PORT
      LAYER M5 ;
        RECT  5.184 0 5.208 0.084 ;
    END
  END o[34]
  PIN o[350]
    DIRECTION OUTPUT ;
    USE SIGNAL ;
    PORT
      LAYER M3 ;
        RECT  30.816 0 30.834 0.038 ;
    END
  END o[350]
  PIN o[351]
    DIRECTION OUTPUT ;
    USE SIGNAL ;
    PORT
      LAYER M3 ;
        RECT  30.888 0 30.906 0.038 ;
    END
  END o[351]
  PIN o[352]
    DIRECTION OUTPUT ;
    USE SIGNAL ;
    PORT
      LAYER M5 ;
        RECT  30.96 0 30.984 0.084 ;
    END
  END o[352]
  PIN o[353]
    DIRECTION OUTPUT ;
    USE SIGNAL ;
    PORT
      LAYER M5 ;
        RECT  31.056 0 31.08 0.084 ;
    END
  END o[353]
  PIN o[354]
    DIRECTION OUTPUT ;
    USE SIGNAL ;
    PORT
      LAYER M5 ;
        RECT  31.152 0 31.176 0.084 ;
    END
  END o[354]
  PIN o[355]
    DIRECTION OUTPUT ;
    USE SIGNAL ;
    PORT
      LAYER M5 ;
        RECT  31.2 0 31.224 0.084 ;
    END
  END o[355]
  PIN o[356]
    DIRECTION OUTPUT ;
    USE SIGNAL ;
    PORT
      LAYER M5 ;
        RECT  31.296 0 31.32 0.084 ;
    END
  END o[356]
  PIN o[357]
    DIRECTION OUTPUT ;
    USE SIGNAL ;
    PORT
      LAYER M5 ;
        RECT  31.392 0 31.416 0.084 ;
    END
  END o[357]
  PIN o[358]
    DIRECTION OUTPUT ;
    USE SIGNAL ;
    PORT
      LAYER M5 ;
        RECT  31.44 0 31.464 0.084 ;
    END
  END o[358]
  PIN o[359]
    DIRECTION OUTPUT ;
    USE SIGNAL ;
    PORT
      LAYER M5 ;
        RECT  31.536 0 31.56 0.084 ;
    END
  END o[359]
  PIN o[35]
    DIRECTION OUTPUT ;
    USE SIGNAL ;
    PORT
      LAYER M5 ;
        RECT  5.28 0 5.304 0.084 ;
    END
  END o[35]
  PIN o[360]
    DIRECTION OUTPUT ;
    USE SIGNAL ;
    PORT
      LAYER M5 ;
        RECT  31.632 0 31.656 0.084 ;
    END
  END o[360]
  PIN o[361]
    DIRECTION OUTPUT ;
    USE SIGNAL ;
    PORT
      LAYER M5 ;
        RECT  31.68 0 31.704 0.084 ;
    END
  END o[361]
  PIN o[362]
    DIRECTION OUTPUT ;
    USE SIGNAL ;
    PORT
      LAYER M5 ;
        RECT  31.776 0 31.8 0.084 ;
    END
  END o[362]
  PIN o[363]
    DIRECTION OUTPUT ;
    USE SIGNAL ;
    PORT
      LAYER M5 ;
        RECT  31.872 0 31.896 0.084 ;
    END
  END o[363]
  PIN o[364]
    DIRECTION OUTPUT ;
    USE SIGNAL ;
    PORT
      LAYER M5 ;
        RECT  31.92 0 31.944 0.084 ;
    END
  END o[364]
  PIN o[365]
    DIRECTION OUTPUT ;
    USE SIGNAL ;
    PORT
      LAYER M5 ;
        RECT  32.016 0 32.04 0.084 ;
    END
  END o[365]
  PIN o[366]
    DIRECTION OUTPUT ;
    USE SIGNAL ;
    PORT
      LAYER M5 ;
        RECT  32.112 0 32.136 0.084 ;
    END
  END o[366]
  PIN o[367]
    DIRECTION OUTPUT ;
    USE SIGNAL ;
    PORT
      LAYER M5 ;
        RECT  32.208 0 32.232 0.084 ;
    END
  END o[367]
  PIN o[368]
    DIRECTION OUTPUT ;
    USE SIGNAL ;
    PORT
      LAYER M5 ;
        RECT  32.256 0 32.28 0.084 ;
    END
  END o[368]
  PIN o[369]
    DIRECTION OUTPUT ;
    USE SIGNAL ;
    PORT
      LAYER M5 ;
        RECT  32.352 0 32.376 0.084 ;
    END
  END o[369]
  PIN o[36]
    DIRECTION OUTPUT ;
    USE SIGNAL ;
    PORT
      LAYER M5 ;
        RECT  5.328 0 5.352 0.084 ;
    END
  END o[36]
  PIN o[370]
    DIRECTION OUTPUT ;
    USE SIGNAL ;
    PORT
      LAYER M5 ;
        RECT  32.448 0 32.472 0.084 ;
    END
  END o[370]
  PIN o[371]
    DIRECTION OUTPUT ;
    USE SIGNAL ;
    PORT
      LAYER M5 ;
        RECT  32.496 0 32.52 0.084 ;
    END
  END o[371]
  PIN o[372]
    DIRECTION OUTPUT ;
    USE SIGNAL ;
    PORT
      LAYER M5 ;
        RECT  32.592 0 32.616 0.084 ;
    END
  END o[372]
  PIN o[373]
    DIRECTION OUTPUT ;
    USE SIGNAL ;
    PORT
      LAYER M5 ;
        RECT  32.688 0 32.712 0.084 ;
    END
  END o[373]
  PIN o[374]
    DIRECTION OUTPUT ;
    USE SIGNAL ;
    PORT
      LAYER M5 ;
        RECT  32.736 0 32.76 0.084 ;
    END
  END o[374]
  PIN o[375]
    DIRECTION OUTPUT ;
    USE SIGNAL ;
    PORT
      LAYER M5 ;
        RECT  32.832 0 32.856 0.084 ;
    END
  END o[375]
  PIN o[376]
    DIRECTION OUTPUT ;
    USE SIGNAL ;
    PORT
      LAYER M5 ;
        RECT  32.928 0 32.952 0.084 ;
    END
  END o[376]
  PIN o[377]
    DIRECTION OUTPUT ;
    USE SIGNAL ;
    PORT
      LAYER M5 ;
        RECT  32.976 0 33 0.084 ;
    END
  END o[377]
  PIN o[378]
    DIRECTION OUTPUT ;
    USE SIGNAL ;
    PORT
      LAYER M5 ;
        RECT  33.072 0 33.096 0.084 ;
    END
  END o[378]
  PIN o[379]
    DIRECTION OUTPUT ;
    USE SIGNAL ;
    PORT
      LAYER M5 ;
        RECT  33.168 0 33.192 0.084 ;
    END
  END o[379]
  PIN o[37]
    DIRECTION OUTPUT ;
    USE SIGNAL ;
    PORT
      LAYER M5 ;
        RECT  5.424 0 5.448 0.084 ;
    END
  END o[37]
  PIN o[380]
    DIRECTION OUTPUT ;
    USE SIGNAL ;
    PORT
      LAYER M5 ;
        RECT  33.216 0 33.24 0.084 ;
    END
  END o[380]
  PIN o[381]
    DIRECTION OUTPUT ;
    USE SIGNAL ;
    PORT
      LAYER M5 ;
        RECT  33.312 0 33.336 0.084 ;
    END
  END o[381]
  PIN o[382]
    DIRECTION OUTPUT ;
    USE SIGNAL ;
    PORT
      LAYER M5 ;
        RECT  33.408 0 33.432 0.084 ;
    END
  END o[382]
  PIN o[383]
    DIRECTION OUTPUT ;
    USE SIGNAL ;
    PORT
      LAYER M5 ;
        RECT  33.504 0 33.528 0.084 ;
    END
  END o[383]
  PIN o[384]
    DIRECTION OUTPUT ;
    USE SIGNAL ;
    PORT
      LAYER M3 ;
        RECT  33.552 0 33.57 0.038 ;
    END
  END o[384]
  PIN o[385]
    DIRECTION OUTPUT ;
    USE SIGNAL ;
    PORT
      LAYER M3 ;
        RECT  33.66 0 33.678 0.038 ;
    END
  END o[385]
  PIN o[386]
    DIRECTION OUTPUT ;
    USE SIGNAL ;
    PORT
      LAYER M3 ;
        RECT  33.732 0 33.75 0.038 ;
    END
  END o[386]
  PIN o[387]
    DIRECTION OUTPUT ;
    USE SIGNAL ;
    PORT
      LAYER M3 ;
        RECT  33.804 0 33.822 0.038 ;
    END
  END o[387]
  PIN o[388]
    DIRECTION OUTPUT ;
    USE SIGNAL ;
    PORT
      LAYER M3 ;
        RECT  33.876 0 33.894 0.038 ;
    END
  END o[388]
  PIN o[389]
    DIRECTION OUTPUT ;
    USE SIGNAL ;
    PORT
      LAYER M3 ;
        RECT  33.984 0 34.002 0.038 ;
    END
  END o[389]
  PIN o[38]
    DIRECTION OUTPUT ;
    USE SIGNAL ;
    PORT
      LAYER M5 ;
        RECT  5.52 0 5.544 0.084 ;
    END
  END o[38]
  PIN o[390]
    DIRECTION OUTPUT ;
    USE SIGNAL ;
    PORT
      LAYER M3 ;
        RECT  34.056 0 34.074 0.038 ;
    END
  END o[390]
  PIN o[391]
    DIRECTION OUTPUT ;
    USE SIGNAL ;
    PORT
      LAYER M3 ;
        RECT  34.128 0 34.146 0.038 ;
    END
  END o[391]
  PIN o[392]
    DIRECTION OUTPUT ;
    USE SIGNAL ;
    PORT
      LAYER M3 ;
        RECT  34.2 0 34.218 0.038 ;
    END
  END o[392]
  PIN o[393]
    DIRECTION OUTPUT ;
    USE SIGNAL ;
    PORT
      LAYER M3 ;
        RECT  34.308 0 34.326 0.038 ;
    END
  END o[393]
  PIN o[394]
    DIRECTION OUTPUT ;
    USE SIGNAL ;
    PORT
      LAYER M3 ;
        RECT  34.38 0 34.398 0.038 ;
    END
  END o[394]
  PIN o[395]
    DIRECTION OUTPUT ;
    USE SIGNAL ;
    PORT
      LAYER M3 ;
        RECT  34.452 0 34.47 0.038 ;
    END
  END o[395]
  PIN o[396]
    DIRECTION OUTPUT ;
    USE SIGNAL ;
    PORT
      LAYER M3 ;
        RECT  34.524 0 34.542 0.038 ;
    END
  END o[396]
  PIN o[397]
    DIRECTION OUTPUT ;
    USE SIGNAL ;
    PORT
      LAYER M3 ;
        RECT  34.632 0 34.65 0.038 ;
    END
  END o[397]
  PIN o[398]
    DIRECTION OUTPUT ;
    USE SIGNAL ;
    PORT
      LAYER M3 ;
        RECT  34.704 0 34.722 0.038 ;
    END
  END o[398]
  PIN o[399]
    DIRECTION OUTPUT ;
    USE SIGNAL ;
    PORT
      LAYER M3 ;
        RECT  34.776 0 34.794 0.038 ;
    END
  END o[399]
  PIN o[39]
    DIRECTION OUTPUT ;
    USE SIGNAL ;
    PORT
      LAYER M5 ;
        RECT  5.568 0 5.592 0.084 ;
    END
  END o[39]
  PIN o[3]
    DIRECTION OUTPUT ;
    USE SIGNAL ;
    PORT
      LAYER M3 ;
        RECT  2.664 0 2.682 0.038 ;
    END
  END o[3]
  PIN o[400]
    DIRECTION OUTPUT ;
    USE SIGNAL ;
    PORT
      LAYER M3 ;
        RECT  34.848 0 34.866 0.038 ;
    END
  END o[400]
  PIN o[401]
    DIRECTION OUTPUT ;
    USE SIGNAL ;
    PORT
      LAYER M3 ;
        RECT  34.956 0 34.974 0.038 ;
    END
  END o[401]
  PIN o[402]
    DIRECTION OUTPUT ;
    USE SIGNAL ;
    PORT
      LAYER M3 ;
        RECT  35.028 0 35.046 0.038 ;
    END
  END o[402]
  PIN o[403]
    DIRECTION OUTPUT ;
    USE SIGNAL ;
    PORT
      LAYER M3 ;
        RECT  35.1 0 35.118 0.038 ;
    END
  END o[403]
  PIN o[404]
    DIRECTION OUTPUT ;
    USE SIGNAL ;
    PORT
      LAYER M3 ;
        RECT  35.172 0 35.19 0.038 ;
    END
  END o[404]
  PIN o[405]
    DIRECTION OUTPUT ;
    USE SIGNAL ;
    PORT
      LAYER M3 ;
        RECT  35.28 0 35.298 0.038 ;
    END
  END o[405]
  PIN o[406]
    DIRECTION OUTPUT ;
    USE SIGNAL ;
    PORT
      LAYER M3 ;
        RECT  35.352 0 35.37 0.038 ;
    END
  END o[406]
  PIN o[407]
    DIRECTION OUTPUT ;
    USE SIGNAL ;
    PORT
      LAYER M3 ;
        RECT  35.424 0 35.442 0.038 ;
    END
  END o[407]
  PIN o[408]
    DIRECTION OUTPUT ;
    USE SIGNAL ;
    PORT
      LAYER M3 ;
        RECT  35.496 0 35.514 0.038 ;
    END
  END o[408]
  PIN o[409]
    DIRECTION OUTPUT ;
    USE SIGNAL ;
    PORT
      LAYER M3 ;
        RECT  35.604 0 35.622 0.038 ;
    END
  END o[409]
  PIN o[40]
    DIRECTION OUTPUT ;
    USE SIGNAL ;
    PORT
      LAYER M5 ;
        RECT  5.664 0 5.688 0.084 ;
    END
  END o[40]
  PIN o[410]
    DIRECTION OUTPUT ;
    USE SIGNAL ;
    PORT
      LAYER M3 ;
        RECT  35.676 0 35.694 0.038 ;
    END
  END o[410]
  PIN o[411]
    DIRECTION OUTPUT ;
    USE SIGNAL ;
    PORT
      LAYER M3 ;
        RECT  35.748 0 35.766 0.038 ;
    END
  END o[411]
  PIN o[412]
    DIRECTION OUTPUT ;
    USE SIGNAL ;
    PORT
      LAYER M3 ;
        RECT  35.82 0 35.838 0.038 ;
    END
  END o[412]
  PIN o[413]
    DIRECTION OUTPUT ;
    USE SIGNAL ;
    PORT
      LAYER M3 ;
        RECT  35.928 0 35.946 0.038 ;
    END
  END o[413]
  PIN o[414]
    DIRECTION OUTPUT ;
    USE SIGNAL ;
    PORT
      LAYER M3 ;
        RECT  36 0 36.018 0.038 ;
    END
  END o[414]
  PIN o[415]
    DIRECTION OUTPUT ;
    USE SIGNAL ;
    PORT
      LAYER M3 ;
        RECT  36.072 0 36.09 0.038 ;
    END
  END o[415]
  PIN o[416]
    DIRECTION OUTPUT ;
    USE SIGNAL ;
    PORT
      LAYER M5 ;
        RECT  36.144 0 36.168 0.084 ;
    END
  END o[416]
  PIN o[417]
    DIRECTION OUTPUT ;
    USE SIGNAL ;
    PORT
      LAYER M5 ;
        RECT  36.24 0 36.264 0.084 ;
    END
  END o[417]
  PIN o[418]
    DIRECTION OUTPUT ;
    USE SIGNAL ;
    PORT
      LAYER M5 ;
        RECT  36.336 0 36.36 0.084 ;
    END
  END o[418]
  PIN o[419]
    DIRECTION OUTPUT ;
    USE SIGNAL ;
    PORT
      LAYER M5 ;
        RECT  36.384 0 36.408 0.084 ;
    END
  END o[419]
  PIN o[41]
    DIRECTION OUTPUT ;
    USE SIGNAL ;
    PORT
      LAYER M5 ;
        RECT  5.76 0 5.784 0.084 ;
    END
  END o[41]
  PIN o[420]
    DIRECTION OUTPUT ;
    USE SIGNAL ;
    PORT
      LAYER M5 ;
        RECT  36.48 0 36.504 0.084 ;
    END
  END o[420]
  PIN o[421]
    DIRECTION OUTPUT ;
    USE SIGNAL ;
    PORT
      LAYER M5 ;
        RECT  36.576 0 36.6 0.084 ;
    END
  END o[421]
  PIN o[422]
    DIRECTION OUTPUT ;
    USE SIGNAL ;
    PORT
      LAYER M5 ;
        RECT  36.624 0 36.648 0.084 ;
    END
  END o[422]
  PIN o[423]
    DIRECTION OUTPUT ;
    USE SIGNAL ;
    PORT
      LAYER M5 ;
        RECT  36.72 0 36.744 0.084 ;
    END
  END o[423]
  PIN o[424]
    DIRECTION OUTPUT ;
    USE SIGNAL ;
    PORT
      LAYER M5 ;
        RECT  36.816 0 36.84 0.084 ;
    END
  END o[424]
  PIN o[425]
    DIRECTION OUTPUT ;
    USE SIGNAL ;
    PORT
      LAYER M5 ;
        RECT  36.912 0 36.936 0.084 ;
    END
  END o[425]
  PIN o[426]
    DIRECTION OUTPUT ;
    USE SIGNAL ;
    PORT
      LAYER M5 ;
        RECT  36.96 0 36.984 0.084 ;
    END
  END o[426]
  PIN o[427]
    DIRECTION OUTPUT ;
    USE SIGNAL ;
    PORT
      LAYER M5 ;
        RECT  37.056 0 37.08 0.084 ;
    END
  END o[427]
  PIN o[428]
    DIRECTION OUTPUT ;
    USE SIGNAL ;
    PORT
      LAYER M5 ;
        RECT  37.152 0 37.176 0.084 ;
    END
  END o[428]
  PIN o[429]
    DIRECTION OUTPUT ;
    USE SIGNAL ;
    PORT
      LAYER M5 ;
        RECT  37.2 0 37.224 0.084 ;
    END
  END o[429]
  PIN o[42]
    DIRECTION OUTPUT ;
    USE SIGNAL ;
    PORT
      LAYER M5 ;
        RECT  5.856 0 5.88 0.084 ;
    END
  END o[42]
  PIN o[430]
    DIRECTION OUTPUT ;
    USE SIGNAL ;
    PORT
      LAYER M5 ;
        RECT  37.296 0 37.32 0.084 ;
    END
  END o[430]
  PIN o[431]
    DIRECTION OUTPUT ;
    USE SIGNAL ;
    PORT
      LAYER M5 ;
        RECT  37.392 0 37.416 0.084 ;
    END
  END o[431]
  PIN o[432]
    DIRECTION OUTPUT ;
    USE SIGNAL ;
    PORT
      LAYER M5 ;
        RECT  37.44 0 37.464 0.084 ;
    END
  END o[432]
  PIN o[433]
    DIRECTION OUTPUT ;
    USE SIGNAL ;
    PORT
      LAYER M5 ;
        RECT  37.536 0 37.56 0.084 ;
    END
  END o[433]
  PIN o[434]
    DIRECTION OUTPUT ;
    USE SIGNAL ;
    PORT
      LAYER M5 ;
        RECT  37.632 0 37.656 0.084 ;
    END
  END o[434]
  PIN o[435]
    DIRECTION OUTPUT ;
    USE SIGNAL ;
    PORT
      LAYER M5 ;
        RECT  37.68 0 37.704 0.084 ;
    END
  END o[435]
  PIN o[436]
    DIRECTION OUTPUT ;
    USE SIGNAL ;
    PORT
      LAYER M5 ;
        RECT  37.776 0 37.8 0.084 ;
    END
  END o[436]
  PIN o[437]
    DIRECTION OUTPUT ;
    USE SIGNAL ;
    PORT
      LAYER M5 ;
        RECT  37.872 0 37.896 0.084 ;
    END
  END o[437]
  PIN o[438]
    DIRECTION OUTPUT ;
    USE SIGNAL ;
    PORT
      LAYER M5 ;
        RECT  37.92 0 37.944 0.084 ;
    END
  END o[438]
  PIN o[439]
    DIRECTION OUTPUT ;
    USE SIGNAL ;
    PORT
      LAYER M5 ;
        RECT  38.016 0 38.04 0.084 ;
    END
  END o[439]
  PIN o[43]
    DIRECTION OUTPUT ;
    USE SIGNAL ;
    PORT
      LAYER M5 ;
        RECT  5.904 0 5.928 0.084 ;
    END
  END o[43]
  PIN o[440]
    DIRECTION OUTPUT ;
    USE SIGNAL ;
    PORT
      LAYER M5 ;
        RECT  38.112 0 38.136 0.084 ;
    END
  END o[440]
  PIN o[441]
    DIRECTION OUTPUT ;
    USE SIGNAL ;
    PORT
      LAYER M5 ;
        RECT  38.208 0 38.232 0.084 ;
    END
  END o[441]
  PIN o[442]
    DIRECTION OUTPUT ;
    USE SIGNAL ;
    PORT
      LAYER M5 ;
        RECT  38.256 0 38.28 0.084 ;
    END
  END o[442]
  PIN o[443]
    DIRECTION OUTPUT ;
    USE SIGNAL ;
    PORT
      LAYER M5 ;
        RECT  38.352 0 38.376 0.084 ;
    END
  END o[443]
  PIN o[444]
    DIRECTION OUTPUT ;
    USE SIGNAL ;
    PORT
      LAYER M5 ;
        RECT  38.448 0 38.472 0.084 ;
    END
  END o[444]
  PIN o[445]
    DIRECTION OUTPUT ;
    USE SIGNAL ;
    PORT
      LAYER M5 ;
        RECT  38.496 0 38.52 0.084 ;
    END
  END o[445]
  PIN o[446]
    DIRECTION OUTPUT ;
    USE SIGNAL ;
    PORT
      LAYER M5 ;
        RECT  38.592 0 38.616 0.084 ;
    END
  END o[446]
  PIN o[447]
    DIRECTION OUTPUT ;
    USE SIGNAL ;
    PORT
      LAYER M5 ;
        RECT  38.688 0 38.712 0.084 ;
    END
  END o[447]
  PIN o[448]
    DIRECTION OUTPUT ;
    USE SIGNAL ;
    PORT
      LAYER M3 ;
        RECT  38.772 0 38.79 0.038 ;
    END
  END o[448]
  PIN o[449]
    DIRECTION OUTPUT ;
    USE SIGNAL ;
    PORT
      LAYER M3 ;
        RECT  38.844 0 38.862 0.038 ;
    END
  END o[449]
  PIN o[44]
    DIRECTION OUTPUT ;
    USE SIGNAL ;
    PORT
      LAYER M5 ;
        RECT  6 0 6.024 0.084 ;
    END
  END o[44]
  PIN o[450]
    DIRECTION OUTPUT ;
    USE SIGNAL ;
    PORT
      LAYER M3 ;
        RECT  38.916 0 38.934 0.038 ;
    END
  END o[450]
  PIN o[451]
    DIRECTION OUTPUT ;
    USE SIGNAL ;
    PORT
      LAYER M3 ;
        RECT  38.988 0 39.006 0.038 ;
    END
  END o[451]
  PIN o[452]
    DIRECTION OUTPUT ;
    USE SIGNAL ;
    PORT
      LAYER M3 ;
        RECT  39.096 0 39.114 0.038 ;
    END
  END o[452]
  PIN o[453]
    DIRECTION OUTPUT ;
    USE SIGNAL ;
    PORT
      LAYER M3 ;
        RECT  39.168 0 39.186 0.038 ;
    END
  END o[453]
  PIN o[454]
    DIRECTION OUTPUT ;
    USE SIGNAL ;
    PORT
      LAYER M3 ;
        RECT  39.24 0 39.258 0.038 ;
    END
  END o[454]
  PIN o[455]
    DIRECTION OUTPUT ;
    USE SIGNAL ;
    PORT
      LAYER M3 ;
        RECT  39.312 0 39.33 0.038 ;
    END
  END o[455]
  PIN o[456]
    DIRECTION OUTPUT ;
    USE SIGNAL ;
    PORT
      LAYER M3 ;
        RECT  39.42 0 39.438 0.038 ;
    END
  END o[456]
  PIN o[457]
    DIRECTION OUTPUT ;
    USE SIGNAL ;
    PORT
      LAYER M3 ;
        RECT  39.492 0 39.51 0.038 ;
    END
  END o[457]
  PIN o[458]
    DIRECTION OUTPUT ;
    USE SIGNAL ;
    PORT
      LAYER M3 ;
        RECT  39.564 0 39.582 0.038 ;
    END
  END o[458]
  PIN o[459]
    DIRECTION OUTPUT ;
    USE SIGNAL ;
    PORT
      LAYER M3 ;
        RECT  39.636 0 39.654 0.038 ;
    END
  END o[459]
  PIN o[45]
    DIRECTION OUTPUT ;
    USE SIGNAL ;
    PORT
      LAYER M5 ;
        RECT  6.096 0 6.12 0.084 ;
    END
  END o[45]
  PIN o[460]
    DIRECTION OUTPUT ;
    USE SIGNAL ;
    PORT
      LAYER M3 ;
        RECT  39.744 0 39.762 0.038 ;
    END
  END o[460]
  PIN o[461]
    DIRECTION OUTPUT ;
    USE SIGNAL ;
    PORT
      LAYER M3 ;
        RECT  39.816 0 39.834 0.038 ;
    END
  END o[461]
  PIN o[462]
    DIRECTION OUTPUT ;
    USE SIGNAL ;
    PORT
      LAYER M3 ;
        RECT  39.888 0 39.906 0.038 ;
    END
  END o[462]
  PIN o[463]
    DIRECTION OUTPUT ;
    USE SIGNAL ;
    PORT
      LAYER M3 ;
        RECT  39.96 0 39.978 0.038 ;
    END
  END o[463]
  PIN o[464]
    DIRECTION OUTPUT ;
    USE SIGNAL ;
    PORT
      LAYER M3 ;
        RECT  40.068 0 40.086 0.038 ;
    END
  END o[464]
  PIN o[465]
    DIRECTION OUTPUT ;
    USE SIGNAL ;
    PORT
      LAYER M3 ;
        RECT  40.14 0 40.158 0.038 ;
    END
  END o[465]
  PIN o[466]
    DIRECTION OUTPUT ;
    USE SIGNAL ;
    PORT
      LAYER M3 ;
        RECT  40.212 0 40.23 0.038 ;
    END
  END o[466]
  PIN o[467]
    DIRECTION OUTPUT ;
    USE SIGNAL ;
    PORT
      LAYER M3 ;
        RECT  40.284 0 40.302 0.038 ;
    END
  END o[467]
  PIN o[468]
    DIRECTION OUTPUT ;
    USE SIGNAL ;
    PORT
      LAYER M3 ;
        RECT  40.392 0 40.41 0.038 ;
    END
  END o[468]
  PIN o[469]
    DIRECTION OUTPUT ;
    USE SIGNAL ;
    PORT
      LAYER M3 ;
        RECT  40.464 0 40.482 0.038 ;
    END
  END o[469]
  PIN o[46]
    DIRECTION OUTPUT ;
    USE SIGNAL ;
    PORT
      LAYER M5 ;
        RECT  6.144 0 6.168 0.084 ;
    END
  END o[46]
  PIN o[470]
    DIRECTION OUTPUT ;
    USE SIGNAL ;
    PORT
      LAYER M3 ;
        RECT  40.536 0 40.554 0.038 ;
    END
  END o[470]
  PIN o[471]
    DIRECTION OUTPUT ;
    USE SIGNAL ;
    PORT
      LAYER M3 ;
        RECT  40.608 0 40.626 0.038 ;
    END
  END o[471]
  PIN o[472]
    DIRECTION OUTPUT ;
    USE SIGNAL ;
    PORT
      LAYER M3 ;
        RECT  40.716 0 40.734 0.038 ;
    END
  END o[472]
  PIN o[473]
    DIRECTION OUTPUT ;
    USE SIGNAL ;
    PORT
      LAYER M3 ;
        RECT  40.788 0 40.806 0.038 ;
    END
  END o[473]
  PIN o[474]
    DIRECTION OUTPUT ;
    USE SIGNAL ;
    PORT
      LAYER M3 ;
        RECT  40.86 0 40.878 0.038 ;
    END
  END o[474]
  PIN o[475]
    DIRECTION OUTPUT ;
    USE SIGNAL ;
    PORT
      LAYER M3 ;
        RECT  40.932 0 40.95 0.038 ;
    END
  END o[475]
  PIN o[476]
    DIRECTION OUTPUT ;
    USE SIGNAL ;
    PORT
      LAYER M3 ;
        RECT  41.04 0 41.058 0.038 ;
    END
  END o[476]
  PIN o[477]
    DIRECTION OUTPUT ;
    USE SIGNAL ;
    PORT
      LAYER M3 ;
        RECT  41.112 0 41.13 0.038 ;
    END
  END o[477]
  PIN o[478]
    DIRECTION OUTPUT ;
    USE SIGNAL ;
    PORT
      LAYER M3 ;
        RECT  41.184 0 41.202 0.038 ;
    END
  END o[478]
  PIN o[479]
    DIRECTION OUTPUT ;
    USE SIGNAL ;
    PORT
      LAYER M3 ;
        RECT  41.256 0 41.274 0.038 ;
    END
  END o[479]
  PIN o[47]
    DIRECTION OUTPUT ;
    USE SIGNAL ;
    PORT
      LAYER M5 ;
        RECT  6.24 0 6.264 0.084 ;
    END
  END o[47]
  PIN o[480]
    DIRECTION OUTPUT ;
    USE SIGNAL ;
    PORT
      LAYER M5 ;
        RECT  41.328 0 41.352 0.084 ;
    END
  END o[480]
  PIN o[481]
    DIRECTION OUTPUT ;
    USE SIGNAL ;
    PORT
      LAYER M5 ;
        RECT  41.424 0 41.448 0.084 ;
    END
  END o[481]
  PIN o[482]
    DIRECTION OUTPUT ;
    USE SIGNAL ;
    PORT
      LAYER M5 ;
        RECT  41.52 0 41.544 0.084 ;
    END
  END o[482]
  PIN o[483]
    DIRECTION OUTPUT ;
    USE SIGNAL ;
    PORT
      LAYER M5 ;
        RECT  41.568 0 41.592 0.084 ;
    END
  END o[483]
  PIN o[484]
    DIRECTION OUTPUT ;
    USE SIGNAL ;
    PORT
      LAYER M5 ;
        RECT  41.664 0 41.688 0.084 ;
    END
  END o[484]
  PIN o[485]
    DIRECTION OUTPUT ;
    USE SIGNAL ;
    PORT
      LAYER M5 ;
        RECT  41.76 0 41.784 0.084 ;
    END
  END o[485]
  PIN o[486]
    DIRECTION OUTPUT ;
    USE SIGNAL ;
    PORT
      LAYER M5 ;
        RECT  41.856 0 41.88 0.084 ;
    END
  END o[486]
  PIN o[487]
    DIRECTION OUTPUT ;
    USE SIGNAL ;
    PORT
      LAYER M5 ;
        RECT  41.904 0 41.928 0.084 ;
    END
  END o[487]
  PIN o[488]
    DIRECTION OUTPUT ;
    USE SIGNAL ;
    PORT
      LAYER M5 ;
        RECT  42 0 42.024 0.084 ;
    END
  END o[488]
  PIN o[489]
    DIRECTION OUTPUT ;
    USE SIGNAL ;
    PORT
      LAYER M5 ;
        RECT  42.096 0 42.12 0.084 ;
    END
  END o[489]
  PIN o[48]
    DIRECTION OUTPUT ;
    USE SIGNAL ;
    PORT
      LAYER M5 ;
        RECT  6.336 0 6.36 0.084 ;
    END
  END o[48]
  PIN o[490]
    DIRECTION OUTPUT ;
    USE SIGNAL ;
    PORT
      LAYER M5 ;
        RECT  42.144 0 42.168 0.084 ;
    END
  END o[490]
  PIN o[491]
    DIRECTION OUTPUT ;
    USE SIGNAL ;
    PORT
      LAYER M5 ;
        RECT  42.24 0 42.264 0.084 ;
    END
  END o[491]
  PIN o[492]
    DIRECTION OUTPUT ;
    USE SIGNAL ;
    PORT
      LAYER M5 ;
        RECT  42.336 0 42.36 0.084 ;
    END
  END o[492]
  PIN o[493]
    DIRECTION OUTPUT ;
    USE SIGNAL ;
    PORT
      LAYER M5 ;
        RECT  42.384 0 42.408 0.084 ;
    END
  END o[493]
  PIN o[494]
    DIRECTION OUTPUT ;
    USE SIGNAL ;
    PORT
      LAYER M5 ;
        RECT  42.48 0 42.504 0.084 ;
    END
  END o[494]
  PIN o[495]
    DIRECTION OUTPUT ;
    USE SIGNAL ;
    PORT
      LAYER M5 ;
        RECT  42.576 0 42.6 0.084 ;
    END
  END o[495]
  PIN o[496]
    DIRECTION OUTPUT ;
    USE SIGNAL ;
    PORT
      LAYER M5 ;
        RECT  42.624 0 42.648 0.084 ;
    END
  END o[496]
  PIN o[497]
    DIRECTION OUTPUT ;
    USE SIGNAL ;
    PORT
      LAYER M5 ;
        RECT  42.72 0 42.744 0.084 ;
    END
  END o[497]
  PIN o[498]
    DIRECTION OUTPUT ;
    USE SIGNAL ;
    PORT
      LAYER M5 ;
        RECT  42.816 0 42.84 0.084 ;
    END
  END o[498]
  PIN o[499]
    DIRECTION OUTPUT ;
    USE SIGNAL ;
    PORT
      LAYER M5 ;
        RECT  42.912 0 42.936 0.084 ;
    END
  END o[499]
  PIN o[49]
    DIRECTION OUTPUT ;
    USE SIGNAL ;
    PORT
      LAYER M5 ;
        RECT  6.384 0 6.408 0.084 ;
    END
  END o[49]
  PIN o[4]
    DIRECTION OUTPUT ;
    USE SIGNAL ;
    PORT
      LAYER M3 ;
        RECT  2.772 0 2.79 0.038 ;
    END
  END o[4]
  PIN o[500]
    DIRECTION OUTPUT ;
    USE SIGNAL ;
    PORT
      LAYER M5 ;
        RECT  42.96 0 42.984 0.084 ;
    END
  END o[500]
  PIN o[501]
    DIRECTION OUTPUT ;
    USE SIGNAL ;
    PORT
      LAYER M5 ;
        RECT  43.056 0 43.08 0.084 ;
    END
  END o[501]
  PIN o[502]
    DIRECTION OUTPUT ;
    USE SIGNAL ;
    PORT
      LAYER M5 ;
        RECT  43.152 0 43.176 0.084 ;
    END
  END o[502]
  PIN o[503]
    DIRECTION OUTPUT ;
    USE SIGNAL ;
    PORT
      LAYER M5 ;
        RECT  43.2 0 43.224 0.084 ;
    END
  END o[503]
  PIN o[504]
    DIRECTION OUTPUT ;
    USE SIGNAL ;
    PORT
      LAYER M5 ;
        RECT  43.296 0 43.32 0.084 ;
    END
  END o[504]
  PIN o[505]
    DIRECTION OUTPUT ;
    USE SIGNAL ;
    PORT
      LAYER M5 ;
        RECT  43.392 0 43.416 0.084 ;
    END
  END o[505]
  PIN o[506]
    DIRECTION OUTPUT ;
    USE SIGNAL ;
    PORT
      LAYER M5 ;
        RECT  43.44 0 43.464 0.084 ;
    END
  END o[506]
  PIN o[507]
    DIRECTION OUTPUT ;
    USE SIGNAL ;
    PORT
      LAYER M5 ;
        RECT  43.536 0 43.56 0.084 ;
    END
  END o[507]
  PIN o[508]
    DIRECTION OUTPUT ;
    USE SIGNAL ;
    PORT
      LAYER M5 ;
        RECT  43.632 0 43.656 0.084 ;
    END
  END o[508]
  PIN o[509]
    DIRECTION OUTPUT ;
    USE SIGNAL ;
    PORT
      LAYER M5 ;
        RECT  43.68 0 43.704 0.084 ;
    END
  END o[509]
  PIN o[50]
    DIRECTION OUTPUT ;
    USE SIGNAL ;
    PORT
      LAYER M5 ;
        RECT  6.48 0 6.504 0.084 ;
    END
  END o[50]
  PIN o[510]
    DIRECTION OUTPUT ;
    USE SIGNAL ;
    PORT
      LAYER M5 ;
        RECT  43.776 0 43.8 0.084 ;
    END
  END o[510]
  PIN o[511]
    DIRECTION OUTPUT ;
    USE SIGNAL ;
    PORT
      LAYER M5 ;
        RECT  43.872 0 43.896 0.084 ;
    END
  END o[511]
  PIN o[512]
    DIRECTION OUTPUT ;
    USE SIGNAL ;
    PORT
      LAYER M3 ;
        RECT  43.956 0 43.974 0.038 ;
    END
  END o[512]
  PIN o[513]
    DIRECTION OUTPUT ;
    USE SIGNAL ;
    PORT
      LAYER M3 ;
        RECT  44.028 0 44.046 0.038 ;
    END
  END o[513]
  PIN o[514]
    DIRECTION OUTPUT ;
    USE SIGNAL ;
    PORT
      LAYER M3 ;
        RECT  44.1 0 44.118 0.038 ;
    END
  END o[514]
  PIN o[515]
    DIRECTION OUTPUT ;
    USE SIGNAL ;
    PORT
      LAYER M3 ;
        RECT  44.172 0 44.19 0.038 ;
    END
  END o[515]
  PIN o[516]
    DIRECTION OUTPUT ;
    USE SIGNAL ;
    PORT
      LAYER M3 ;
        RECT  44.28 0 44.298 0.038 ;
    END
  END o[516]
  PIN o[517]
    DIRECTION OUTPUT ;
    USE SIGNAL ;
    PORT
      LAYER M3 ;
        RECT  44.352 0 44.37 0.038 ;
    END
  END o[517]
  PIN o[518]
    DIRECTION OUTPUT ;
    USE SIGNAL ;
    PORT
      LAYER M3 ;
        RECT  44.424 0 44.442 0.038 ;
    END
  END o[518]
  PIN o[519]
    DIRECTION OUTPUT ;
    USE SIGNAL ;
    PORT
      LAYER M3 ;
        RECT  44.496 0 44.514 0.038 ;
    END
  END o[519]
  PIN o[51]
    DIRECTION OUTPUT ;
    USE SIGNAL ;
    PORT
      LAYER M5 ;
        RECT  6.576 0 6.6 0.084 ;
    END
  END o[51]
  PIN o[520]
    DIRECTION OUTPUT ;
    USE SIGNAL ;
    PORT
      LAYER M3 ;
        RECT  44.604 0 44.622 0.038 ;
    END
  END o[520]
  PIN o[521]
    DIRECTION OUTPUT ;
    USE SIGNAL ;
    PORT
      LAYER M3 ;
        RECT  44.676 0 44.694 0.038 ;
    END
  END o[521]
  PIN o[522]
    DIRECTION OUTPUT ;
    USE SIGNAL ;
    PORT
      LAYER M3 ;
        RECT  44.748 0 44.766 0.038 ;
    END
  END o[522]
  PIN o[523]
    DIRECTION OUTPUT ;
    USE SIGNAL ;
    PORT
      LAYER M3 ;
        RECT  44.82 0 44.838 0.038 ;
    END
  END o[523]
  PIN o[524]
    DIRECTION OUTPUT ;
    USE SIGNAL ;
    PORT
      LAYER M3 ;
        RECT  44.928 0 44.946 0.038 ;
    END
  END o[524]
  PIN o[525]
    DIRECTION OUTPUT ;
    USE SIGNAL ;
    PORT
      LAYER M3 ;
        RECT  45 0 45.018 0.038 ;
    END
  END o[525]
  PIN o[526]
    DIRECTION OUTPUT ;
    USE SIGNAL ;
    PORT
      LAYER M3 ;
        RECT  45.072 0 45.09 0.038 ;
    END
  END o[526]
  PIN o[527]
    DIRECTION OUTPUT ;
    USE SIGNAL ;
    PORT
      LAYER M3 ;
        RECT  45.144 0 45.162 0.038 ;
    END
  END o[527]
  PIN o[528]
    DIRECTION OUTPUT ;
    USE SIGNAL ;
    PORT
      LAYER M3 ;
        RECT  45.252 0 45.27 0.038 ;
    END
  END o[528]
  PIN o[529]
    DIRECTION OUTPUT ;
    USE SIGNAL ;
    PORT
      LAYER M3 ;
        RECT  45.324 0 45.342 0.038 ;
    END
  END o[529]
  PIN o[52]
    DIRECTION OUTPUT ;
    USE SIGNAL ;
    PORT
      LAYER M5 ;
        RECT  6.624 0 6.648 0.084 ;
    END
  END o[52]
  PIN o[530]
    DIRECTION OUTPUT ;
    USE SIGNAL ;
    PORT
      LAYER M3 ;
        RECT  45.396 0 45.414 0.038 ;
    END
  END o[530]
  PIN o[531]
    DIRECTION OUTPUT ;
    USE SIGNAL ;
    PORT
      LAYER M3 ;
        RECT  45.504 0 45.522 0.038 ;
    END
  END o[531]
  PIN o[532]
    DIRECTION OUTPUT ;
    USE SIGNAL ;
    PORT
      LAYER M3 ;
        RECT  45.576 0 45.594 0.038 ;
    END
  END o[532]
  PIN o[533]
    DIRECTION OUTPUT ;
    USE SIGNAL ;
    PORT
      LAYER M3 ;
        RECT  45.648 0 45.666 0.038 ;
    END
  END o[533]
  PIN o[534]
    DIRECTION OUTPUT ;
    USE SIGNAL ;
    PORT
      LAYER M3 ;
        RECT  45.72 0 45.738 0.038 ;
    END
  END o[534]
  PIN o[535]
    DIRECTION OUTPUT ;
    USE SIGNAL ;
    PORT
      LAYER M3 ;
        RECT  45.828 0 45.846 0.038 ;
    END
  END o[535]
  PIN o[536]
    DIRECTION OUTPUT ;
    USE SIGNAL ;
    PORT
      LAYER M3 ;
        RECT  45.9 0 45.918 0.038 ;
    END
  END o[536]
  PIN o[537]
    DIRECTION OUTPUT ;
    USE SIGNAL ;
    PORT
      LAYER M3 ;
        RECT  45.972 0 45.99 0.038 ;
    END
  END o[537]
  PIN o[538]
    DIRECTION OUTPUT ;
    USE SIGNAL ;
    PORT
      LAYER M3 ;
        RECT  46.044 0 46.062 0.038 ;
    END
  END o[538]
  PIN o[539]
    DIRECTION OUTPUT ;
    USE SIGNAL ;
    PORT
      LAYER M3 ;
        RECT  46.152 0 46.17 0.038 ;
    END
  END o[539]
  PIN o[53]
    DIRECTION OUTPUT ;
    USE SIGNAL ;
    PORT
      LAYER M5 ;
        RECT  6.72 0 6.744 0.084 ;
    END
  END o[53]
  PIN o[540]
    DIRECTION OUTPUT ;
    USE SIGNAL ;
    PORT
      LAYER M3 ;
        RECT  46.224 0 46.242 0.038 ;
    END
  END o[540]
  PIN o[541]
    DIRECTION OUTPUT ;
    USE SIGNAL ;
    PORT
      LAYER M3 ;
        RECT  46.296 0 46.314 0.038 ;
    END
  END o[541]
  PIN o[542]
    DIRECTION OUTPUT ;
    USE SIGNAL ;
    PORT
      LAYER M3 ;
        RECT  46.368 0 46.386 0.038 ;
    END
  END o[542]
  PIN o[543]
    DIRECTION OUTPUT ;
    USE SIGNAL ;
    PORT
      LAYER M3 ;
        RECT  46.476 0 46.494 0.038 ;
    END
  END o[543]
  PIN o[544]
    DIRECTION OUTPUT ;
    USE SIGNAL ;
    PORT
      LAYER M5 ;
        RECT  46.56 0 46.584 0.084 ;
    END
  END o[544]
  PIN o[545]
    DIRECTION OUTPUT ;
    USE SIGNAL ;
    PORT
      LAYER M5 ;
        RECT  46.608 0 46.632 0.084 ;
    END
  END o[545]
  PIN o[546]
    DIRECTION OUTPUT ;
    USE SIGNAL ;
    PORT
      LAYER M5 ;
        RECT  46.704 0 46.728 0.084 ;
    END
  END o[546]
  PIN o[547]
    DIRECTION OUTPUT ;
    USE SIGNAL ;
    PORT
      LAYER M5 ;
        RECT  46.8 0 46.824 0.084 ;
    END
  END o[547]
  PIN o[548]
    DIRECTION OUTPUT ;
    USE SIGNAL ;
    PORT
      LAYER M5 ;
        RECT  46.848 0 46.872 0.084 ;
    END
  END o[548]
  PIN o[549]
    DIRECTION OUTPUT ;
    USE SIGNAL ;
    PORT
      LAYER M5 ;
        RECT  46.944 0 46.968 0.084 ;
    END
  END o[549]
  PIN o[54]
    DIRECTION OUTPUT ;
    USE SIGNAL ;
    PORT
      LAYER M5 ;
        RECT  6.816 0 6.84 0.084 ;
    END
  END o[54]
  PIN o[550]
    DIRECTION OUTPUT ;
    USE SIGNAL ;
    PORT
      LAYER M5 ;
        RECT  47.04 0 47.064 0.084 ;
    END
  END o[550]
  PIN o[551]
    DIRECTION OUTPUT ;
    USE SIGNAL ;
    PORT
      LAYER M5 ;
        RECT  47.088 0 47.112 0.084 ;
    END
  END o[551]
  PIN o[552]
    DIRECTION OUTPUT ;
    USE SIGNAL ;
    PORT
      LAYER M5 ;
        RECT  47.184 0 47.208 0.084 ;
    END
  END o[552]
  PIN o[553]
    DIRECTION OUTPUT ;
    USE SIGNAL ;
    PORT
      LAYER M5 ;
        RECT  47.28 0 47.304 0.084 ;
    END
  END o[553]
  PIN o[554]
    DIRECTION OUTPUT ;
    USE SIGNAL ;
    PORT
      LAYER M5 ;
        RECT  47.328 0 47.352 0.084 ;
    END
  END o[554]
  PIN o[555]
    DIRECTION OUTPUT ;
    USE SIGNAL ;
    PORT
      LAYER M5 ;
        RECT  47.424 0 47.448 0.084 ;
    END
  END o[555]
  PIN o[556]
    DIRECTION OUTPUT ;
    USE SIGNAL ;
    PORT
      LAYER M5 ;
        RECT  47.52 0 47.544 0.084 ;
    END
  END o[556]
  PIN o[557]
    DIRECTION OUTPUT ;
    USE SIGNAL ;
    PORT
      LAYER M5 ;
        RECT  47.568 0 47.592 0.084 ;
    END
  END o[557]
  PIN o[558]
    DIRECTION OUTPUT ;
    USE SIGNAL ;
    PORT
      LAYER M5 ;
        RECT  47.664 0 47.688 0.084 ;
    END
  END o[558]
  PIN o[559]
    DIRECTION OUTPUT ;
    USE SIGNAL ;
    PORT
      LAYER M5 ;
        RECT  47.76 0 47.784 0.084 ;
    END
  END o[559]
  PIN o[55]
    DIRECTION OUTPUT ;
    USE SIGNAL ;
    PORT
      LAYER M5 ;
        RECT  6.912 0 6.936 0.084 ;
    END
  END o[55]
  PIN o[560]
    DIRECTION OUTPUT ;
    USE SIGNAL ;
    PORT
      LAYER M5 ;
        RECT  47.856 0 47.88 0.084 ;
    END
  END o[560]
  PIN o[561]
    DIRECTION OUTPUT ;
    USE SIGNAL ;
    PORT
      LAYER M5 ;
        RECT  47.904 0 47.928 0.084 ;
    END
  END o[561]
  PIN o[562]
    DIRECTION OUTPUT ;
    USE SIGNAL ;
    PORT
      LAYER M5 ;
        RECT  48 0 48.024 0.084 ;
    END
  END o[562]
  PIN o[563]
    DIRECTION OUTPUT ;
    USE SIGNAL ;
    PORT
      LAYER M5 ;
        RECT  48.096 0 48.12 0.084 ;
    END
  END o[563]
  PIN o[564]
    DIRECTION OUTPUT ;
    USE SIGNAL ;
    PORT
      LAYER M5 ;
        RECT  48.144 0 48.168 0.084 ;
    END
  END o[564]
  PIN o[565]
    DIRECTION OUTPUT ;
    USE SIGNAL ;
    PORT
      LAYER M5 ;
        RECT  48.24 0 48.264 0.084 ;
    END
  END o[565]
  PIN o[566]
    DIRECTION OUTPUT ;
    USE SIGNAL ;
    PORT
      LAYER M5 ;
        RECT  48.336 0 48.36 0.084 ;
    END
  END o[566]
  PIN o[567]
    DIRECTION OUTPUT ;
    USE SIGNAL ;
    PORT
      LAYER M5 ;
        RECT  48.384 0 48.408 0.084 ;
    END
  END o[567]
  PIN o[568]
    DIRECTION OUTPUT ;
    USE SIGNAL ;
    PORT
      LAYER M5 ;
        RECT  48.48 0 48.504 0.084 ;
    END
  END o[568]
  PIN o[569]
    DIRECTION OUTPUT ;
    USE SIGNAL ;
    PORT
      LAYER M5 ;
        RECT  48.576 0 48.6 0.084 ;
    END
  END o[569]
  PIN o[56]
    DIRECTION OUTPUT ;
    USE SIGNAL ;
    PORT
      LAYER M5 ;
        RECT  6.96 0 6.984 0.084 ;
    END
  END o[56]
  PIN o[570]
    DIRECTION OUTPUT ;
    USE SIGNAL ;
    PORT
      LAYER M5 ;
        RECT  48.624 0 48.648 0.084 ;
    END
  END o[570]
  PIN o[571]
    DIRECTION OUTPUT ;
    USE SIGNAL ;
    PORT
      LAYER M5 ;
        RECT  48.72 0 48.744 0.084 ;
    END
  END o[571]
  PIN o[572]
    DIRECTION OUTPUT ;
    USE SIGNAL ;
    PORT
      LAYER M5 ;
        RECT  48.816 0 48.84 0.084 ;
    END
  END o[572]
  PIN o[573]
    DIRECTION OUTPUT ;
    USE SIGNAL ;
    PORT
      LAYER M5 ;
        RECT  48.912 0 48.936 0.084 ;
    END
  END o[573]
  PIN o[574]
    DIRECTION OUTPUT ;
    USE SIGNAL ;
    PORT
      LAYER M5 ;
        RECT  48.96 0 48.984 0.084 ;
    END
  END o[574]
  PIN o[575]
    DIRECTION OUTPUT ;
    USE SIGNAL ;
    PORT
      LAYER M5 ;
        RECT  49.056 0 49.08 0.084 ;
    END
  END o[575]
  PIN o[576]
    DIRECTION OUTPUT ;
    USE SIGNAL ;
    PORT
      LAYER M3 ;
        RECT  49.14 0 49.158 0.038 ;
    END
  END o[576]
  PIN o[577]
    DIRECTION OUTPUT ;
    USE SIGNAL ;
    PORT
      LAYER M3 ;
        RECT  49.212 0 49.23 0.038 ;
    END
  END o[577]
  PIN o[578]
    DIRECTION OUTPUT ;
    USE SIGNAL ;
    PORT
      LAYER M3 ;
        RECT  49.284 0 49.302 0.038 ;
    END
  END o[578]
  PIN o[579]
    DIRECTION OUTPUT ;
    USE SIGNAL ;
    PORT
      LAYER M3 ;
        RECT  49.392 0 49.41 0.038 ;
    END
  END o[579]
  PIN o[57]
    DIRECTION OUTPUT ;
    USE SIGNAL ;
    PORT
      LAYER M5 ;
        RECT  7.056 0 7.08 0.084 ;
    END
  END o[57]
  PIN o[580]
    DIRECTION OUTPUT ;
    USE SIGNAL ;
    PORT
      LAYER M3 ;
        RECT  49.464 0 49.482 0.038 ;
    END
  END o[580]
  PIN o[581]
    DIRECTION OUTPUT ;
    USE SIGNAL ;
    PORT
      LAYER M3 ;
        RECT  49.536 0 49.554 0.038 ;
    END
  END o[581]
  PIN o[582]
    DIRECTION OUTPUT ;
    USE SIGNAL ;
    PORT
      LAYER M3 ;
        RECT  49.608 0 49.626 0.038 ;
    END
  END o[582]
  PIN o[583]
    DIRECTION OUTPUT ;
    USE SIGNAL ;
    PORT
      LAYER M3 ;
        RECT  49.716 0 49.734 0.038 ;
    END
  END o[583]
  PIN o[584]
    DIRECTION OUTPUT ;
    USE SIGNAL ;
    PORT
      LAYER M3 ;
        RECT  49.788 0 49.806 0.038 ;
    END
  END o[584]
  PIN o[585]
    DIRECTION OUTPUT ;
    USE SIGNAL ;
    PORT
      LAYER M3 ;
        RECT  49.86 0 49.878 0.038 ;
    END
  END o[585]
  PIN o[586]
    DIRECTION OUTPUT ;
    USE SIGNAL ;
    PORT
      LAYER M3 ;
        RECT  49.932 0 49.95 0.038 ;
    END
  END o[586]
  PIN o[587]
    DIRECTION OUTPUT ;
    USE SIGNAL ;
    PORT
      LAYER M3 ;
        RECT  50.04 0 50.058 0.038 ;
    END
  END o[587]
  PIN o[588]
    DIRECTION OUTPUT ;
    USE SIGNAL ;
    PORT
      LAYER M3 ;
        RECT  50.112 0 50.13 0.038 ;
    END
  END o[588]
  PIN o[589]
    DIRECTION OUTPUT ;
    USE SIGNAL ;
    PORT
      LAYER M3 ;
        RECT  50.184 0 50.202 0.038 ;
    END
  END o[589]
  PIN o[58]
    DIRECTION OUTPUT ;
    USE SIGNAL ;
    PORT
      LAYER M5 ;
        RECT  7.152 0 7.176 0.084 ;
    END
  END o[58]
  PIN o[590]
    DIRECTION OUTPUT ;
    USE SIGNAL ;
    PORT
      LAYER M3 ;
        RECT  50.256 0 50.274 0.038 ;
    END
  END o[590]
  PIN o[591]
    DIRECTION OUTPUT ;
    USE SIGNAL ;
    PORT
      LAYER M3 ;
        RECT  50.364 0 50.382 0.038 ;
    END
  END o[591]
  PIN o[59]
    DIRECTION OUTPUT ;
    USE SIGNAL ;
    PORT
      LAYER M5 ;
        RECT  7.2 0 7.224 0.084 ;
    END
  END o[59]
  PIN o[5]
    DIRECTION OUTPUT ;
    USE SIGNAL ;
    PORT
      LAYER M3 ;
        RECT  2.844 0 2.862 0.038 ;
    END
  END o[5]
  PIN o[60]
    DIRECTION OUTPUT ;
    USE SIGNAL ;
    PORT
      LAYER M5 ;
        RECT  7.296 0 7.32 0.084 ;
    END
  END o[60]
  PIN o[61]
    DIRECTION OUTPUT ;
    USE SIGNAL ;
    PORT
      LAYER M5 ;
        RECT  7.392 0 7.416 0.084 ;
    END
  END o[61]
  PIN o[62]
    DIRECTION OUTPUT ;
    USE SIGNAL ;
    PORT
      LAYER M5 ;
        RECT  7.44 0 7.464 0.084 ;
    END
  END o[62]
  PIN o[63]
    DIRECTION OUTPUT ;
    USE SIGNAL ;
    PORT
      LAYER M5 ;
        RECT  7.536 0 7.56 0.084 ;
    END
  END o[63]
  PIN o[64]
    DIRECTION OUTPUT ;
    USE SIGNAL ;
    PORT
      LAYER M3 ;
        RECT  7.632 0 7.65 0.038 ;
    END
  END o[64]
  PIN o[65]
    DIRECTION OUTPUT ;
    USE SIGNAL ;
    PORT
      LAYER M3 ;
        RECT  7.704 0 7.722 0.038 ;
    END
  END o[65]
  PIN o[66]
    DIRECTION OUTPUT ;
    USE SIGNAL ;
    PORT
      LAYER M3 ;
        RECT  7.776 0 7.794 0.038 ;
    END
  END o[66]
  PIN o[67]
    DIRECTION OUTPUT ;
    USE SIGNAL ;
    PORT
      LAYER M3 ;
        RECT  7.848 0 7.866 0.038 ;
    END
  END o[67]
  PIN o[68]
    DIRECTION OUTPUT ;
    USE SIGNAL ;
    PORT
      LAYER M3 ;
        RECT  7.956 0 7.974 0.038 ;
    END
  END o[68]
  PIN o[69]
    DIRECTION OUTPUT ;
    USE SIGNAL ;
    PORT
      LAYER M3 ;
        RECT  8.028 0 8.046 0.038 ;
    END
  END o[69]
  PIN o[6]
    DIRECTION OUTPUT ;
    USE SIGNAL ;
    PORT
      LAYER M3 ;
        RECT  2.916 0 2.934 0.038 ;
    END
  END o[6]
  PIN o[70]
    DIRECTION OUTPUT ;
    USE SIGNAL ;
    PORT
      LAYER M3 ;
        RECT  8.1 0 8.118 0.038 ;
    END
  END o[70]
  PIN o[71]
    DIRECTION OUTPUT ;
    USE SIGNAL ;
    PORT
      LAYER M3 ;
        RECT  8.172 0 8.19 0.038 ;
    END
  END o[71]
  PIN o[72]
    DIRECTION OUTPUT ;
    USE SIGNAL ;
    PORT
      LAYER M3 ;
        RECT  8.28 0 8.298 0.038 ;
    END
  END o[72]
  PIN o[73]
    DIRECTION OUTPUT ;
    USE SIGNAL ;
    PORT
      LAYER M3 ;
        RECT  8.352 0 8.37 0.038 ;
    END
  END o[73]
  PIN o[74]
    DIRECTION OUTPUT ;
    USE SIGNAL ;
    PORT
      LAYER M3 ;
        RECT  8.424 0 8.442 0.038 ;
    END
  END o[74]
  PIN o[75]
    DIRECTION OUTPUT ;
    USE SIGNAL ;
    PORT
      LAYER M3 ;
        RECT  8.496 0 8.514 0.038 ;
    END
  END o[75]
  PIN o[76]
    DIRECTION OUTPUT ;
    USE SIGNAL ;
    PORT
      LAYER M3 ;
        RECT  8.604 0 8.622 0.038 ;
    END
  END o[76]
  PIN o[77]
    DIRECTION OUTPUT ;
    USE SIGNAL ;
    PORT
      LAYER M3 ;
        RECT  8.676 0 8.694 0.038 ;
    END
  END o[77]
  PIN o[78]
    DIRECTION OUTPUT ;
    USE SIGNAL ;
    PORT
      LAYER M3 ;
        RECT  8.748 0 8.766 0.038 ;
    END
  END o[78]
  PIN o[79]
    DIRECTION OUTPUT ;
    USE SIGNAL ;
    PORT
      LAYER M3 ;
        RECT  8.82 0 8.838 0.038 ;
    END
  END o[79]
  PIN o[7]
    DIRECTION OUTPUT ;
    USE SIGNAL ;
    PORT
      LAYER M3 ;
        RECT  2.988 0 3.006 0.038 ;
    END
  END o[7]
  PIN o[80]
    DIRECTION OUTPUT ;
    USE SIGNAL ;
    PORT
      LAYER M3 ;
        RECT  8.928 0 8.946 0.038 ;
    END
  END o[80]
  PIN o[81]
    DIRECTION OUTPUT ;
    USE SIGNAL ;
    PORT
      LAYER M3 ;
        RECT  9 0 9.018 0.038 ;
    END
  END o[81]
  PIN o[82]
    DIRECTION OUTPUT ;
    USE SIGNAL ;
    PORT
      LAYER M3 ;
        RECT  9.072 0 9.09 0.038 ;
    END
  END o[82]
  PIN o[83]
    DIRECTION OUTPUT ;
    USE SIGNAL ;
    PORT
      LAYER M3 ;
        RECT  9.144 0 9.162 0.038 ;
    END
  END o[83]
  PIN o[84]
    DIRECTION OUTPUT ;
    USE SIGNAL ;
    PORT
      LAYER M3 ;
        RECT  9.252 0 9.27 0.038 ;
    END
  END o[84]
  PIN o[85]
    DIRECTION OUTPUT ;
    USE SIGNAL ;
    PORT
      LAYER M3 ;
        RECT  9.324 0 9.342 0.038 ;
    END
  END o[85]
  PIN o[86]
    DIRECTION OUTPUT ;
    USE SIGNAL ;
    PORT
      LAYER M3 ;
        RECT  9.396 0 9.414 0.038 ;
    END
  END o[86]
  PIN o[87]
    DIRECTION OUTPUT ;
    USE SIGNAL ;
    PORT
      LAYER M3 ;
        RECT  9.504 0 9.522 0.038 ;
    END
  END o[87]
  PIN o[88]
    DIRECTION OUTPUT ;
    USE SIGNAL ;
    PORT
      LAYER M3 ;
        RECT  9.576 0 9.594 0.038 ;
    END
  END o[88]
  PIN o[89]
    DIRECTION OUTPUT ;
    USE SIGNAL ;
    PORT
      LAYER M3 ;
        RECT  9.648 0 9.666 0.038 ;
    END
  END o[89]
  PIN o[8]
    DIRECTION OUTPUT ;
    USE SIGNAL ;
    PORT
      LAYER M3 ;
        RECT  3.096 0 3.114 0.038 ;
    END
  END o[8]
  PIN o[90]
    DIRECTION OUTPUT ;
    USE SIGNAL ;
    PORT
      LAYER M3 ;
        RECT  9.72 0 9.738 0.038 ;
    END
  END o[90]
  PIN o[91]
    DIRECTION OUTPUT ;
    USE SIGNAL ;
    PORT
      LAYER M3 ;
        RECT  9.828 0 9.846 0.038 ;
    END
  END o[91]
  PIN o[92]
    DIRECTION OUTPUT ;
    USE SIGNAL ;
    PORT
      LAYER M3 ;
        RECT  9.9 0 9.918 0.038 ;
    END
  END o[92]
  PIN o[93]
    DIRECTION OUTPUT ;
    USE SIGNAL ;
    PORT
      LAYER M3 ;
        RECT  9.972 0 9.99 0.038 ;
    END
  END o[93]
  PIN o[94]
    DIRECTION OUTPUT ;
    USE SIGNAL ;
    PORT
      LAYER M3 ;
        RECT  10.044 0 10.062 0.038 ;
    END
  END o[94]
  PIN o[95]
    DIRECTION OUTPUT ;
    USE SIGNAL ;
    PORT
      LAYER M3 ;
        RECT  10.152 0 10.17 0.038 ;
    END
  END o[95]
  PIN o[96]
    DIRECTION OUTPUT ;
    USE SIGNAL ;
    PORT
      LAYER M5 ;
        RECT  10.224 0 10.248 0.084 ;
    END
  END o[96]
  PIN o[97]
    DIRECTION OUTPUT ;
    USE SIGNAL ;
    PORT
      LAYER M5 ;
        RECT  10.272 0 10.296 0.084 ;
    END
  END o[97]
  PIN o[98]
    DIRECTION OUTPUT ;
    USE SIGNAL ;
    PORT
      LAYER M5 ;
        RECT  10.368 0 10.392 0.084 ;
    END
  END o[98]
  PIN o[99]
    DIRECTION OUTPUT ;
    USE SIGNAL ;
    PORT
      LAYER M5 ;
        RECT  10.464 0 10.488 0.084 ;
    END
  END o[99]
  PIN o[9]
    DIRECTION OUTPUT ;
    USE SIGNAL ;
    PORT
      LAYER M3 ;
        RECT  3.168 0 3.186 0.038 ;
    END
  END o[9]
  PIN o_rf[0]
    DIRECTION OUTPUT ;
    USE SIGNAL ;
    PORT
      LAYER M3 ;
        RECT  50.724 0 50.742 0.038 ;
    END
  END o_rf[0]
  PIN o_rf[1]
    DIRECTION OUTPUT ;
    USE SIGNAL ;
    PORT
      LAYER M3 ;
        RECT  50.976 0 50.994 0.038 ;
    END
  END o_rf[1]
  PIN o_rf[2]
    DIRECTION OUTPUT ;
    USE SIGNAL ;
    PORT
      LAYER M3 ;
        RECT  51.228 0 51.246 0.038 ;
    END
  END o_rf[2]
  PIN o_rf[3]
    DIRECTION OUTPUT ;
    USE SIGNAL ;
    PORT
      LAYER M3 ;
        RECT  51.48 0 51.498 0.038 ;
    END
  END o_rf[3]
  PIN rn_o[0]
    DIRECTION OUTPUT ;
    USE SIGNAL ;
    PORT
      LAYER M4 ;
        RECT  53.916 6.48 54 6.504 ;
    END
    PORT
      LAYER M4 ;
        RECT  52.981 6.48 53.964 6.504 ;
    END
  END rn_o[0]
  PIN rn_o[1]
    DIRECTION OUTPUT ;
    USE SIGNAL ;
    PORT
      LAYER M4 ;
        RECT  53.916 19.44 54 19.464 ;
    END
    PORT
      LAYER M4 ;
        RECT  52.981 19.44 53.964 19.464 ;
    END
  END rn_o[1]
  PIN rni
    DIRECTION INPUT ;
    USE SIGNAL ;
    PORT
      LAYER M4 ;
        RECT  0 19.44 0.084 19.464 ;
    END
    PORT
      LAYER M4 ;
        RECT  0.06 19.44 2.408 19.464 ;
    END
  END rni
  PIN VDD
    DIRECTION INOUT ;
    USE POWER ;
    PORT
      LAYER M5 ;
        RECT  51.192 2.151 51.312 23.769 ;
        RECT  45.792 2.151 45.912 23.769 ;
        RECT  40.392 2.151 40.512 23.769 ;
        RECT  34.992 2.151 35.112 23.769 ;
        RECT  29.592 2.151 29.712 23.769 ;
        RECT  24.192 2.151 24.312 23.769 ;
        RECT  18.792 2.151 18.912 23.769 ;
        RECT  13.392 2.151 13.512 23.769 ;
        RECT  7.992 2.151 8.112 23.769 ;
        RECT  2.592 2.151 2.712 23.769 ;
    END
  END VDD
  PIN VSS
    DIRECTION INOUT ;
    USE GROUND ;
    PORT
      LAYER M5 ;
        RECT  51 2.137 51.12 23.783 ;
        RECT  45.6 2.137 45.72 23.783 ;
        RECT  40.2 2.137 40.32 23.783 ;
        RECT  34.8 2.137 34.92 23.783 ;
        RECT  29.4 2.137 29.52 23.783 ;
        RECT  24 2.137 24.12 23.783 ;
        RECT  18.6 2.137 18.72 23.783 ;
        RECT  13.2 2.137 13.32 23.783 ;
        RECT  7.8 2.137 7.92 23.783 ;
        RECT  2.4 2.137 2.52 23.783 ;
    END
  END VSS
  # OT_OBS_CLOSED layer=M5 d_um=1.536 added=153
  OBS
    LAYER RVTN ;
     RECT  2.16 2.16 51.84 2.295 ;
     RECT  2.16 2.565 51.84 2.835 ;
     RECT  2.16 3.105 51.84 3.375 ;
     RECT  2.16 3.645 51.84 3.915 ;
     RECT  2.16 4.185 51.84 4.455 ;
     RECT  2.16 4.725 51.84 4.995 ;
     RECT  2.16 5.265 51.84 5.535 ;
     RECT  2.16 5.805 51.84 6.075 ;
     RECT  2.16 6.345 51.84 6.615 ;
     RECT  2.16 6.885 51.84 7.155 ;
     RECT  2.16 7.425 51.84 7.695 ;
     RECT  2.16 7.965 51.84 8.235 ;
     RECT  2.16 8.505 51.84 8.775 ;
     RECT  2.16 9.045 51.84 9.315 ;
     RECT  2.16 9.585 51.84 9.855 ;
     RECT  2.16 10.125 51.84 10.395 ;
     RECT  2.16 10.665 51.84 10.935 ;
     RECT  2.16 11.205 51.84 11.475 ;
     RECT  2.16 11.745 51.84 12.015 ;
     RECT  2.16 12.285 51.84 12.555 ;
     RECT  2.16 12.825 51.84 13.095 ;
     RECT  2.16 13.365 51.84 13.635 ;
     RECT  2.16 13.905 51.84 14.175 ;
     RECT  2.16 14.445 51.84 14.715 ;
     RECT  2.16 14.985 51.84 15.255 ;
     RECT  2.16 15.525 51.84 15.795 ;
     RECT  2.16 16.065 51.84 16.335 ;
     RECT  2.16 16.605 51.84 16.875 ;
     RECT  2.16 17.145 51.84 17.415 ;
     RECT  2.16 17.685 51.84 17.955 ;
     RECT  2.16 18.225 51.84 18.495 ;
     RECT  2.16 18.765 51.84 19.035 ;
     RECT  2.16 19.305 51.84 19.575 ;
     RECT  2.16 19.845 51.84 20.115 ;
     RECT  2.16 20.385 51.84 20.655 ;
     RECT  2.16 20.925 51.84 21.195 ;
     RECT  2.16 21.465 51.84 21.735 ;
     RECT  2.16 22.005 51.84 22.275 ;
     RECT  2.16 22.545 51.84 22.815 ;
     RECT  2.16 23.085 51.84 23.355 ;
     RECT  2.16 23.625 51.84 23.76 ;
    LAYER RVTP ;
     RECT  2.16 2.295 51.84 2.565 ;
     RECT  2.16 2.835 51.84 3.105 ;
     RECT  2.16 3.375 51.84 3.645 ;
     RECT  2.16 3.915 51.84 4.185 ;
     RECT  2.16 4.455 51.84 4.725 ;
     RECT  2.16 4.995 51.84 5.265 ;
     RECT  2.16 5.535 51.84 5.805 ;
     RECT  2.16 6.075 51.84 6.345 ;
     RECT  2.16 6.615 51.84 6.885 ;
     RECT  2.16 7.155 51.84 7.425 ;
     RECT  2.16 7.695 51.84 7.965 ;
     RECT  2.16 8.235 51.84 8.505 ;
     RECT  2.16 8.775 51.84 9.045 ;
     RECT  2.16 9.315 51.84 9.585 ;
     RECT  2.16 9.855 51.84 10.125 ;
     RECT  2.16 10.395 51.84 10.665 ;
     RECT  2.16 10.935 51.84 11.205 ;
     RECT  2.16 11.475 51.84 11.745 ;
     RECT  2.16 12.015 51.84 12.285 ;
     RECT  2.16 12.555 51.84 12.825 ;
     RECT  2.16 13.095 51.84 13.365 ;
     RECT  2.16 13.635 51.84 13.905 ;
     RECT  2.16 14.175 51.84 14.445 ;
     RECT  2.16 14.715 51.84 14.985 ;
     RECT  2.16 15.255 51.84 15.525 ;
     RECT  2.16 15.795 51.84 16.065 ;
     RECT  2.16 16.335 51.84 16.605 ;
     RECT  2.16 16.875 51.84 17.145 ;
     RECT  2.16 17.415 51.84 17.685 ;
     RECT  2.16 17.955 51.84 18.225 ;
     RECT  2.16 18.495 51.84 18.765 ;
     RECT  2.16 19.035 51.84 19.305 ;
     RECT  2.16 19.575 51.84 19.845 ;
     RECT  2.16 20.115 51.84 20.385 ;
     RECT  2.16 20.655 51.84 20.925 ;
     RECT  2.16 21.195 51.84 21.465 ;
     RECT  2.16 21.735 51.84 22.005 ;
     RECT  2.16 22.275 51.84 22.545 ;
     RECT  2.16 22.815 51.84 23.085 ;
     RECT  2.16 23.355 51.84 23.625 ;
    LAYER M1 ;
     RECT  2.16 2.151 51.84 23.769 ;
    LAYER M2 ;
     RECT  2.16 2.151 2.335 23.769 ;
     RECT  2.299 25.056 2.371 25.074 ;
     RECT  2.371 24.984 2.399 25.812 ;
     RECT  2.399 24.984 2.471 25.002 ;
     RECT  2.335 2.151 2.543 23.85 ;
     RECT  2.399 25.794 2.551 25.812 ;
     RECT  2.371 0.036 2.587 0.054 ;
     RECT  2.551 25.794 2.615 25.884 ;
     RECT  2.587 0.036 2.659 0.126 ;
     RECT  2.615 25.866 2.687 25.884 ;
     RECT  2.659 0.036 2.867 0.162 ;
     RECT  2.867 0.036 3.299 0.126 ;
     RECT  3.299 0.036 3.947 0.054 ;
     RECT  2.543 2.151 3.955 23.769 ;
     RECT  3.955 2.106 4.135 23.769 ;
     RECT  4.135 1.728 4.451 23.769 ;
     RECT  4.451 2.106 4.703 23.769 ;
     RECT  4.603 0.261 4.711 0.279 ;
     RECT  4.711 0.036 4.811 0.279 ;
     RECT  4.811 0.036 4.955 0.234 ;
     RECT  4.955 0.036 5.027 0.162 ;
     RECT  5.027 0.036 5.099 0.054 ;
     RECT  4.855 25.056 5.099 25.074 ;
     RECT  4.703 2.151 7.447 23.769 ;
     RECT  7.519 0.108 7.555 0.126 ;
     RECT  7.447 2.151 7.591 23.958 ;
     RECT  7.591 2.151 7.727 24.534 ;
     RECT  7.735 25.866 7.871 25.884 ;
     RECT  7.727 24.516 8.051 24.534 ;
     RECT  7.727 2.151 8.671 23.769 ;
     RECT  7.555 0.036 9.571 0.126 ;
     RECT  8.671 1.728 9.931 23.769 ;
     RECT  9.931 1.224 10.003 23.769 ;
     RECT  9.571 0.036 10.039 0.198 ;
     RECT  10.003 1.152 10.067 23.769 ;
     RECT  10.067 1.152 10.103 1.242 ;
     RECT  10.039 0.036 10.175 0.234 ;
     RECT  10.103 1.224 10.211 1.242 ;
     RECT  10.175 0.036 10.247 0.054 ;
     RECT  10.975 1.152 11.183 1.17 ;
     RECT  12.127 1.224 12.235 1.242 ;
     RECT  12.235 1.152 12.299 1.242 ;
     RECT  12.703 0.108 12.739 0.126 ;
     RECT  12.299 1.152 13.091 1.17 ;
     RECT  12.739 0.036 13.099 0.126 ;
     RECT  13.099 0.036 13.135 0.162 ;
     RECT  10.067 2.151 13.207 23.769 ;
     RECT  13.171 25.866 13.487 25.884 ;
     RECT  13.207 24.984 13.531 25.002 ;
     RECT  13.531 24.984 13.559 25.074 ;
     RECT  13.135 0.036 13.595 0.234 ;
     RECT  13.207 1.728 13.667 23.769 ;
     RECT  13.559 25.02 13.955 25.074 ;
     RECT  13.955 25.056 14.323 25.074 ;
     RECT  13.819 1.152 14.611 1.17 ;
     RECT  14.323 25.056 14.675 25.119 ;
     RECT  14.611 1.152 14.711 1.242 ;
     RECT  14.675 25.101 14.855 25.119 ;
     RECT  13.595 0.036 14.927 0.198 ;
     RECT  14.927 0.036 15.251 0.126 ;
     RECT  15.251 0.036 15.323 0.054 ;
     RECT  13.667 2.151 15.799 23.769 ;
     RECT  14.711 1.152 16.331 1.17 ;
     RECT  15.799 2.106 16.475 23.769 ;
     RECT  18.247 0.036 18.319 0.054 ;
     RECT  18.319 0.036 18.571 0.126 ;
     RECT  16.475 2.151 18.895 23.769 ;
     RECT  18.895 1.728 19.219 23.769 ;
     RECT  19.219 1.728 19.247 23.814 ;
     RECT  19.247 1.8 19.319 23.814 ;
     RECT  18.535 25.866 19.319 25.884 ;
     RECT  18.571 0.036 19.939 0.198 ;
     RECT  19.939 0.036 20.011 0.279 ;
     RECT  20.011 0.036 20.327 0.324 ;
     RECT  20.327 0.036 20.363 0.126 ;
     RECT  20.363 0.036 20.759 0.054 ;
     RECT  23.071 0.036 23.179 0.054 ;
     RECT  22.603 1.152 23.683 1.17 ;
     RECT  19.319 2.151 23.827 23.769 ;
     RECT  23.683 1.152 24.007 1.242 ;
     RECT  23.827 2.106 24.007 23.769 ;
     RECT  24.007 1.152 24.251 23.85 ;
     RECT  23.971 25.866 24.251 25.884 ;
     RECT  24.079 25.056 24.467 25.074 ;
     RECT  24.251 1.152 24.755 23.769 ;
     RECT  24.755 1.152 24.935 1.242 ;
     RECT  24.935 1.224 25.043 1.242 ;
     RECT  23.179 0.036 25.051 0.126 ;
     RECT  25.051 0.036 25.195 0.162 ;
     RECT  25.123 25.794 25.195 25.812 ;
     RECT  25.195 25.794 25.223 25.884 ;
     RECT  25.223 25.866 25.367 25.884 ;
     RECT  24.755 2.151 25.519 23.769 ;
     RECT  25.195 0.036 25.583 0.234 ;
     RECT  25.583 0.216 25.835 0.234 ;
     RECT  25.519 2.106 25.871 23.769 ;
     RECT  25.871 2.151 27.247 23.769 ;
     RECT  27.247 2.106 27.779 23.769 ;
     RECT  27.779 2.151 29.227 23.769 ;
     RECT  29.227 2.151 29.299 23.85 ;
     RECT  28.363 0.036 29.335 0.054 ;
     RECT  29.299 2.151 29.543 23.922 ;
     RECT  29.335 0.036 29.587 0.126 ;
     RECT  29.587 0.036 29.659 0.162 ;
     RECT  29.659 0.036 29.867 0.234 ;
     RECT  29.867 0.036 30.227 0.162 ;
     RECT  29.543 2.151 30.487 23.769 ;
     RECT  30.487 1.728 30.731 23.769 ;
     RECT  30.227 0.036 31.091 0.054 ;
     RECT  30.731 2.151 33.223 23.769 ;
     RECT  33.655 0.036 33.727 0.054 ;
     RECT  33.223 2.106 33.799 23.769 ;
     RECT  33.727 0.036 34.051 0.09 ;
     RECT  34.051 0.036 34.195 0.126 ;
     RECT  33.799 1.728 34.619 23.769 ;
     RECT  34.619 2.151 34.735 23.769 ;
     RECT  34.843 25.794 34.879 25.812 ;
     RECT  34.735 2.151 34.907 24.192 ;
     RECT  34.195 0.036 34.951 0.162 ;
     RECT  34.879 25.794 34.979 25.884 ;
     RECT  34.951 0.036 35.167 0.198 ;
     RECT  34.907 2.151 35.303 23.922 ;
     RECT  35.303 2.151 35.599 23.769 ;
     RECT  35.167 0.036 35.923 0.279 ;
     RECT  35.599 2.106 35.959 23.769 ;
     RECT  35.923 0.036 36.095 0.324 ;
     RECT  36.095 0.036 36.203 0.198 ;
     RECT  36.203 0.18 36.275 0.198 ;
     RECT  35.959 1.728 36.455 23.769 ;
     RECT  36.455 2.151 38.983 23.769 ;
     RECT  38.839 0.036 39.163 0.054 ;
     RECT  38.983 1.728 39.595 23.769 ;
     RECT  39.595 1.728 39.667 23.994 ;
     RECT  39.667 1.152 40.091 23.994 ;
     RECT  40.091 1.152 40.307 23.85 ;
     RECT  39.163 0.036 40.883 0.126 ;
     RECT  40.387 25.101 40.955 25.119 ;
     RECT  40.207 25.866 40.955 25.884 ;
     RECT  40.883 0.036 40.991 0.054 ;
     RECT  40.307 1.152 40.991 23.769 ;
     RECT  40.991 1.728 41.387 23.769 ;
     RECT  41.387 2.106 42.611 23.769 ;
     RECT  44.599 0.261 44.671 0.279 ;
     RECT  42.611 2.151 44.743 23.769 ;
     RECT  44.671 0.108 44.807 0.279 ;
     RECT  44.807 0.108 44.815 0.198 ;
     RECT  44.743 1.728 45.211 23.769 ;
     RECT  45.211 1.152 45.311 23.769 ;
     RECT  45.311 1.728 45.419 23.769 ;
     RECT  45.419 1.8 45.491 23.769 ;
     RECT  44.815 0.036 45.643 0.198 ;
     RECT  45.823 25.866 45.959 25.884 ;
     RECT  45.643 0.036 45.995 0.324 ;
     RECT  45.995 0.036 46.283 0.279 ;
     RECT  46.219 1.152 46.291 1.17 ;
     RECT  45.491 2.151 46.291 23.769 ;
     RECT  45.643 25.101 46.291 25.119 ;
     RECT  46.291 1.152 46.499 23.769 ;
     RECT  46.499 1.152 46.535 1.242 ;
     RECT  46.291 25.056 46.535 25.119 ;
     RECT  46.283 0.036 46.571 0.054 ;
     RECT  46.535 1.224 46.571 1.242 ;
     RECT  46.535 25.101 46.571 25.119 ;
     RECT  46.499 2.106 47.147 23.769 ;
     RECT  47.299 1.152 47.335 1.17 ;
     RECT  47.335 1.152 47.435 1.242 ;
     RECT  47.435 1.224 47.471 1.242 ;
     RECT  47.147 2.151 49.531 23.769 ;
     RECT  49.063 0.036 49.855 0.054 ;
     RECT  49.531 2.106 49.927 23.769 ;
     RECT  49.855 0.036 50.035 0.126 ;
     RECT  50.035 0.036 50.135 0.198 ;
     RECT  50.287 25.866 50.387 25.884 ;
     RECT  50.135 0.036 50.495 0.09 ;
     RECT  50.495 0.036 50.531 0.054 ;
     RECT  49.927 1.728 50.567 23.769 ;
     RECT  51.151 25.866 51.251 25.884 ;
     RECT  50.567 2.151 51.84 23.769 ;
     RECT  51.84 7.596 53.015 7.614 ;
     RECT  51.84 19.476 53.015 19.494 ;
    LAYER M3 ;
     RECT  2.448 0.012 4.95 0.031 ;
     RECT  7.632 0.012 10.17 0.031 ;
     RECT  12.816 0.012 15.354 0.031 ;
     RECT  18 0.012 20.538 0.031 ;
     RECT  23.184 0.012 25.722 0.031 ;
     RECT  28.368 0.012 30.906 0.031 ;
     RECT  33.552 0.012 36.09 0.031 ;
     RECT  43.956 0.012 46.494 0.031 ;
     RECT  49.14 0.012 51.498 0.031 ;
     RECT  2.376 0.031 5.094 0.091 ;
     RECT  7.56 0.031 10.242 0.091 ;
     RECT  12.744 0.031 15.354 0.091 ;
     RECT  18 0.031 20.754 0.091 ;
     RECT  23.076 0.031 25.722 0.091 ;
     RECT  28.368 0.031 31.086 0.091 ;
     RECT  38.772 0.012 41.274 0.091 ;
     RECT  43.956 0.031 46.566 0.091 ;
     RECT  6.84 0.091 10.242 0.139 ;
     RECT  10.98 0.091 10.998 0.139 ;
     RECT  12.348 0.091 15.354 0.139 ;
     RECT  28.008 0.091 31.086 0.139 ;
     RECT  32.796 0.091 32.814 0.139 ;
     RECT  37.08 0.091 37.098 0.139 ;
     RECT  38.772 0.091 41.958 0.139 ;
     RECT  43.92 0.091 46.566 0.139 ;
     RECT  47.592 0.091 47.61 0.139 ;
     RECT  33.552 0.031 36.198 0.175 ;
     RECT  6.732 0.139 10.998 0.187 ;
     RECT  26.568 0.091 26.586 0.187 ;
     RECT  38.7 0.139 41.958 0.187 ;
     RECT  22.464 0.091 25.722 0.211 ;
     RECT  26.532 0.187 26.586 0.211 ;
     RECT  12.24 0.139 15.354 0.235 ;
     RECT  17.964 0.091 21.402 0.235 ;
     RECT  43.344 0.139 46.566 0.235 ;
     RECT  32.652 0.139 32.814 0.283 ;
     RECT  33.552 0.175 36.27 0.283 ;
     RECT  12.168 0.235 15.354 0.331 ;
     RECT  32.652 0.283 36.27 0.427 ;
     RECT  37.08 0.139 37.17 0.427 ;
     RECT  12.132 0.331 15.354 0.523 ;
     RECT  16.092 0.427 16.11 0.523 ;
     RECT  28.008 0.139 31.698 0.523 ;
     RECT  38.52 0.187 42.03 0.523 ;
     RECT  42.876 0.235 46.566 0.523 ;
     RECT  47.304 0.139 48.15 0.523 ;
     RECT  17.856 0.235 21.402 0.571 ;
     RECT  22.464 0.211 26.586 0.571 ;
     RECT  27.972 0.523 31.698 0.571 ;
     RECT  17.856 0.571 26.586 1.099 ;
     RECT  27.576 0.571 31.698 1.099 ;
     RECT  6.732 0.187 11.034 1.147 ;
     RECT  12.132 0.523 16.11 1.147 ;
     RECT  17.856 1.099 31.698 1.147 ;
     RECT  32.652 0.427 37.17 1.147 ;
     RECT  38.52 0.523 48.15 1.147 ;
     RECT  49.068 0.031 51.498 1.147 ;
     RECT  17.532 1.147 31.698 1.675 ;
     RECT  32.652 1.147 48.15 1.675 ;
     RECT  2.376 0.091 5.814 1.723 ;
     RECT  6.732 1.147 11.178 1.723 ;
     RECT  12.132 1.147 16.326 1.723 ;
     RECT  17.532 1.675 31.734 1.723 ;
     RECT  32.616 1.675 48.15 1.723 ;
     RECT  48.924 1.147 51.498 1.723 ;
     RECT  2.376 1.723 51.498 4.379 ;
     RECT  2.376 4.379 51.462 6.547 ;
     RECT  2.376 6.547 51.642 6.848 ;
     RECT  2.376 6.848 51.678 7.619 ;
     RECT  52.992 6.475 53.01 7.619 ;
     RECT  2.415 7.619 51.678 8.311 ;
     RECT  2.415 8.311 51.714 8.735 ;
     RECT  2.415 8.735 51.678 10.561 ;
     RECT  2.34 10.561 51.678 11.245 ;
     RECT  2.34 11.245 51.714 12.209 ;
     RECT  2.34 12.209 51.678 12.253 ;
     RECT  2.304 12.253 51.678 12.479 ;
     RECT  2.304 12.479 51.642 13.559 ;
     RECT  2.304 13.559 51.534 14.791 ;
     RECT  2.304 14.791 51.678 15.025 ;
     RECT  2.304 15.025 51.714 16.529 ;
     RECT  2.304 16.529 51.678 19.387 ;
     RECT  2.304 19.387 51.714 19.435 ;
     RECT  52.992 19.435 53.01 19.499 ;
     RECT  2.268 19.435 51.714 19.769 ;
     RECT  2.268 19.769 51.678 19.805 ;
     RECT  2.304 19.805 51.678 21.299 ;
     RECT  2.34 21.299 51.678 22.469 ;
     RECT  2.34 22.469 51.57 23.009 ;
     RECT  2.34 23.009 51.498 23.125 ;
     RECT  2.304 23.125 51.498 23.933 ;
     RECT  6.3 23.933 10.242 23.963 ;
     RECT  22.14 23.933 26.19 24.029 ;
     RECT  7.596 23.963 10.242 24.509 ;
     RECT  7.596 24.509 10.17 24.539 ;
     RECT  10.98 23.933 21.33 24.557 ;
     RECT  27.072 23.933 31.878 24.557 ;
     RECT  37.656 23.933 41.346 24.557 ;
     RECT  10.98 24.557 11.934 24.605 ;
     RECT  32.976 23.933 36.666 24.605 ;
     RECT  37.908 24.557 41.346 24.605 ;
     RECT  23.184 24.029 26.19 25.037 ;
     RECT  2.304 23.933 5.526 25.079 ;
     RECT  10.98 24.605 11.286 25.085 ;
     RECT  12.672 24.557 17.082 25.085 ;
     RECT  18 24.557 21.33 25.085 ;
     RECT  32.976 24.605 36.45 25.085 ;
     RECT  12.672 25.085 16.434 25.133 ;
     RECT  23.184 25.037 26.154 25.133 ;
     RECT  27.756 24.557 31.878 25.133 ;
     RECT  42.084 23.933 43.218 25.133 ;
     RECT  47.736 23.933 48.258 25.133 ;
     RECT  48.996 23.933 51.498 25.133 ;
     RECT  6.3 23.963 6.75 25.181 ;
     RECT  22.14 24.029 22.266 25.181 ;
     RECT  37.908 24.605 41.274 25.229 ;
     RECT  12.816 25.133 16.434 25.517 ;
     RECT  31.86 25.133 31.878 25.565 ;
     RECT  22.248 25.181 22.266 25.675 ;
     RECT  23.184 25.133 25.722 25.675 ;
     RECT  33.552 25.085 36.45 25.675 ;
     RECT  6.732 25.181 6.75 25.757 ;
     RECT  12.816 25.517 16.038 25.757 ;
     RECT  22.248 25.675 25.722 25.757 ;
     RECT  43.956 23.933 46.854 25.757 ;
     RECT  2.376 25.079 5.526 25.805 ;
     RECT  10.98 25.085 10.998 25.805 ;
     RECT  18 25.085 21.114 25.805 ;
     RECT  22.932 25.757 25.722 25.805 ;
     RECT  33.552 25.675 36.666 25.805 ;
     RECT  38.088 25.229 41.274 25.805 ;
     RECT  2.376 25.805 4.95 25.817 ;
     RECT  2.448 25.817 4.95 25.901 ;
     RECT  7.632 24.539 10.17 25.901 ;
     RECT  12.816 25.757 15.354 25.901 ;
     RECT  18 25.805 20.538 25.901 ;
     RECT  23.184 25.805 25.722 25.901 ;
     RECT  28.368 25.133 30.906 25.901 ;
     RECT  33.552 25.805 36.09 25.901 ;
     RECT  38.772 25.805 41.274 25.901 ;
     RECT  43.956 25.757 46.494 25.901 ;
     RECT  49.14 25.133 51.498 25.901 ;
    LAYER M4 ;
     RECT  0.181 12.576 2.408 12.6 ;
     RECT  2.293 20.976 2.408 21.96 ;
     RECT  2.408 2.148 2.512 23.772 ;
     RECT  2.512 2.418 2.704 23.502 ;
     RECT  2.704 19.44 2.88 21.72 ;
     RECT  2.833 0.048 2.981 0.072 ;
     RECT  2.704 16.8 3.413 18.216 ;
     RECT  3.413 16.8 3.557 18.168 ;
     RECT  2.88 19.92 3.557 21.72 ;
     RECT  2.704 9.072 3.683 9.096 ;
     RECT  2.704 5.952 3.733 6.264 ;
     RECT  2.704 7.296 3.733 7.32 ;
     RECT  2.704 11.856 3.769 14.952 ;
     RECT  3.733 5.376 3.805 7.32 ;
     RECT  3.769 11.856 3.841 15 ;
     RECT  3.841 11.856 3.845 15.192 ;
     RECT  3.845 13.68 3.881 15.192 ;
     RECT  3.805 5.376 3.889 7.416 ;
     RECT  3.889 5.376 4.019 7.32 ;
     RECT  4.019 5.376 4.025 6.888 ;
     RECT  3.845 12 4.133 12.6 ;
     RECT  3.557 16.8 4.133 17.16 ;
     RECT  3.881 14.256 4.169 15.192 ;
     RECT  2.704 10.704 4.345 10.824 ;
     RECT  4.021 19.392 4.349 19.416 ;
     RECT  3.913 3.552 4.517 3.576 ;
     RECT  4.517 2.832 4.525 3.576 ;
     RECT  4.025 6.24 4.529 6.888 ;
     RECT  4.169 14.832 4.565 15.192 ;
     RECT  3.557 20.88 4.597 21.72 ;
     RECT  4.525 2.208 4.601 3.576 ;
     RECT  4.529 6.816 4.601 6.888 ;
     RECT  4.133 16.8 4.637 16.824 ;
     RECT  4.597 20.496 4.925 21.72 ;
     RECT  4.885 23.904 4.957 23.928 ;
     RECT  4.925 20.496 4.997 20.52 ;
     RECT  4.345 10.128 5.101 10.824 ;
     RECT  4.601 6.864 5.105 6.888 ;
     RECT  5.101 10.128 5.141 11.4 ;
     RECT  4.925 21.696 5.141 21.72 ;
     RECT  5.029 0.144 5.173 0.168 ;
     RECT  4.957 23.712 5.209 23.928 ;
     RECT  5.173 0.096 5.237 0.168 ;
     RECT  4.601 3.552 5.317 3.576 ;
     RECT  4.133 12.48 5.317 12.6 ;
     RECT  5.237 0.096 5.321 0.216 ;
     RECT  4.849 8.4 5.353 8.424 ;
     RECT  4.565 15.168 5.393 15.192 ;
     RECT  4.381 5.04 5.465 5.064 ;
     RECT  4.601 2.208 5.489 2.28 ;
     RECT  5.173 25.776 5.537 25.8 ;
     RECT  5.461 18.096 5.564 18.12 ;
     RECT  5.425 16.176 5.605 16.2 ;
     RECT  5.564 18 5.645 18.12 ;
     RECT  5.353 7.44 5.651 8.424 ;
     RECT  5.605 15.696 5.651 16.2 ;
     RECT  5.645 18 5.651 18.024 ;
     RECT  5.209 23.376 5.749 23.928 ;
     RECT  5.317 3.552 5.789 3.96 ;
     RECT  5.317 12.48 5.857 13.08 ;
     RECT  5.141 10.128 5.897 10.152 ;
     RECT  5.789 3.744 5.939 3.96 ;
     RECT  5.857 12.48 6.035 13.656 ;
     RECT  5.651 8.4 6.037 8.424 ;
     RECT  5.489 1.728 6.179 2.28 ;
     RECT  5.605 19.968 6.253 19.992 ;
     RECT  5.893 21.168 6.253 21.672 ;
     RECT  6.179 1.728 6.275 2.232 ;
     RECT  6.253 19.968 6.277 21.672 ;
     RECT  5.749 22.8 6.323 23.928 ;
     RECT  6.145 6.24 6.361 6.264 ;
     RECT  6.277 19.968 6.365 21.72 ;
     RECT  5.141 11.376 6.473 11.4 ;
     RECT  5.651 15.696 6.476 15.72 ;
     RECT  6.476 15.36 6.505 15.72 ;
     RECT  6.289 25.152 6.577 25.752 ;
     RECT  6.505 14.784 6.589 15.72 ;
     RECT  6.361 6.24 6.613 6.984 ;
     RECT  6.037 8.4 6.613 8.856 ;
     RECT  6.589 14.832 6.613 15.72 ;
     RECT  6.433 17.088 6.613 17.112 ;
     RECT  6.323 23.376 6.649 23.928 ;
     RECT  6.577 25.104 6.649 25.752 ;
     RECT  6.613 6.24 6.709 8.856 ;
     RECT  6.613 14.832 6.755 17.112 ;
     RECT  6.649 23.376 6.761 25.752 ;
     RECT  6.275 1.728 6.797 1.896 ;
     RECT  6.755 15.408 6.865 17.112 ;
     RECT  6.829 18.144 6.865 18.168 ;
     RECT  6.761 23.376 6.947 25.176 ;
     RECT  5.321 0.096 6.949 0.168 ;
     RECT  6.035 12.48 7.052 12.792 ;
     RECT  6.947 25.152 7.187 25.176 ;
     RECT  6.865 15.408 7.189 18.168 ;
     RECT  7.189 15.408 7.333 18.264 ;
     RECT  6.949 0.096 7.337 0.264 ;
     RECT  7.337 0.144 7.405 0.264 ;
     RECT  6.797 1.728 7.409 1.752 ;
     RECT  6.365 20.256 7.441 21.72 ;
     RECT  7.333 15.408 7.477 18.6 ;
     RECT  7.441 19.776 7.477 21.72 ;
     RECT  7.405 0.144 7.571 0.552 ;
     RECT  6.947 23.376 7.597 23.928 ;
     RECT  7.571 0.144 7.625 0.264 ;
     RECT  6.956 10.224 7.693 10.248 ;
     RECT  7.597 23.376 7.733 23.88 ;
     RECT  7.625 0.24 7.805 0.264 ;
     RECT  6.397 4.656 7.808 4.68 ;
     RECT  6.709 5.712 7.808 8.856 ;
     RECT  7.693 9.84 7.808 10.248 ;
     RECT  7.052 12.48 7.808 13.656 ;
     RECT  7.477 15.408 7.808 21.72 ;
     RECT  7.733 23.376 7.808 23.772 ;
     RECT  7.808 2.148 7.912 23.772 ;
     RECT  7.912 2.418 8.104 23.502 ;
     RECT  8.104 12.48 8.243 13.656 ;
     RECT  8.104 19.632 8.243 20.088 ;
     RECT  8.104 21.072 8.281 22.92 ;
     RECT  8.104 6.096 8.284 7.368 ;
     RECT  8.104 14.832 8.309 18.024 ;
     RECT  8.284 6.096 8.317 6.888 ;
     RECT  8.104 9.792 8.381 11.448 ;
     RECT  8.309 17.088 8.417 18.024 ;
     RECT  8.281 21.072 8.525 22.824 ;
     RECT  8.104 4.128 8.531 4.68 ;
     RECT  8.317 6.096 8.561 6.84 ;
     RECT  8.561 6.096 8.597 6.12 ;
     RECT  8.243 12.48 8.813 12.6 ;
     RECT  8.243 13.632 8.921 13.656 ;
     RECT  8.525 21.072 8.921 21.912 ;
     RECT  8.381 10.8 9.137 11.448 ;
     RECT  8.309 14.832 9.205 16.056 ;
     RECT  8.104 8.448 9.245 8.472 ;
     RECT  8.417 17.088 9.281 17.208 ;
     RECT  8.243 19.632 9.377 19.656 ;
     RECT  9.205 14.64 9.461 16.056 ;
     RECT  9.377 19.392 9.461 19.656 ;
     RECT  9.281 17.184 9.497 17.208 ;
     RECT  9.461 19.632 9.529 19.656 ;
     RECT  8.531 4.128 9.637 4.536 ;
     RECT  9.529 19.632 9.677 19.752 ;
     RECT  9.565 2.832 9.683 2.856 ;
     RECT  9.637 4.08 9.709 4.536 ;
     RECT  8.381 9.792 9.745 9.816 ;
     RECT  8.813 12.576 9.961 12.6 ;
     RECT  9.677 19.728 10.105 19.752 ;
     RECT  9.709 4.08 10.177 5.16 ;
     RECT  9.925 0.048 10.181 0.072 ;
     RECT  10.177 4.08 10.205 5.736 ;
     RECT  10.177 23.904 10.213 23.928 ;
     RECT  8.921 21.888 10.241 21.912 ;
     RECT  10.241 21.888 10.261 22.824 ;
     RECT  10.261 21.648 10.307 22.824 ;
     RECT  10.213 23.904 10.307 24.504 ;
     RECT  9.137 10.848 10.325 11.448 ;
     RECT  10.307 22.8 10.325 22.824 ;
     RECT  10.261 1.776 10.357 1.8 ;
     RECT  10.309 17.04 10.396 17.064 ;
     RECT  10.325 10.848 10.433 11.4 ;
     RECT  9.461 14.64 10.433 15.72 ;
     RECT  10.357 1.776 10.453 1.848 ;
     RECT  10.307 23.904 10.453 23.928 ;
     RECT  10.205 3.984 10.505 5.736 ;
     RECT  10.453 1.776 10.549 1.896 ;
     RECT  10.433 11.376 10.585 11.4 ;
     RECT  10.433 14.832 10.604 15.72 ;
     RECT  10.105 19.728 10.645 20.04 ;
     RECT  9.745 8.976 10.685 9.816 ;
     RECT  10.604 14.832 10.691 15.864 ;
     RECT  10.597 0.096 10.789 0.168 ;
     RECT  10.505 3.984 10.789 5.064 ;
     RECT  10.645 19.392 10.789 20.04 ;
     RECT  10.307 21.648 10.789 21.672 ;
     RECT  9.961 12.576 10.825 13.464 ;
     RECT  10.789 3.792 11.005 5.064 ;
     RECT  10.925 25.776 11.009 25.8 ;
     RECT  10.549 1.728 11.029 1.896 ;
     RECT  10.969 17.088 11.189 17.112 ;
     RECT  11.029 1.728 11.257 2.184 ;
     RECT  11.257 1.728 11.363 2.232 ;
     RECT  10.685 9.696 11.473 9.816 ;
     RECT  10.789 19.392 11.473 21.672 ;
     RECT  10.691 14.832 11.581 15.72 ;
     RECT  11.257 25.056 11.603 25.08 ;
     RECT  10.825 12.48 11.621 13.464 ;
     RECT  11.005 3.696 11.653 5.064 ;
     RECT  11.473 9.696 11.653 10.632 ;
     RECT  11.581 14.688 11.761 15.72 ;
     RECT  11.653 3.408 11.873 5.064 ;
     RECT  10.789 0.096 11.893 0.216 ;
     RECT  10.453 23.376 11.905 23.928 ;
     RECT  11.761 14.688 12.035 16.2 ;
     RECT  11.873 3.696 12.049 5.064 ;
     RECT  11.893 0.096 12.077 0.264 ;
     RECT  12.049 3.696 12.089 5.592 ;
     RECT  12.077 0.096 12.133 0.36 ;
     RECT  12.035 14.832 12.197 16.2 ;
     RECT  11.653 9.072 12.301 10.632 ;
     RECT  11.363 1.728 12.373 2.184 ;
     RECT  11.689 18.24 12.445 18.264 ;
     RECT  12.373 1.728 12.557 2.28 ;
     RECT  12.445 17.664 12.572 18.264 ;
     RECT  11.473 19.248 12.572 21.672 ;
     RECT  11.905 23.376 12.613 24.6 ;
     RECT  12.613 22.848 12.661 24.6 ;
     RECT  12.089 5.568 12.709 5.592 ;
     RECT  12.661 6.912 12.709 6.936 ;
     RECT  12.661 22.848 12.755 25.128 ;
     RECT  12.557 1.776 12.881 2.28 ;
     RECT  12.755 25.104 12.908 25.128 ;
     RECT  12.133 0.096 12.917 0.456 ;
     RECT  12.572 17.664 12.949 21.672 ;
     RECT  12.917 0.432 12.953 0.456 ;
     RECT  12.197 15.84 12.985 16.2 ;
     RECT  12.949 17.616 12.985 21.672 ;
     RECT  12.908 25.104 12.995 25.848 ;
     RECT  12.089 3.696 13.093 4.008 ;
     RECT  12.709 5.568 13.093 6.936 ;
     RECT  12.881 1.872 13.097 2.28 ;
     RECT  12.301 9.072 13.129 11.4 ;
     RECT  11.621 12.48 13.129 12.6 ;
     RECT  13.093 3.696 13.165 6.936 ;
     RECT  9.637 7.968 13.165 7.992 ;
     RECT  13.097 2.148 13.208 2.28 ;
     RECT  13.165 3.696 13.208 7.992 ;
     RECT  13.129 9.072 13.208 12.6 ;
     RECT  12.985 13.68 13.208 13.704 ;
     RECT  12.197 14.832 13.208 14.856 ;
     RECT  12.985 15.84 13.208 21.672 ;
     RECT  12.755 22.848 13.208 23.772 ;
     RECT  13.208 2.148 13.312 23.772 ;
     RECT  12.995 25.104 13.313 25.128 ;
     RECT  13.312 2.418 13.504 23.502 ;
     RECT  13.504 16.896 13.601 22.872 ;
     RECT  13.504 5.04 13.619 5.592 ;
     RECT  13.504 7.152 13.619 10.152 ;
     RECT  13.504 11.184 13.619 15.864 ;
     RECT  13.619 7.152 13.667 7.176 ;
     RECT  13.601 21.024 13.667 22.872 ;
     RECT  13.601 16.896 13.709 19.8 ;
     RECT  13.667 21.024 13.715 22.248 ;
     RECT  13.619 11.184 13.745 15.768 ;
     RECT  13.709 16.896 13.763 19.56 ;
     RECT  13.619 8.496 13.948 9.816 ;
     RECT  13.745 11.184 14.033 11.4 ;
     RECT  13.763 16.896 14.177 19.272 ;
     RECT  14.177 16.896 14.291 18.792 ;
     RECT  13.745 12.48 14.339 15.768 ;
     RECT  14.291 16.896 14.605 17.688 ;
     RECT  13.619 5.568 14.713 5.592 ;
     RECT  14.339 12.48 14.789 14.808 ;
     RECT  13.948 9.072 14.821 9.816 ;
     RECT  14.789 12.576 14.861 14.808 ;
     RECT  14.821 9.072 14.905 10.248 ;
     RECT  14.713 5.568 14.929 5.688 ;
     RECT  14.033 11.376 15.001 11.4 ;
     RECT  14.605 16.56 15.005 17.688 ;
     RECT  15.001 10.8 15.041 11.4 ;
     RECT  14.929 5.568 15.068 6.264 ;
     RECT  14.497 3.696 15.109 3.72 ;
     RECT  15.068 4.848 15.109 6.264 ;
     RECT  15.041 10.8 15.149 10.872 ;
     RECT  15.109 3.696 15.155 6.264 ;
     RECT  15.155 5.664 15.203 6.264 ;
     RECT  13.715 21.12 15.349 22.248 ;
     RECT  14.905 9.072 15.437 9.816 ;
     RECT  15.203 6.192 15.469 6.264 ;
     RECT  15.397 23.424 15.469 23.448 ;
     RECT  15.397 1.728 15.493 1.752 ;
     RECT  15.469 23.424 15.5 23.928 ;
     RECT  15.493 1.728 15.541 1.8 ;
     RECT  15.541 1.728 15.577 1.896 ;
     RECT  15.001 19.92 15.637 19.944 ;
     RECT  15.155 3.696 15.685 4.536 ;
     RECT  14.291 18.768 15.685 18.792 ;
     RECT  15.005 16.56 15.721 17.016 ;
     RECT  15.685 3.408 15.725 4.536 ;
     RECT  15.637 19.872 15.761 19.944 ;
     RECT  15.349 20.976 15.781 22.248 ;
     RECT  15.5 23.376 15.781 23.928 ;
     RECT  15.721 16.512 15.793 17.016 ;
     RECT  15.469 6.192 15.797 6.408 ;
     RECT  15.437 9.072 15.833 9.096 ;
     RECT  15.149 10.8 15.937 10.824 ;
     RECT  15.289 25.104 15.965 25.128 ;
     RECT  15.781 20.976 16.009 23.928 ;
     RECT  15.725 3.408 16.049 3.432 ;
     RECT  14.861 12.576 16.049 14.376 ;
     RECT  15.965 25.104 16.049 25.752 ;
     RECT  15.973 0.528 16.076 0.552 ;
     RECT  16.076 0.432 16.085 0.552 ;
     RECT  15.793 15.888 16.117 17.016 ;
     RECT  16.021 7.968 16.121 7.992 ;
     RECT  16.085 0.432 16.163 0.456 ;
     RECT  16.009 20.544 16.201 23.928 ;
     RECT  15.797 6.192 16.211 6.216 ;
     RECT  15.577 1.728 16.22 2.28 ;
     RECT  15.725 4.512 16.22 4.536 ;
     RECT  16.22 4.512 16.225 5.112 ;
     RECT  16.117 15.888 16.229 17.16 ;
     RECT  16.201 22.752 16.265 23.928 ;
     RECT  16.225 4.512 16.373 5.256 ;
     RECT  16.201 20.544 16.409 21.72 ;
     RECT  15.937 10.224 16.441 10.824 ;
     RECT  16.409 20.544 16.445 21.144 ;
     RECT  16.229 15.888 16.589 16.536 ;
     RECT  16.441 10.224 16.621 10.92 ;
     RECT  16.049 25.104 16.643 25.512 ;
     RECT  16.643 25.104 16.739 25.176 ;
     RECT  16.373 4.512 16.837 4.536 ;
     RECT  15.685 18.288 16.841 18.792 ;
     RECT  16.693 14.832 16.877 14.856 ;
     RECT  16.837 3.984 17.021 4.536 ;
     RECT  16.22 1.632 17.075 2.28 ;
     RECT  17.075 1.632 17.077 1.896 ;
     RECT  17.036 25.056 17.123 25.08 ;
     RECT  16.049 12.576 17.161 13.464 ;
     RECT  16.445 20.544 17.269 21.096 ;
     RECT  17.077 1.152 17.381 1.896 ;
     RECT  16.265 23.376 17.449 23.928 ;
     RECT  17.269 20.4 17.485 21.096 ;
     RECT  16.841 18.72 17.516 18.792 ;
     RECT  17.509 0.144 17.557 0.168 ;
     RECT  17.381 1.152 17.557 1.8 ;
     RECT  17.557 0.144 17.561 1.8 ;
     RECT  17.449 23.376 17.597 24.552 ;
     RECT  16.621 9.648 17.629 10.92 ;
     RECT  17.561 1.776 17.633 1.8 ;
     RECT  17.561 0.144 17.653 0.36 ;
     RECT  17.597 24.528 17.699 24.552 ;
     RECT  17.597 23.376 17.701 23.4 ;
     RECT  17.021 4.512 17.773 4.536 ;
     RECT  17.701 25.728 17.891 25.752 ;
     RECT  16.549 7.2 17.893 7.224 ;
     RECT  17.653 0.096 17.921 0.36 ;
     RECT  17.516 18.72 17.989 19.368 ;
     RECT  17.485 20.4 17.989 21.672 ;
     RECT  17.921 0.096 17.993 0.216 ;
     RECT  17.161 12.48 18.061 13.464 ;
     RECT  17.993 0.144 18.065 0.216 ;
     RECT  17.881 2.976 18.133 3 ;
     RECT  17.773 4.512 18.133 5.112 ;
     RECT  17.893 7.2 18.133 7.464 ;
     RECT  18.061 11.952 18.241 13.464 ;
     RECT  16.589 15.984 18.241 16.008 ;
     RECT  18.065 0.192 18.245 0.216 ;
     RECT  18.133 6.288 18.313 7.464 ;
     RECT  16.657 8.544 18.313 8.568 ;
     RECT  18.313 6.288 18.421 8.568 ;
     RECT  17.629 9.6 18.421 10.92 ;
     RECT  17.989 18.72 18.529 21.672 ;
     RECT  18.133 2.976 18.608 5.112 ;
     RECT  18.421 6.288 18.608 10.92 ;
     RECT  18.241 11.952 18.608 13.656 ;
     RECT  18.241 15.84 18.608 16.008 ;
     RECT  18.529 18.144 18.608 21.672 ;
     RECT  17.701 22.752 18.608 23.4 ;
     RECT  18.608 2.148 18.712 24.504 ;
     RECT  18.712 2.418 18.904 23.502 ;
     RECT  18.904 22.8 18.929 23.064 ;
     RECT  18.904 12.576 19.289 14.568 ;
     RECT  18.712 24.48 19.313 24.504 ;
     RECT  18.904 18.144 19.397 20.568 ;
     RECT  19.313 24.48 19.397 25.128 ;
     RECT  19.397 24.48 19.427 24.504 ;
     RECT  19.397 18.576 19.468 20.568 ;
     RECT  18.904 3.312 19.475 6.84 ;
     RECT  19.475 3.312 19.505 3.432 ;
     RECT  19.468 18.672 19.541 20.568 ;
     RECT  18.904 17.04 19.897 17.064 ;
     RECT  19.289 14.544 19.933 14.568 ;
     RECT  19.933 14.544 20.045 14.712 ;
     RECT  19.475 4.656 20.101 6.84 ;
     RECT  18.904 8.544 20.101 9.528 ;
     RECT  20.101 4.656 20.188 9.528 ;
     RECT  18.929 22.8 20.329 22.872 ;
     RECT  20.188 8.448 20.369 9.528 ;
     RECT  20.329 22.8 20.54 22.92 ;
     RECT  20.473 24.48 20.54 24.504 ;
     RECT  20.188 4.656 20.549 7.416 ;
     RECT  20.293 21.648 20.621 21.672 ;
     RECT  20.581 0.096 20.636 0.12 ;
     RECT  19.541 18.672 20.677 20.424 ;
     RECT  20.636 0.096 20.725 0.552 ;
     RECT  19.897 16.992 20.78 17.064 ;
     RECT  20.549 4.656 20.812 6.264 ;
     RECT  18.904 15.984 20.819 16.008 ;
     RECT  20.369 9.456 20.877 9.528 ;
     RECT  20.54 22.8 20.905 24.504 ;
     RECT  19.897 11.376 20.909 11.4 ;
     RECT  20.812 4.656 20.963 4.68 ;
     RECT  20.877 9.456 20.963 9.48 ;
     RECT  20.897 1.728 20.965 1.752 ;
     RECT  19.289 12.576 20.977 12.84 ;
     RECT  20.78 16.992 20.977 17.112 ;
     RECT  20.965 1.728 21.013 1.848 ;
     RECT  20.905 22.8 21.013 24.552 ;
     RECT  20.965 25.776 21.013 25.8 ;
     RECT  20.977 16.992 21.061 17.64 ;
     RECT  20.677 18.672 21.085 21.192 ;
     RECT  21.013 22.8 21.158 25.8 ;
     RECT  21.158 22.8 21.241 25.752 ;
     RECT  21.241 23.376 21.347 25.752 ;
     RECT  20.549 7.392 21.373 7.416 ;
     RECT  20.045 14.544 21.445 14.568 ;
     RECT  20.369 8.448 21.449 8.472 ;
     RECT  21.445 14.256 21.449 14.568 ;
     RECT  19.505 3.408 21.481 3.432 ;
     RECT  21.481 3.312 21.521 3.432 ;
     RECT  20.977 12.576 21.553 13.08 ;
     RECT  21.373 7.392 21.625 7.464 ;
     RECT  21.347 25.056 21.683 25.752 ;
     RECT  20.812 5.856 21.685 6.264 ;
     RECT  21.625 7.392 21.685 7.896 ;
     RECT  21.685 5.856 21.737 7.896 ;
     RECT  21.737 5.856 21.773 7.512 ;
     RECT  21.553 12.432 21.809 13.08 ;
     RECT  21.061 16.992 21.809 17.016 ;
     RECT  21.809 12.576 22.021 13.08 ;
     RECT  21.013 1.728 22.028 2.28 ;
     RECT  21.521 3.312 22.028 3.336 ;
     RECT  20.725 0.096 22.213 0.648 ;
     RECT  22.028 1.728 22.213 3.336 ;
     RECT  22.213 0.096 22.277 3.336 ;
     RECT  21.683 25.104 22.307 25.752 ;
     RECT  22.307 25.152 22.499 25.752 ;
     RECT  22.277 0.096 22.565 2.28 ;
     RECT  22.021 12.576 22.741 13.224 ;
     RECT  21.449 14.256 22.741 14.28 ;
     RECT  21.347 23.376 22.741 23.928 ;
     RECT  21.773 5.856 22.813 6.264 ;
     RECT  22.741 23.376 22.835 24.024 ;
     RECT  22.499 25.68 22.837 25.752 ;
     RECT  21.98 16.512 22.844 16.776 ;
     RECT  21.085 18.288 22.844 21.192 ;
     RECT  21.949 10.224 22.853 10.248 ;
     RECT  22.741 12.576 22.883 14.28 ;
     RECT  22.844 16.512 22.925 21.192 ;
     RECT  21.773 7.44 22.957 7.512 ;
     RECT  22.837 25.68 22.982 25.8 ;
     RECT  22.957 7.44 23.033 7.992 ;
     RECT  22.982 25.728 23.123 25.752 ;
     RECT  22.565 0.096 23.141 0.216 ;
     RECT  22.565 1.728 23.141 2.28 ;
     RECT  22.925 18.768 23.317 21.192 ;
     RECT  22.117 22.224 23.317 22.248 ;
     RECT  23.141 1.776 23.357 2.28 ;
     RECT  22.813 5.136 23.497 6.264 ;
     RECT  22.925 16.512 23.533 17.64 ;
     RECT  23.141 0.096 23.555 0.12 ;
     RECT  23.033 7.968 23.677 7.992 ;
     RECT  22.489 9.072 23.677 9.096 ;
     RECT  22.883 12.576 23.708 13.224 ;
     RECT  23.497 5.136 23.852 6.312 ;
     RECT  22.277 3.312 23.893 3.336 ;
     RECT  23.137 10.176 23.893 10.2 ;
     RECT  23.389 11.424 23.893 11.448 ;
     RECT  23.357 2.148 24.008 2.28 ;
     RECT  23.893 3.312 24.008 3.864 ;
     RECT  23.852 4.848 24.008 6.312 ;
     RECT  23.677 7.968 24.008 9.096 ;
     RECT  23.893 10.176 24.008 11.448 ;
     RECT  23.708 12.48 24.008 13.224 ;
     RECT  22.885 14.784 24.008 14.808 ;
     RECT  23.533 16.032 24.008 17.64 ;
     RECT  23.317 18.768 24.008 22.248 ;
     RECT  22.835 23.376 24.008 23.4 ;
     RECT  24.008 2.148 24.112 23.772 ;
     RECT  24.112 2.418 24.304 23.502 ;
     RECT  24.304 2.784 24.419 4.008 ;
     RECT  24.304 14.784 24.419 16.056 ;
     RECT  24.419 16.032 24.437 16.056 ;
     RECT  24.304 10.176 24.473 11.4 ;
     RECT  24.304 21.168 24.553 22.008 ;
     RECT  24.304 7.248 24.611 7.272 ;
     RECT  24.304 12.576 24.653 13.128 ;
     RECT  24.553 21.168 24.761 21.768 ;
     RECT  24.761 21.168 24.869 21.192 ;
     RECT  24.304 17.616 24.941 18.792 ;
     RECT  24.419 3.312 25.121 4.008 ;
     RECT  24.473 10.176 25.121 10.2 ;
     RECT  24.304 9.072 25.285 9.192 ;
     RECT  24.419 14.784 25.301 14.808 ;
     RECT  25.285 8.496 25.405 9.192 ;
     RECT  25.285 7.392 25.445 7.416 ;
     RECT  25.405 8.496 25.489 9.672 ;
     RECT  24.304 6 25.513 6.024 ;
     RECT  25.513 6 25.553 6.264 ;
     RECT  24.473 11.376 25.589 11.4 ;
     RECT  24.653 12.576 25.657 12.984 ;
     RECT  25.429 21.12 25.661 21.144 ;
     RECT  25.693 22.848 25.724 22.872 ;
     RECT  25.724 22.848 25.765 23.4 ;
     RECT  25.489 8.496 25.801 9 ;
     RECT  25.765 22.848 25.829 23.736 ;
     RECT  25.765 1.728 25.909 1.752 ;
     RECT  24.941 17.616 25.913 18.696 ;
     RECT  25.861 0.576 26.005 0.6 ;
     RECT  25.121 3.312 26.053 3.336 ;
     RECT  25.553 6.24 26.053 6.264 ;
     RECT  25.913 17.856 26.089 18.696 ;
     RECT  25.801 7.968 26.099 9 ;
     RECT  26.053 2.832 26.129 3.336 ;
     RECT  25.297 16.272 26.129 16.296 ;
     RECT  26.053 6.24 26.137 6.84 ;
     RECT  26.125 25.104 26.161 25.128 ;
     RECT  25.909 1.728 26.204 1.8 ;
     RECT  26.129 2.832 26.204 2.856 ;
     RECT  26.161 25.008 26.243 25.128 ;
     RECT  26.243 25.008 26.291 25.032 ;
     RECT  26.005 0.096 26.341 0.6 ;
     RECT  26.204 1.728 26.341 2.856 ;
     RECT  25.829 22.848 26.341 23.928 ;
     RECT  26.341 22.752 26.425 23.928 ;
     RECT  26.341 0.096 26.597 2.856 ;
     RECT  26.137 6.24 26.629 6.696 ;
     RECT  25.657 12.576 26.629 13.704 ;
     RECT  26.125 4.512 26.725 4.536 ;
     RECT  26.629 5.712 26.725 6.696 ;
     RECT  26.725 4.512 26.771 6.696 ;
     RECT  26.125 10.848 26.845 10.872 ;
     RECT  26.771 4.512 26.849 5.112 ;
     RECT  26.845 10.8 26.881 10.872 ;
     RECT  26.099 8.496 26.885 9 ;
     RECT  26.089 17.856 26.885 19.368 ;
     RECT  26.597 0.576 26.963 2.856 ;
     RECT  26.425 22.8 27.061 23.928 ;
     RECT  26.629 12.576 27.065 13.992 ;
     RECT  26.963 1.728 27.101 2.856 ;
     RECT  27.065 12.816 27.26 13.992 ;
     RECT  26.881 10.704 27.277 10.872 ;
     RECT  26.885 17.856 27.281 18.792 ;
     RECT  27.26 12.816 27.313 14.568 ;
     RECT  27.301 15.984 27.313 16.008 ;
     RECT  27.301 21.312 27.313 21.336 ;
     RECT  26.771 6.672 27.349 6.696 ;
     RECT  27.061 22.8 27.353 24.552 ;
     RECT  27.313 21.072 27.385 21.336 ;
     RECT  27.385 20.544 27.388 21.336 ;
     RECT  27.277 10.704 27.529 11.688 ;
     RECT  27.313 12.816 27.569 16.008 ;
     RECT  27.569 14.832 27.587 16.008 ;
     RECT  27.353 23.376 27.587 24.552 ;
     RECT  26.963 0.576 27.637 0.6 ;
     RECT  27.101 1.728 27.827 2.28 ;
     RECT  27.349 6.672 27.877 7.464 ;
     RECT  26.885 8.976 27.877 9 ;
     RECT  27.827 1.728 27.893 1.848 ;
     RECT  27.877 3.312 27.964 3.336 ;
     RECT  27.877 6.672 27.964 9 ;
     RECT  27.637 0.096 28.019 0.6 ;
     RECT  27.745 25.104 28.019 25.128 ;
     RECT  27.893 1.728 28.021 1.8 ;
     RECT  28.019 0.096 28.037 0.168 ;
     RECT  28.021 1.152 28.253 1.8 ;
     RECT  27.587 23.376 28.253 23.928 ;
     RECT  27.964 6.672 28.289 7.464 ;
     RECT  28.253 23.376 28.307 23.448 ;
     RECT  27.587 15.936 28.309 16.008 ;
     RECT  27.281 18.24 28.309 18.792 ;
     RECT  28.037 0.144 28.325 0.168 ;
     RECT  28.253 1.2 28.361 1.8 ;
     RECT  28.309 18.24 28.364 18.84 ;
     RECT  28.361 1.2 28.433 1.752 ;
     RECT  28.177 2.928 28.433 2.952 ;
     RECT  28.405 22.32 28.453 22.344 ;
     RECT  28.433 1.2 28.469 1.224 ;
     RECT  27.388 20.544 28.537 21.096 ;
     RECT  27.587 14.832 28.549 14.952 ;
     RECT  28.309 15.936 28.549 16.44 ;
     RECT  28.453 22.224 28.645 22.344 ;
     RECT  28.537 20.448 28.693 21.096 ;
     RECT  28.645 22.224 28.693 23.016 ;
     RECT  27.964 8.544 28.825 9 ;
     RECT  27.569 12.816 28.885 13.08 ;
     RECT  28.549 14.832 29.077 16.44 ;
     RECT  28.693 20.448 29.213 23.016 ;
     RECT  28.885 12.816 29.269 13.704 ;
     RECT  29.077 14.832 29.269 16.68 ;
     RECT  26.849 4.512 29.408 4.536 ;
     RECT  28.289 6.672 29.408 6.888 ;
     RECT  28.825 8.544 29.408 9.096 ;
     RECT  27.529 10.176 29.408 11.688 ;
     RECT  29.269 12.816 29.408 16.68 ;
     RECT  28.364 18.24 29.408 18.936 ;
     RECT  29.213 20.064 29.408 23.016 ;
     RECT  29.408 2.148 29.512 23.772 ;
     RECT  29.512 2.418 29.704 23.502 ;
     RECT  29.704 4.512 29.765 4.536 ;
     RECT  29.704 15.984 29.837 19.512 ;
     RECT  29.837 15.984 30.233 17.64 ;
     RECT  29.704 14.688 30.341 14.952 ;
     RECT  29.509 0.048 30.371 0.072 ;
     RECT  29.704 6.672 30.521 7.08 ;
     RECT  29.704 21.12 30.563 21.192 ;
     RECT  30.341 14.688 30.707 14.856 ;
     RECT  29.704 8.544 30.737 9 ;
     RECT  30.707 14.784 30.745 14.856 ;
     RECT  30.805 5.472 30.908 5.496 ;
     RECT  30.877 0.096 30.995 0.216 ;
     RECT  30.908 5.472 30.997 5.64 ;
     RECT  31.121 1.728 31.129 1.752 ;
     RECT  30.589 24.048 31.129 24.072 ;
     RECT  30.521 7.056 31.141 7.08 ;
     RECT  30.737 8.976 31.141 9 ;
     RECT  29.704 10.8 31.141 11.688 ;
     RECT  29.704 12.816 31.141 13.608 ;
     RECT  31.129 23.904 31.189 24.072 ;
     RECT  31.141 10.8 31.201 13.608 ;
     RECT  31.141 7.056 31.228 7.944 ;
     RECT  31.129 1.728 31.235 2.28 ;
     RECT  30.997 5.472 31.237 5.832 ;
     RECT  30.233 15.984 31.237 16.008 ;
     RECT  30.233 17.04 31.237 17.64 ;
     RECT  29.704 22.8 31.244 22.824 ;
     RECT  31.189 23.808 31.244 24.072 ;
     RECT  31.228 7.056 31.283 7.8 ;
     RECT  31.141 8.976 31.283 9.096 ;
     RECT  31.201 10.224 31.345 13.608 ;
     RECT  30.995 0.144 31.409 0.216 ;
     RECT  30.745 14.832 31.477 14.856 ;
     RECT  31.409 0.144 31.493 0.264 ;
     RECT  31.345 10.224 31.523 13.656 ;
     RECT  31.477 14.832 31.525 14.952 ;
     RECT  31.237 15.984 31.525 17.64 ;
     RECT  31.237 4.512 31.529 5.832 ;
     RECT  31.244 22.8 31.571 24.072 ;
     RECT  30.563 21.168 31.589 21.192 ;
     RECT  31.235 1.728 31.661 1.896 ;
     RECT  31.283 7.056 31.673 7.08 ;
     RECT  31.571 23.088 31.813 24.072 ;
     RECT  30.697 25.104 31.813 25.128 ;
     RECT  31.813 23.088 31.849 25.128 ;
     RECT  31.525 14.832 31.909 17.64 ;
     RECT  29.837 18.672 31.909 19.512 ;
     RECT  31.909 14.832 31.955 19.512 ;
     RECT  31.849 23.088 31.955 25.56 ;
     RECT  31.955 14.832 31.997 18.792 ;
     RECT  31.955 23.088 32.147 25.128 ;
     RECT  31.997 17.616 32.177 18.792 ;
     RECT  32.147 25.056 32.243 25.128 ;
     RECT  31.661 1.68 32.249 1.896 ;
     RECT  31.493 0.144 32.341 0.216 ;
     RECT  32.197 3.264 32.389 3.288 ;
     RECT  31.529 4.512 32.389 5.736 ;
     RECT  31.283 8.976 32.425 9 ;
     RECT  31.997 14.832 32.435 16.008 ;
     RECT  32.389 3.264 32.465 5.736 ;
     RECT  32.341 0.096 32.485 0.216 ;
     RECT  32.425 8.976 32.492 9.096 ;
     RECT  32.147 23.088 32.572 23.928 ;
     RECT  32.465 3.936 32.579 5.736 ;
     RECT  31.589 21.12 32.581 21.192 ;
     RECT  32.437 14.784 32.609 14.808 ;
     RECT  32.492 8.112 32.636 9.096 ;
     RECT  32.579 5.136 32.641 5.736 ;
     RECT  31.523 11.328 32.669 13.656 ;
     RECT  32.581 21.12 32.677 21.912 ;
     RECT  32.677 19.968 32.681 21.912 ;
     RECT  32.636 7.248 32.723 9.096 ;
     RECT  32.723 8.112 32.725 9.096 ;
     RECT  31.523 10.224 32.725 10.248 ;
     RECT  32.669 11.328 32.753 14.28 ;
     RECT  32.725 8.112 32.771 10.248 ;
     RECT  32.681 19.968 32.771 21.192 ;
     RECT  32.485 0.096 32.825 0.312 ;
     RECT  32.771 8.976 32.825 10.248 ;
     RECT  32.569 2.88 32.861 2.952 ;
     RECT  32.861 2.88 32.867 2.904 ;
     RECT  32.771 19.968 32.965 19.992 ;
     RECT  32.579 3.936 32.969 4.104 ;
     RECT  32.965 22.224 33.049 22.248 ;
     RECT  32.243 25.056 33.107 25.08 ;
     RECT  32.825 0.288 33.145 0.312 ;
     RECT  32.249 1.68 33.145 1.848 ;
     RECT  32.435 15.936 33.149 16.008 ;
     RECT  32.753 11.328 33.185 13.704 ;
     RECT  33.145 0.288 33.221 1.848 ;
     RECT  33.221 1.152 33.229 1.848 ;
     RECT  32.641 5.136 33.257 6.264 ;
     RECT  32.177 18.192 33.26 18.792 ;
     RECT  32.572 23.376 33.364 23.928 ;
     RECT  33.185 11.328 33.365 11.352 ;
     RECT  33.257 5.664 33.397 6.264 ;
     RECT  32.825 8.976 33.401 9.528 ;
     RECT  33.26 17.616 33.404 18.792 ;
     RECT  32.965 19.92 33.404 19.992 ;
     RECT  33.364 23.376 33.473 23.976 ;
     RECT  33.149 15.936 33.505 15.96 ;
     RECT  33.229 1.728 33.541 1.848 ;
     RECT  33.541 1.728 33.545 2.52 ;
     RECT  33.473 23.376 33.545 23.928 ;
     RECT  33.545 1.776 33.617 2.52 ;
     RECT  33.617 2.496 33.797 2.52 ;
     RECT  33.185 12.48 33.829 13.704 ;
     RECT  33.505 15.696 33.829 15.96 ;
     RECT  33.404 17.616 33.841 19.992 ;
     RECT  33.841 17.616 34.076 19.416 ;
     RECT  32.771 21.168 34.081 21.192 ;
     RECT  32.969 4.08 34.117 4.104 ;
     RECT  33.829 12.48 34.261 15.96 ;
     RECT  34.076 16.992 34.261 19.416 ;
     RECT  33.397 5.664 34.333 6.84 ;
     RECT  34.333 5.472 34.405 6.84 ;
     RECT  34.081 20.544 34.405 21.192 ;
     RECT  34.364 0.048 34.441 0.072 ;
     RECT  34.441 0.048 34.451 0.12 ;
     RECT  34.405 5.472 34.477 7.128 ;
     RECT  34.009 10.848 34.477 10.872 ;
     RECT  34.117 3.648 34.501 4.104 ;
     RECT  34.451 0.096 34.547 0.12 ;
     RECT  34.405 20.544 34.597 21.72 ;
     RECT  34.501 3.408 34.808 4.104 ;
     RECT  34.477 5.472 34.808 7.176 ;
     RECT  33.401 9.072 34.808 9.528 ;
     RECT  34.477 10.848 34.808 10.968 ;
     RECT  34.261 12.48 34.808 19.416 ;
     RECT  34.597 20.544 34.808 21.768 ;
     RECT  33.613 22.8 34.808 23.256 ;
     RECT  34.808 2.148 34.912 23.772 ;
     RECT  34.912 2.418 35.104 23.502 ;
     RECT  35.104 11.376 35.219 11.4 ;
     RECT  35.104 6.864 35.237 7.176 ;
     RECT  35.104 18.096 35.237 23.448 ;
     RECT  35.237 18.096 35.245 21.288 ;
     RECT  35.104 14.832 35.309 17.112 ;
     RECT  35.309 15.36 35.381 17.112 ;
     RECT  35.381 15.36 35.459 17.016 ;
     RECT  35.104 12.48 35.507 13.848 ;
     RECT  35.507 12.48 35.741 13.368 ;
     RECT  35.459 15.36 35.813 16.2 ;
     RECT  35.813 15.36 35.957 15.384 ;
     RECT  35.237 22.272 36.101 23.448 ;
     RECT  35.104 4.896 36.284 5.496 ;
     RECT  36.229 1.728 36.305 1.752 ;
     RECT  36.101 23.328 36.325 23.448 ;
     RECT  36.284 4.896 36.371 5.736 ;
     RECT  35.104 3.264 36.373 3.672 ;
     RECT  36.371 4.896 36.373 4.92 ;
     RECT  36.325 23.328 36.385 23.928 ;
     RECT  36.101 22.272 36.389 22.296 ;
     RECT  35.245 20.736 36.533 21.288 ;
     RECT  36.373 3.264 36.565 4.92 ;
     RECT  36.385 23.328 36.593 24.552 ;
     RECT  36.092 0.528 36.601 0.552 ;
     RECT  36.601 0.432 36.605 0.552 ;
     RECT  36.421 25.728 36.61 25.752 ;
     RECT  36.593 23.328 36.677 24.6 ;
     RECT  35.237 7.152 36.745 7.176 ;
     RECT  35.741 12.816 36.757 13.368 ;
     RECT  36.745 6.24 36.829 7.176 ;
     RECT  36.812 11.376 36.853 11.4 ;
     RECT  36.757 12.528 36.853 13.368 ;
     RECT  36.853 10.8 36.899 11.4 ;
     RECT  36.61 25.68 36.899 25.8 ;
     RECT  36.605 0.432 36.901 0.456 ;
     RECT  36.901 0.144 37.025 0.456 ;
     RECT  37.025 0.096 37.109 0.456 ;
     RECT  36.899 10.8 37.109 10.824 ;
     RECT  36.305 1.728 37.141 1.848 ;
     RECT  36.565 2.88 37.141 4.92 ;
     RECT  37.109 0.144 37.145 0.456 ;
     RECT  36.961 16.8 37.177 16.824 ;
     RECT  37.145 0.144 37.181 0.168 ;
     RECT  37.177 15.936 37.189 16.824 ;
     RECT  35.245 18.096 37.189 19.656 ;
     RECT  37.189 15.936 37.261 19.656 ;
     RECT  36.829 6.288 37.285 7.176 ;
     RECT  37.285 6.288 37.372 7.608 ;
     RECT  37.141 1.728 37.433 4.92 ;
     RECT  37.261 16.512 37.484 19.656 ;
     RECT  37.433 1.728 37.505 3.432 ;
     RECT  37.484 16.512 37.571 20.52 ;
     RECT  37.505 3.264 37.577 3.432 ;
     RECT  37.505 1.728 37.637 2.28 ;
     RECT  36.637 21.648 37.669 22.2 ;
     RECT  36.677 23.328 37.669 24.552 ;
     RECT  36.853 12.384 37.793 13.368 ;
     RECT  37.717 14.784 37.801 14.808 ;
     RECT  37.433 4.656 37.813 4.92 ;
     RECT  37.372 6.288 37.825 6.84 ;
     RECT  37.669 21.648 37.897 24.552 ;
     RECT  36.899 25.776 37.897 25.8 ;
     RECT  37.813 4.656 37.901 5.112 ;
     RECT  35.104 9.504 37.997 9.528 ;
     RECT  37.465 10.752 37.997 10.776 ;
     RECT  37.571 16.944 38.005 20.52 ;
     RECT  37.897 21.648 38.005 25.8 ;
     RECT  37.997 9.504 38.041 10.776 ;
     RECT  37.793 12.816 38.051 13.368 ;
     RECT  38.041 8.736 38.081 10.776 ;
     RECT  38.005 16.944 38.117 25.8 ;
     RECT  37.637 1.152 38.189 2.28 ;
     RECT  37.577 3.408 38.261 3.432 ;
     RECT  38.117 16.944 38.339 25.656 ;
     RECT  38.339 21.072 38.387 25.656 ;
     RECT  38.339 16.944 38.435 20.088 ;
     RECT  38.245 0.144 38.437 0.168 ;
     RECT  38.189 1.152 38.437 1.848 ;
     RECT  38.437 0.144 38.441 1.848 ;
     RECT  37.825 6.24 38.441 6.84 ;
     RECT  38.387 21.072 38.441 23.928 ;
     RECT  38.081 10.752 38.473 10.776 ;
     RECT  38.387 25.2 38.483 25.656 ;
     RECT  38.441 0.144 38.549 0.216 ;
     RECT  38.483 25.248 38.627 25.656 ;
     RECT  38.441 1.728 38.657 1.848 ;
     RECT  38.441 21.456 38.657 23.928 ;
     RECT  38.549 0.144 38.729 0.168 ;
     RECT  38.657 1.776 38.765 1.848 ;
     RECT  38.435 17.04 38.765 20.088 ;
     RECT  38.657 21.456 38.765 23.88 ;
     RECT  38.473 10.752 38.771 11.448 ;
     RECT  38.684 15.312 38.771 15.336 ;
     RECT  38.441 6.24 38.801 6.312 ;
     RECT  38.765 17.088 38.801 20.088 ;
     RECT  38.801 17.088 38.845 19.8 ;
     RECT  38.051 13.344 39.053 13.368 ;
     RECT  38.765 21.456 39.089 23.112 ;
     RECT  38.845 17.088 39.125 19.464 ;
     RECT  38.081 8.736 39.157 9.672 ;
     RECT  38.771 10.752 39.157 10.92 ;
     RECT  39.157 8.736 39.197 10.92 ;
     RECT  38.801 6.24 39.517 6.264 ;
     RECT  39.337 14.928 39.553 14.952 ;
     RECT  39.013 7.44 39.685 7.464 ;
     RECT  39.685 7.44 39.733 7.752 ;
     RECT  39.125 17.088 39.769 19.416 ;
     RECT  38.627 25.248 39.773 25.272 ;
     RECT  39.769 1.152 39.917 1.176 ;
     RECT  39.013 12.336 40.021 12.36 ;
     RECT  37.901 4.656 40.069 4.68 ;
     RECT  40.021 12.336 40.093 13.128 ;
     RECT  39.553 14.208 40.093 14.952 ;
     RECT  39.769 16.272 40.201 19.416 ;
     RECT  39.229 2.256 40.208 2.28 ;
     RECT  40.069 3.408 40.208 3.432 ;
     RECT  40.069 4.416 40.208 4.68 ;
     RECT  39.517 6.096 40.208 6.264 ;
     RECT  39.733 7.344 40.208 7.752 ;
     RECT  39.197 8.736 40.208 8.76 ;
     RECT  39.197 9.936 40.208 10.92 ;
     RECT  40.093 12.336 40.208 14.952 ;
     RECT  40.201 16.272 40.208 20.328 ;
     RECT  39.089 21.6 40.208 23.112 ;
     RECT  40.021 24.528 40.208 24.552 ;
     RECT  40.208 2.148 40.312 24.552 ;
     RECT  40.312 2.418 40.504 23.502 ;
     RECT  40.504 4.416 40.565 6.36 ;
     RECT  40.504 16.512 40.673 18.216 ;
     RECT  40.565 4.416 40.817 5.256 ;
     RECT  40.817 5.232 40.997 5.256 ;
     RECT  40.565 6.24 41.02 6.36 ;
     RECT  40.504 7.728 41.033 7.896 ;
     RECT  40.504 9.072 41.149 10.92 ;
     RECT  41.149 9.792 41.213 10.92 ;
     RECT  40.504 3.408 41.249 3.432 ;
     RECT  40.312 24.528 41.317 24.552 ;
     RECT  41.276 0.528 41.413 0.552 ;
     RECT  40.504 22.8 41.497 23.4 ;
     RECT  41.317 24.528 41.497 24.6 ;
     RECT  41.497 22.8 41.557 24.6 ;
     RECT  40.504 19.968 41.645 20.328 ;
     RECT  40.504 12.384 41.669 13.608 ;
     RECT  40.673 16.512 41.677 17.736 ;
     RECT  41.213 9.792 41.699 10.776 ;
     RECT  41.557 22.08 41.795 24.6 ;
     RECT  41.525 1.728 41.893 1.752 ;
     RECT  41.893 1.728 41.965 1.8 ;
     RECT  41.645 20.208 41.965 20.328 ;
     RECT  41.795 22.08 41.965 23.928 ;
     RECT  41.413 0.096 41.969 0.552 ;
     RECT  41.965 20.208 42.179 23.928 ;
     RECT  41.653 3.792 42.188 3.96 ;
     RECT  41.02 6.24 42.188 6.264 ;
     RECT  41.969 0.144 42.209 0.552 ;
     RECT  41.965 1.728 42.209 2.28 ;
     RECT  42.209 0.144 42.229 2.28 ;
     RECT  42.229 0.144 42.253 2.568 ;
     RECT  42.188 3.792 42.253 4.104 ;
     RECT  41.033 7.824 42.257 7.896 ;
     RECT  42.253 0.144 42.275 4.104 ;
     RECT  42.188 5.376 42.275 6.264 ;
     RECT  41.669 12.384 42.361 13.656 ;
     RECT  41.677 16.464 42.361 17.736 ;
     RECT  42.275 0.144 42.365 2.952 ;
     RECT  42.257 7.872 42.38 7.896 ;
     RECT  42.361 11.52 42.421 13.656 ;
     RECT  42.38 7.872 42.467 8.376 ;
     RECT  42.361 16.464 42.469 18.504 ;
     RECT  42.421 11.52 42.572 14.28 ;
     RECT  42.365 0.144 42.581 2.568 ;
     RECT  42.179 20.208 42.613 21.384 ;
     RECT  42.572 11.52 42.617 14.808 ;
     RECT  42.617 11.52 42.653 13.128 ;
     RECT  42.469 16.08 42.653 18.792 ;
     RECT  42.617 14.256 42.659 14.808 ;
     RECT  42.653 16.08 42.689 18.504 ;
     RECT  41.699 9.792 42.757 9.816 ;
     RECT  42.689 16.08 42.793 17.736 ;
     RECT  42.757 9.792 42.797 10.392 ;
     RECT  42.659 14.256 42.797 14.28 ;
     RECT  42.613 20.112 42.908 21.384 ;
     RECT  42.793 15.408 42.977 17.736 ;
     RECT  42.908 19.92 42.995 21.384 ;
     RECT  42.995 20.112 43.013 21.384 ;
     RECT  42.581 0.144 43.229 0.696 ;
     RECT  43.013 20.448 43.297 21.384 ;
     RECT  42.467 7.872 43.333 7.896 ;
     RECT  43.297 20.448 43.337 21.672 ;
     RECT  43.337 20.448 43.373 20.472 ;
     RECT  43.189 4.56 43.405 4.584 ;
     RECT  42.073 25.104 43.427 25.128 ;
     RECT  42.179 22.752 43.481 23.928 ;
     RECT  43.229 0.144 43.525 0.6 ;
     RECT  42.977 15.408 43.553 17.448 ;
     RECT  42.581 1.728 43.589 2.568 ;
     RECT  43.525 0.096 43.625 0.6 ;
     RECT  43.405 4.56 43.724 5.16 ;
     RECT  42.653 11.52 43.765 11.544 ;
     RECT  42.653 13.104 43.772 13.128 ;
     RECT  43.765 11.52 43.805 11.976 ;
     RECT  43.481 22.752 43.805 23.88 ;
     RECT  43.724 3.936 43.811 5.16 ;
     RECT  43.553 15.408 43.813 15.432 ;
     RECT  43.772 13.056 43.859 13.128 ;
     RECT  43.813 14.832 43.871 15.432 ;
     RECT  43.589 2.256 43.907 2.568 ;
     RECT  43.805 22.752 43.907 23.784 ;
     RECT  43.337 21.648 43.909 21.672 ;
     RECT  43.907 22.752 43.909 23.4 ;
     RECT  43.859 13.104 43.913 13.128 ;
     RECT  43.625 0.096 43.949 0.264 ;
     RECT  42.797 10.368 43.949 10.392 ;
     RECT  43.805 11.952 43.949 11.976 ;
     RECT  43.871 14.256 43.955 15.432 ;
     RECT  43.553 16.992 43.955 17.448 ;
     RECT  43.949 0.144 44.021 0.264 ;
     RECT  44.021 0.24 44.093 0.264 ;
     RECT  43.955 14.256 44.273 14.856 ;
     RECT  44.305 18.768 44.389 19.368 ;
     RECT  43.909 21.648 44.521 23.4 ;
     RECT  43.907 2.544 44.561 2.568 ;
     RECT  43.811 4.56 44.593 5.16 ;
     RECT  43.081 9.12 44.629 9.144 ;
     RECT  44.593 4.56 44.633 5.256 ;
     RECT  44.273 14.256 44.633 14.808 ;
     RECT  44.629 9.12 44.773 9.24 ;
     RECT  45.061 20.496 45.097 20.52 ;
     RECT  44.521 21.504 45.097 23.4 ;
     RECT  43.333 7.392 45.169 7.896 ;
     RECT  44.633 5.232 45.608 5.256 ;
     RECT  42.275 6.24 45.608 6.264 ;
     RECT  45.169 7.392 45.608 7.944 ;
     RECT  44.773 9.12 45.608 9.672 ;
     RECT  44.953 10.896 45.608 10.92 ;
     RECT  44.633 14.784 45.608 14.808 ;
     RECT  43.955 17.04 45.608 17.448 ;
     RECT  44.389 19.104 45.608 19.368 ;
     RECT  45.097 20.496 45.608 23.4 ;
     RECT  45.608 2.148 45.712 23.772 ;
     RECT  45.457 25.104 45.749 25.128 ;
     RECT  45.712 2.148 45.904 23.502 ;
     RECT  45.904 7.92 46.037 9.672 ;
     RECT  45.904 5.136 46.163 6.888 ;
     RECT  45.961 0.096 46.181 0.12 ;
     RECT  46.037 9.408 46.397 9.672 ;
     RECT  46.163 5.136 46.451 6.84 ;
     RECT  45.904 15.984 46.469 19.464 ;
     RECT  46.529 1.728 46.537 1.848 ;
     RECT  45.904 20.496 46.613 22.2 ;
     RECT  45.904 10.896 46.649 11.928 ;
     RECT  46.537 1.152 46.685 1.848 ;
     RECT  46.451 5.136 46.721 6.168 ;
     RECT  45.904 13.632 46.739 14.232 ;
     RECT  46.613 22.176 46.757 22.2 ;
     RECT  46.717 25.104 46.781 25.128 ;
     RECT  45.904 23.376 46.789 23.502 ;
     RECT  46.649 10.896 46.829 11.256 ;
     RECT  46.469 15.984 46.829 17.736 ;
     RECT  46.781 25.104 46.865 25.752 ;
     RECT  46.837 0.144 46.892 0.168 ;
     RECT  46.685 1.152 46.892 1.752 ;
     RECT  46.829 10.896 46.969 11.016 ;
     RECT  46.469 18.816 47.005 19.464 ;
     RECT  46.613 20.496 47.005 21.144 ;
     RECT  46.892 0.144 47.009 1.752 ;
     RECT  47.009 0.144 47.173 0.6 ;
     RECT  46.829 16.848 47.267 17.736 ;
     RECT  46.721 5.136 47.333 5.16 ;
     RECT  46.397 9.648 47.477 9.672 ;
     RECT  47.005 18.816 47.477 21.144 ;
     RECT  46.969 10.8 47.545 11.016 ;
     RECT  47.173 0.096 47.621 0.6 ;
     RECT  46.739 13.632 47.621 13.656 ;
     RECT  47.477 18.816 47.629 19.944 ;
     RECT  46.037 7.92 47.653 7.944 ;
     RECT  47.545 10.656 47.657 11.016 ;
     RECT  47.477 21.072 47.693 21.144 ;
     RECT  47.653 7.248 47.699 7.944 ;
     RECT  47.629 18.816 47.761 19.8 ;
     RECT  47.557 3.408 47.801 3.432 ;
     RECT  47.009 1.728 47.833 1.752 ;
     RECT  47.653 14.832 47.893 14.856 ;
     RECT  47.267 16.848 47.893 17.64 ;
     RECT  47.699 7.248 47.909 7.272 ;
     RECT  47.893 14.736 47.939 14.856 ;
     RECT  47.893 16.512 47.98 17.64 ;
     RECT  47.939 14.736 48.017 14.76 ;
     RECT  47.657 10.848 48.085 11.016 ;
     RECT  47.617 12 48.085 12.024 ;
     RECT  46.865 25.104 48.085 25.128 ;
     RECT  47.833 1.728 48.133 1.848 ;
     RECT  48.133 1.728 48.157 1.896 ;
     RECT  47.98 17.088 48.161 17.64 ;
     RECT  48.085 10.848 48.197 12.024 ;
     RECT  48.157 1.728 48.265 2.184 ;
     RECT  48.161 17.424 48.277 17.64 ;
     RECT  47.761 18.768 48.277 19.8 ;
     RECT  48.085 25.104 48.323 25.752 ;
     RECT  47.437 5.088 48.373 5.112 ;
     RECT  48.265 1.728 48.449 2.28 ;
     RECT  48.277 17.424 48.449 19.8 ;
     RECT  47.621 0.144 48.613 0.6 ;
     RECT  48.449 1.728 48.613 1.8 ;
     RECT  47.693 21.12 48.661 21.144 ;
     RECT  48.469 2.88 48.665 2.904 ;
     RECT  46.789 23.376 48.755 23.928 ;
     RECT  48.613 0.144 48.773 1.8 ;
     RECT  48.449 17.424 48.773 18.792 ;
     RECT  48.661 21.072 48.773 21.144 ;
     RECT  48.773 0.144 48.805 1.752 ;
     RECT  48.373 4.992 48.809 5.112 ;
     RECT  48.755 23.376 48.851 23.88 ;
     RECT  47.797 13.056 48.901 13.08 ;
     RECT  48.773 21.12 48.913 21.144 ;
     RECT  48.197 11.376 48.947 12.024 ;
     RECT  48.805 0.096 48.953 1.752 ;
     RECT  48.913 21.12 48.953 21.336 ;
     RECT  48.953 1.728 48.989 1.752 ;
     RECT  48.901 13.056 48.989 13.32 ;
     RECT  48.851 23.376 48.995 23.592 ;
     RECT  48.157 7.2 49.021 7.224 ;
     RECT  48.323 25.104 49.091 25.128 ;
     RECT  48.809 5.088 49.273 5.112 ;
     RECT  49.273 5.088 49.313 5.448 ;
     RECT  48.989 13.056 49.349 13.08 ;
     RECT  48.953 0.096 49.385 0.264 ;
     RECT  48.949 19.92 49.417 19.944 ;
     RECT  48.773 17.424 49.601 18.12 ;
     RECT  47.869 8.4 49.637 8.424 ;
     RECT  48.947 11.376 49.637 11.544 ;
     RECT  49.417 19.344 49.637 19.944 ;
     RECT  49.021 6.864 49.813 7.224 ;
     RECT  49.057 14.784 49.82 14.808 ;
     RECT  48.953 21.312 49.853 21.336 ;
     RECT  49.813 10.224 49.897 10.392 ;
     RECT  49.82 14.784 49.907 15.384 ;
     RECT  49.813 6.768 50.033 7.224 ;
     RECT  49.601 17.424 50.101 18.024 ;
     RECT  49.957 0.048 50.141 0.072 ;
     RECT  50.101 16.944 50.245 18.024 ;
     RECT  49.637 19.392 50.389 19.944 ;
     RECT  49.637 11.52 50.425 11.544 ;
     RECT  49.313 5.424 51.008 5.448 ;
     RECT  50.033 6.816 51.008 7.224 ;
     RECT  49.897 10.368 51.008 10.392 ;
     RECT  50.425 11.52 51.008 12.024 ;
     RECT  49.907 14.784 51.008 14.808 ;
     RECT  50.245 16.512 51.008 18.024 ;
     RECT  50.389 19.392 51.008 20.088 ;
     RECT  49.381 22.8 51.008 22.824 ;
     RECT  51.008 2.148 51.112 23.772 ;
     RECT  51.112 2.418 51.304 23.502 ;
     RECT  51.304 13.104 51.532 13.656 ;
     RECT  51.304 22.8 51.581 22.824 ;
     RECT  51.304 7.392 51.625 7.416 ;
     RECT  51.532 13.104 51.653 13.128 ;
     RECT  51.304 19.392 51.725 19.416 ;
    LAYER M5 ;
     RECT  30.96 0.016 33.528 0.037 ;
     RECT  20.592 0.016 23.112 0.085 ;
     RECT  30.336 0.037 34.44 0.085 ;
     RECT  10.224 0.016 12.744 0.131 ;
     RECT  20.592 0.085 23.544 0.131 ;
     RECT  5.04 0.016 7.56 0.179 ;
     RECT  46.56 0.016 49.08 0.227 ;
     RECT  46.56 0.227 48.984 0.275 ;
     RECT  5.088 0.179 7.56 0.563 ;
     RECT  20.688 0.131 23.544 0.563 ;
     RECT  36.144 0.016 38.712 0.563 ;
     RECT  41.328 0.016 43.896 0.563 ;
     RECT  20.736 0.563 23.544 0.659 ;
     RECT  15.408 0.016 17.928 1.763 ;
     RECT  20.928 0.659 23.544 1.763 ;
     RECT  25.776 0.016 28.296 1.763 ;
     RECT  30.336 0.085 34.536 1.763 ;
     RECT  36.24 0.563 38.712 1.763 ;
     RECT  41.568 0.563 43.896 1.763 ;
     RECT  15.504 1.763 17.928 1.811 ;
     RECT  25.92 1.763 28.296 1.811 ;
     RECT  30.336 1.763 33.432 1.811 ;
     RECT  46.56 0.275 48.744 1.811 ;
     RECT  20.976 1.763 23.544 1.859 ;
     RECT  30.336 1.811 33.336 1.859 ;
     RECT  36.336 1.763 38.712 1.859 ;
     RECT  46.56 1.811 48.504 1.859 ;
     RECT  15.552 1.811 17.928 1.907 ;
     RECT  21.072 1.859 23.544 1.955 ;
     RECT  5.088 0.563 7.32 2.137 ;
     RECT  10.224 0.131 12.696 2.137 ;
     RECT  15.648 1.907 17.928 2.137 ;
     RECT  22.08 1.955 23.544 2.137 ;
     RECT  30.336 1.859 32.856 2.137 ;
     RECT  34.416 1.763 34.536 2.137 ;
     RECT  2.4 2.137 2.52 2.151 ;
     RECT  5.088 2.137 7.92 2.151 ;
     RECT  10.224 2.137 13.32 2.151 ;
     RECT  15.648 2.137 18.72 2.151 ;
     RECT  22.08 2.137 24.12 2.151 ;
     RECT  34.416 2.137 34.92 2.151 ;
     RECT  40.2 2.137 40.32 2.151 ;
     RECT  51 2.137 51.12 2.151 ;
     RECT  10.224 2.151 13.512 2.195 ;
     RECT  26.112 1.811 27.816 2.195 ;
     RECT  11.328 2.195 13.512 2.243 ;
     RECT  5.088 2.151 8.112 2.291 ;
     RECT  11.664 2.243 13.512 2.291 ;
     RECT  15.648 2.151 18.912 2.291 ;
     RECT  21.072 1.955 21.096 2.291 ;
     RECT  22.08 2.151 24.312 2.291 ;
     RECT  26.112 2.195 26.76 2.291 ;
     RECT  27.792 2.195 27.816 2.291 ;
     RECT  36.384 1.859 38.232 2.291 ;
     RECT  41.664 1.763 43.896 2.291 ;
     RECT  23.52 2.291 24.312 2.773 ;
     RECT  5.088 2.291 5.64 2.821 ;
     RECT  10.224 2.195 10.248 2.821 ;
     RECT  26.112 2.291 26.136 2.867 ;
     RECT  29.4 2.137 32.856 2.915 ;
     RECT  47.568 1.859 48.504 2.915 ;
     RECT  34.416 2.151 35.112 3.253 ;
     RECT  36.384 2.291 37.224 3.253 ;
     RECT  29.4 2.915 32.232 3.299 ;
     RECT  22.08 2.291 22.152 3.347 ;
     RECT  34.416 3.253 37.224 3.397 ;
     RECT  38.208 2.291 38.232 3.397 ;
     RECT  40.2 2.151 40.512 3.397 ;
     RECT  11.664 2.291 11.688 3.443 ;
     RECT  34.416 3.397 38.232 3.443 ;
     RECT  47.568 2.915 47.592 3.443 ;
     RECT  4.56 2.821 5.64 3.587 ;
     RECT  34.416 3.443 37.8 3.637 ;
     RECT  5.328 3.587 5.64 3.733 ;
     RECT  6.72 2.291 8.112 3.733 ;
     RECT  23.52 2.773 24.408 3.877 ;
     RECT  5.328 3.733 8.112 3.971 ;
     RECT  41.664 2.291 42.264 3.971 ;
     RECT  9.648 2.821 10.248 4.019 ;
     RECT  15.648 2.291 16.872 4.019 ;
     RECT  34.128 3.637 37.8 4.019 ;
     RECT  34.128 4.019 36.36 4.115 ;
     RECT  5.616 3.971 8.112 4.117 ;
     RECT  17.904 2.291 18.912 4.117 ;
     RECT  5.616 4.117 8.52 4.453 ;
     RECT  9.648 4.019 9.768 4.453 ;
     RECT  15.648 4.019 16.056 4.501 ;
     RECT  29.4 3.299 31.752 4.501 ;
     RECT  27.888 3.301 27.912 4.547 ;
     RECT  43.776 3.925 43.8 4.595 ;
     RECT  5.616 4.453 9.768 4.691 ;
     RECT  40.08 3.397 40.512 4.691 ;
     RECT  34.416 4.115 36.36 4.931 ;
     RECT  12.672 2.291 13.512 5.029 ;
     RECT  15.12 4.501 16.056 5.077 ;
     RECT  37.776 4.019 37.8 5.077 ;
     RECT  45.6 2.137 45.912 5.125 ;
     RECT  9.408 4.691 9.768 5.171 ;
     RECT  40.2 4.691 40.512 5.221 ;
     RECT  17.904 4.117 19.464 5.605 ;
     RECT  20.928 4.645 20.952 5.605 ;
     RECT  34.416 4.931 35.112 5.653 ;
     RECT  26.736 5.077 26.76 5.747 ;
     RECT  29.4 4.501 32.568 5.747 ;
     RECT  36.336 4.931 36.36 5.747 ;
     RECT  29.4 5.747 31.08 5.843 ;
     RECT  23.52 3.877 24.696 6.133 ;
     RECT  45.6 5.125 46.056 6.133 ;
     RECT  32.544 5.747 32.568 6.229 ;
     RECT  33.792 5.653 35.112 6.229 ;
     RECT  37.776 5.077 37.848 6.229 ;
     RECT  40.2 5.221 40.968 6.229 ;
     RECT  15.12 5.077 16.296 6.275 ;
     RECT  42 3.971 42.264 6.275 ;
     RECT  5.616 4.691 8.28 6.323 ;
     RECT  38.928 6.229 40.968 6.371 ;
     RECT  17.904 5.605 19.752 6.805 ;
     RECT  20.736 5.605 20.952 6.805 ;
     RECT  22.128 3.347 22.152 6.805 ;
     RECT  45.6 6.133 46.152 6.805 ;
     RECT  7.152 6.323 8.28 6.899 ;
     RECT  29.4 5.843 30.984 6.899 ;
     RECT  12.672 5.029 13.608 6.947 ;
     RECT  13.104 6.947 13.608 7.141 ;
     RECT  36.768 6.229 36.792 7.141 ;
     RECT  37.776 6.229 37.944 7.141 ;
     RECT  3.984 6.805 4.008 7.331 ;
     RECT  23.424 6.133 24.696 7.381 ;
     RECT  26.064 6.805 26.088 7.381 ;
     RECT  51 2.151 51.312 7.381 ;
     RECT  5.616 6.323 5.928 7.475 ;
     RECT  17.904 6.805 22.152 7.475 ;
     RECT  22.128 7.475 22.152 7.477 ;
     RECT  36.768 7.141 37.944 7.619 ;
     RECT  30.96 6.899 30.984 7.765 ;
     RECT  45.6 6.805 46.44 7.765 ;
     RECT  5.904 7.475 5.928 7.909 ;
     RECT  7.152 6.899 8.232 7.909 ;
     RECT  23.424 7.381 26.088 7.957 ;
     RECT  15.168 6.275 16.296 8.003 ;
     RECT  23.376 7.957 26.088 8.003 ;
     RECT  32.544 6.229 35.112 8.147 ;
     RECT  42 6.275 42.024 8.341 ;
     RECT  13.104 7.141 13.656 8.485 ;
     RECT  27.888 7.909 27.912 9.011 ;
     RECT  2.4 2.151 2.712 9.061 ;
     RECT  3.84 7.381 3.864 9.061 ;
     RECT  29.4 6.899 29.712 9.061 ;
     RECT  38.928 6.371 40.512 9.061 ;
     RECT  42 8.341 42.456 9.061 ;
     RECT  13.104 8.485 13.896 9.107 ;
     RECT  23.376 8.003 25.32 9.107 ;
     RECT  30.96 7.765 31.272 9.107 ;
     RECT  18.6 7.475 20.952 9.491 ;
     RECT  18.6 9.491 20.712 9.493 ;
     RECT  18.432 9.493 20.712 9.589 ;
     RECT  23.424 9.107 25.32 9.637 ;
     RECT  17.856 9.589 20.712 10.069 ;
     RECT  15.168 8.003 15.192 10.213 ;
     RECT  37.776 7.619 37.944 10.213 ;
     RECT  38.928 9.061 42.456 10.213 ;
     RECT  37.776 10.213 42.456 10.307 ;
     RECT  13.104 9.107 13.656 10.597 ;
     RECT  30.96 9.107 31.176 10.741 ;
     RECT  5.904 7.909 8.232 10.789 ;
     RECT  9.408 5.171 9.432 10.789 ;
     RECT  36.768 7.619 36.792 10.789 ;
     RECT  37.776 10.307 40.512 10.789 ;
     RECT  12.336 10.597 13.656 10.883 ;
     RECT  47.664 7.237 47.688 10.883 ;
     RECT  17.616 10.069 20.712 10.931 ;
     RECT  28.896 9.061 29.712 11.365 ;
     RECT  32.592 8.147 35.112 11.365 ;
     RECT  5.904 10.789 9.432 11.459 ;
     RECT  23.424 9.637 25.464 11.459 ;
     RECT  49.824 10.213 49.848 11.555 ;
     RECT  30.96 10.741 31.512 11.941 ;
     RECT  32.592 11.365 35.208 11.941 ;
     RECT  2.4 9.061 3.864 12.469 ;
     RECT  12.96 10.883 13.656 12.515 ;
     RECT  36.768 10.789 40.512 12.563 ;
     RECT  0.192 6.469 0.216 12.611 ;
     RECT  5.904 11.459 8.232 12.803 ;
     RECT  41.664 10.307 42.456 13.139 ;
     RECT  51 7.381 51.576 13.139 ;
     RECT  48.912 11.989 48.936 13.331 ;
     RECT  30.96 11.941 35.208 13.333 ;
     RECT  13.104 12.515 13.656 13.477 ;
     RECT  14.832 10.213 15.192 13.477 ;
     RECT  13.104 13.477 15.192 13.621 ;
     RECT  16.176 8.003 16.296 13.621 ;
     RECT  30.96 13.333 35.496 13.667 ;
     RECT  32.592 13.667 35.496 13.859 ;
     RECT  22.128 7.477 22.392 14.149 ;
     RECT  23.712 11.459 25.464 14.149 ;
     RECT  44.928 7.765 46.44 14.197 ;
     RECT  43.824 13.045 43.848 14.245 ;
     RECT  2.4 12.469 3.96 14.291 ;
     RECT  13.104 13.621 16.296 14.387 ;
     RECT  17.856 10.931 20.712 14.533 ;
     RECT  28.56 11.365 29.712 14.677 ;
     RECT  30.96 13.667 31.512 14.677 ;
     RECT  3.936 14.291 3.96 14.773 ;
     RECT  28.56 14.677 31.512 14.773 ;
     RECT  32.592 13.859 35.4 14.773 ;
     RECT  41.712 13.139 42.456 14.773 ;
     RECT  12 14.677 12.024 14.867 ;
     RECT  43.824 14.245 43.944 14.867 ;
     RECT  47.904 14.725 47.928 14.867 ;
     RECT  27.312 14.533 27.336 14.917 ;
     RECT  27.312 14.917 27.576 15.443 ;
     RECT  28.56 14.773 35.4 15.443 ;
     RECT  43.92 14.867 43.944 15.443 ;
     RECT  5.904 12.803 8.112 15.685 ;
     RECT  9.408 11.459 9.432 15.685 ;
     RECT  10.512 11.365 10.536 15.685 ;
     RECT  9.408 15.685 10.536 15.829 ;
     RECT  17.856 14.533 20.808 16.019 ;
     RECT  27.312 15.443 27.336 16.019 ;
     RECT  5.616 15.685 8.112 16.307 ;
     RECT  28.704 15.443 35.4 16.405 ;
     RECT  41.712 14.773 42.648 16.499 ;
     RECT  22.128 14.149 25.464 16.501 ;
     RECT  49.872 15.349 49.896 16.933 ;
     RECT  51 13.139 51.48 16.933 ;
     RECT  28.32 16.405 35.4 16.981 ;
     RECT  44.928 14.197 46.728 17.029 ;
     RECT  47.904 16.501 47.928 17.029 ;
     RECT  9.408 15.829 10.68 17.075 ;
     RECT  13.104 14.387 15.192 17.077 ;
     RECT  17.856 16.019 20.712 17.077 ;
     RECT  3.936 14.773 4.056 17.171 ;
     RECT  44.928 17.029 47.928 17.171 ;
     RECT  13.008 17.077 15.192 17.605 ;
     RECT  17.856 17.077 20.856 17.605 ;
     RECT  49.872 16.933 51.48 17.699 ;
     RECT  44.928 17.171 47.256 17.747 ;
     RECT  5.616 16.307 6.024 17.749 ;
     RECT  7.104 16.307 8.112 17.749 ;
     RECT  5.616 17.749 8.112 17.987 ;
     RECT  2.4 14.291 2.712 18.181 ;
     RECT  17.856 17.605 21.048 18.565 ;
     RECT  22.032 16.501 25.464 18.565 ;
     RECT  43.92 16.981 43.944 18.757 ;
     RECT  44.928 17.747 47.208 18.757 ;
     RECT  28.32 16.981 35.448 18.851 ;
     RECT  12.96 17.605 15.192 19.141 ;
     RECT  10.656 17.075 10.68 19.237 ;
     RECT  43.92 18.757 47.208 19.237 ;
     RECT  17.856 18.565 25.464 19.333 ;
     RECT  4.032 17.171 4.056 19.427 ;
     RECT  9.408 17.075 9.432 19.427 ;
     RECT  37.008 12.563 40.512 19.427 ;
     RECT  50.112 17.699 51.48 19.427 ;
     RECT  2.4 18.181 2.808 19.475 ;
     RECT  12.624 19.141 15.192 19.765 ;
     RECT  12.528 19.765 15.192 19.861 ;
     RECT  16.176 14.387 16.296 19.861 ;
     RECT  42 16.499 42.648 19.909 ;
     RECT  43.92 19.237 47.304 19.909 ;
     RECT  48.288 18.181 48.312 19.909 ;
     RECT  5.616 17.987 6.024 20.003 ;
     RECT  10.656 19.237 11.544 20.005 ;
     RECT  7.104 17.987 8.112 20.053 ;
     RECT  50.4 19.427 51.312 20.099 ;
     RECT  37.68 19.427 40.512 20.485 ;
     RECT  17.568 19.333 25.464 20.533 ;
     RECT  28.416 18.851 35.448 20.533 ;
     RECT  12.528 19.861 16.296 20.579 ;
     RECT  2.4 19.475 2.712 20.869 ;
     RECT  2.4 20.869 3.672 20.965 ;
     RECT  10.368 20.005 11.544 20.965 ;
     RECT  12.528 20.579 16.2 20.965 ;
     RECT  7.104 20.053 8.232 21.061 ;
     RECT  17.28 20.533 25.464 21.155 ;
     RECT  27.648 20.533 35.448 21.155 ;
     RECT  5.904 20.003 6.024 21.203 ;
     RECT  30.96 21.155 30.984 21.203 ;
     RECT  32.592 21.155 35.448 21.299 ;
     RECT  27.648 21.155 29.712 21.301 ;
     RECT  10.368 20.965 16.2 21.637 ;
     RECT  37.536 20.485 40.512 21.637 ;
     RECT  6 21.203 6.024 21.683 ;
     RECT  7.104 21.061 8.904 21.683 ;
     RECT  17.28 21.155 24.696 21.683 ;
     RECT  2.304 20.965 3.672 21.731 ;
     RECT  10.272 21.637 16.2 21.731 ;
     RECT  21.024 21.683 24.696 21.779 ;
     RECT  7.488 21.683 8.904 21.923 ;
     RECT  32.592 21.299 35.208 21.923 ;
     RECT  2.304 21.731 2.712 21.971 ;
     RECT  21.024 21.779 24.504 22.019 ;
     RECT  42 19.909 48.312 22.069 ;
     RECT  10.272 21.731 16.152 22.259 ;
     RECT  41.568 22.069 48.312 22.259 ;
     RECT  32.736 21.923 35.208 22.307 ;
     RECT  27.312 21.301 29.712 22.741 ;
     RECT  44.16 22.259 48.312 22.787 ;
     RECT  36.672 21.637 40.512 22.789 ;
     RECT  41.568 22.259 42.984 22.789 ;
     RECT  10.272 22.259 13.656 22.835 ;
     RECT  10.368 22.835 13.656 22.883 ;
     RECT  7.488 21.923 8.232 22.931 ;
     RECT  26.352 22.741 29.712 23.027 ;
     RECT  31.536 22.789 31.56 23.077 ;
     RECT  32.736 22.307 35.112 23.077 ;
     RECT  36.672 22.789 42.984 23.123 ;
     RECT  31.536 23.077 35.112 23.267 ;
     RECT  44.16 22.787 44.568 23.315 ;
     RECT  6.288 21.685 6.312 23.365 ;
     RECT  7.488 22.931 8.112 23.365 ;
     RECT  15.792 22.259 16.152 23.365 ;
     RECT  17.28 21.683 19.416 23.365 ;
     RECT  21.024 22.019 24.312 23.365 ;
     RECT  26.352 23.027 28.296 23.365 ;
     RECT  31.536 23.267 33.528 23.365 ;
     RECT  36.672 23.123 38.712 23.365 ;
     RECT  40.2 23.123 42.984 23.365 ;
     RECT  44.16 23.315 44.184 23.365 ;
     RECT  45.6 22.787 48.312 23.365 ;
     RECT  40.2 23.365 44.184 23.411 ;
     RECT  45.6 23.365 48.936 23.557 ;
     RECT  5.328 23.365 8.112 23.701 ;
     RECT  20.736 23.365 24.312 23.701 ;
     RECT  2.4 21.971 2.712 23.769 ;
     RECT  5.088 23.701 8.112 23.769 ;
     RECT  10.368 22.883 13.512 23.769 ;
     RECT  20.592 23.701 24.312 23.769 ;
     RECT  29.4 23.027 29.712 23.769 ;
     RECT  34.8 23.267 35.112 23.769 ;
     RECT  40.2 23.411 43.896 23.769 ;
     RECT  51 20.099 51.312 23.769 ;
     RECT  2.4 23.769 2.52 23.783 ;
     RECT  5.088 23.769 7.92 23.783 ;
     RECT  10.368 23.769 13.32 23.783 ;
     RECT  15.552 23.365 19.416 23.783 ;
     RECT  20.592 23.769 24.12 23.783 ;
     RECT  29.4 23.769 29.52 23.783 ;
     RECT  34.8 23.769 34.92 23.783 ;
     RECT  40.2 23.769 40.32 23.783 ;
     RECT  45.6 23.557 48.984 23.783 ;
     RECT  51 23.769 51.12 23.783 ;
     RECT  31.296 23.365 33.528 23.797 ;
     RECT  5.088 23.783 7.56 23.893 ;
     RECT  10.368 23.783 12.984 23.893 ;
     RECT  15.552 23.783 17.928 23.893 ;
     RECT  31.2 23.797 33.528 23.893 ;
     RECT  31.152 23.893 33.528 24.037 ;
     RECT  19.344 23.783 19.416 24.515 ;
     RECT  15.504 23.893 17.928 25.093 ;
     RECT  31.056 24.037 33.528 25.093 ;
     RECT  46.56 23.783 48.984 25.093 ;
     RECT  19.344 24.515 19.368 25.139 ;
     RECT  20.592 23.783 23.064 25.717 ;
     RECT  10.224 23.893 12.984 25.859 ;
     RECT  5.04 23.893 7.56 25.872 ;
     RECT  10.224 25.859 12.744 25.872 ;
     RECT  15.408 25.093 17.928 25.872 ;
     RECT  20.592 25.717 23.112 25.872 ;
     RECT  25.776 23.365 28.296 25.872 ;
     RECT  30.96 25.093 33.528 25.872 ;
     RECT  36.144 23.365 38.712 25.872 ;
     RECT  41.328 23.769 43.896 25.872 ;
     RECT  46.56 25.093 49.08 25.872 ;
     RECT  33.432 1.763 34.416 1.811 ;
     RECT  36.24 1.763 36.336 1.859 ;
     RECT  41.568 1.763 41.664 2.137 ;
     RECT  27.816 1.811 28.296 2.137 ;
     RECT  33.336 1.811 34.416 1.859 ;
     RECT  36.24 1.859 36.384 2.137 ;
     RECT  21.096 1.955 22.08 2.291 ;
     RECT  27.816 2.137 29.4 2.291 ;
     RECT  34.92 2.137 36.384 2.151 ;
     RECT  40.32 2.137 41.664 2.151 ;
     RECT  35.112 2.151 36.384 3.253 ;
     RECT  40.512 2.151 41.664 3.971 ;
     RECT  10.248 2.195 11.328 2.243 ;
     RECT  26.76 2.195 27.792 2.291 ;
     RECT  10.248 2.243 11.664 3.443 ;
     RECT  5.64 2.291 6.72 3.733 ;
     RECT  11.688 2.291 12.672 3.443 ;
     RECT  16.872 2.291 17.904 4.019 ;
     RECT  22.152 2.291 23.52 6.133 ;
     RECT  27.888 2.291 29.4 3.301 ;
     RECT  37.224 2.291 38.208 3.397 ;
     RECT  31.752 3.299 32.232 4.501 ;
     RECT  27.912 3.301 29.4 4.547 ;
     RECT  22.08 3.347 22.128 4.645 ;
     RECT  42.264 3.925 43.776 4.595 ;
     RECT  40.512 3.971 42 5.221 ;
     RECT  16.056 4.019 16.296 5.077 ;
     RECT  36.36 4.019 37.776 5.747 ;
     RECT  8.52 4.117 9.648 4.453 ;
     RECT  19.464 4.645 20.928 5.605 ;
     RECT  20.952 4.645 22.128 6.805 ;
     RECT  8.28 4.691 9.408 6.899 ;
     RECT  35.112 4.931 36.336 5.747 ;
     RECT  13.608 5.029 15.12 6.275 ;
     RECT  40.968 5.221 42 6.371 ;
     RECT  19.752 5.605 20.736 6.805 ;
     RECT  32.568 5.653 33.792 6.229 ;
     RECT  31.08 5.747 32.544 5.843 ;
     RECT  36.768 5.747 37.776 6.229 ;
     RECT  22.152 6.133 23.424 7.477 ;
     RECT  36.792 6.229 37.776 7.141 ;
     RECT  37.944 6.229 38.928 10.213 ;
     RECT  13.608 6.275 15.168 7.141 ;
     RECT  5.928 6.323 7.152 7.909 ;
     RECT  40.512 6.371 42 9.061 ;
     RECT  2.712 6.805 3.984 7.331 ;
     RECT  24.696 6.805 26.064 7.381 ;
     RECT  8.232 6.899 9.408 10.789 ;
     RECT  29.712 6.899 30.96 14.677 ;
     RECT  13.656 7.141 15.168 8.485 ;
     RECT  46.44 7.237 47.664 10.883 ;
     RECT  2.712 7.331 3.864 7.381 ;
     RECT  2.712 7.381 3.84 9.061 ;
     RECT  20.952 7.475 22.128 9.491 ;
     RECT  22.392 7.477 23.424 7.957 ;
     RECT  36.792 7.619 37.776 10.789 ;
     RECT  31.272 7.765 32.544 8.147 ;
     RECT  27.912 7.909 29.4 9.011 ;
     RECT  22.392 7.957 23.376 9.107 ;
     RECT  15.192 8.003 16.176 13.621 ;
     RECT  31.272 8.147 32.592 9.107 ;
     RECT  13.896 8.485 15.168 9.107 ;
     RECT  28.896 9.011 29.4 9.061 ;
     RECT  13.656 9.107 15.168 10.213 ;
     RECT  22.392 9.107 23.424 11.459 ;
     RECT  31.176 9.107 32.592 10.741 ;
     RECT  20.712 9.491 22.128 14.533 ;
     RECT  16.296 10.069 17.616 10.931 ;
     RECT  13.656 10.213 14.832 13.477 ;
     RECT  49.848 10.213 51 11.555 ;
     RECT  40.512 10.307 41.664 13.139 ;
     RECT  31.512 10.741 32.592 11.941 ;
     RECT  9.432 11.365 10.512 15.685 ;
     RECT  8.232 11.459 9.408 12.803 ;
     RECT  22.392 11.459 23.712 14.149 ;
     RECT  36.768 12.563 37.008 13.333 ;
     RECT  8.112 12.803 9.408 19.427 ;
     RECT  42.456 13.045 43.824 14.773 ;
     RECT  43.848 13.045 44.928 14.245 ;
     RECT  40.512 13.139 41.712 16.499 ;
     RECT  35.496 13.333 37.008 13.859 ;
     RECT  31.512 13.667 32.592 14.773 ;
     RECT  43.944 14.245 44.928 15.443 ;
     RECT  2.712 14.291 3.936 17.171 ;
     RECT  15.192 14.387 16.176 19.861 ;
     RECT  20.808 14.533 22.128 16.019 ;
     RECT  27.336 14.533 28.56 14.917 ;
     RECT  10.536 14.677 12 14.867 ;
     RECT  12.024 14.677 13.104 14.867 ;
     RECT  46.728 14.725 47.904 14.867 ;
     RECT  42.648 14.773 43.824 14.867 ;
     RECT  10.536 14.867 10.68 15.829 ;
     RECT  42.648 14.867 43.92 15.443 ;
     RECT  27.576 14.917 28.56 15.443 ;
     RECT  49.896 15.349 51 16.933 ;
     RECT  27.336 15.443 28.704 16.019 ;
     RECT  20.712 16.019 22.128 16.501 ;
     RECT  28.32 16.019 28.704 16.405 ;
     RECT  6.024 16.307 7.104 17.749 ;
     RECT  40.512 16.499 42 22.069 ;
     RECT  20.712 16.501 22.032 17.077 ;
     RECT  46.728 16.501 47.904 17.029 ;
     RECT  42.648 16.981 43.92 19.909 ;
     RECT  43.944 16.981 44.928 18.757 ;
     RECT  9.432 17.075 10.656 19.427 ;
     RECT  20.856 17.077 22.032 17.605 ;
     RECT  2.712 17.171 4.032 18.181 ;
     RECT  47.256 17.171 47.928 17.747 ;
     RECT  21.048 17.605 22.032 18.565 ;
     RECT  47.208 17.747 47.928 18.181 ;
     RECT  6.024 17.987 7.104 21.683 ;
     RECT  2.808 18.181 4.032 19.427 ;
     RECT  47.208 18.181 48.288 19.237 ;
     RECT  11.544 19.237 12.624 19.765 ;
     RECT  47.304 19.237 48.288 19.909 ;
     RECT  16.296 19.333 17.568 20.533 ;
     RECT  2.808 19.427 3.672 19.475 ;
     RECT  8.112 19.427 8.232 20.053 ;
     RECT  10.368 19.427 10.656 20.005 ;
     RECT  37.536 19.427 37.68 20.485 ;
     RECT  2.712 19.475 3.672 20.869 ;
     RECT  11.544 19.765 12.528 20.965 ;
     RECT  16.296 20.533 17.28 20.579 ;
     RECT  16.2 20.579 17.28 21.731 ;
     RECT  8.904 21.061 10.368 21.637 ;
     RECT  29.712 21.155 30.96 21.203 ;
     RECT  35.208 21.299 35.448 21.637 ;
     RECT  8.904 21.637 10.272 21.923 ;
     RECT  35.208 21.637 36.672 22.307 ;
     RECT  6.288 21.683 7.488 21.685 ;
     RECT  6.312 21.685 7.488 23.365 ;
     RECT  16.152 21.731 17.28 23.365 ;
     RECT  32.592 21.923 32.736 22.789 ;
     RECT  24.312 22.019 24.504 23.365 ;
     RECT  40.512 22.069 41.568 22.789 ;
     RECT  15.552 22.259 15.792 23.365 ;
     RECT  42.984 22.259 44.16 23.365 ;
     RECT  35.112 22.307 36.672 23.365 ;
     RECT  44.568 22.787 45.6 23.315 ;
     RECT  31.56 22.789 32.736 23.077 ;
     RECT  10.272 22.835 10.368 23.893 ;
     RECT  28.296 23.027 29.4 23.783 ;
     RECT  38.712 23.123 40.2 23.783 ;
     RECT  33.528 23.267 34.8 23.783 ;
     RECT  44.184 23.315 45.6 23.411 ;
     RECT  19.416 23.365 20.736 23.701 ;
     RECT  24.312 23.365 25.776 23.769 ;
     RECT  35.112 23.365 36.144 23.769 ;
     RECT  19.416 23.701 20.592 24.515 ;
     RECT  34.92 23.769 36.144 23.783 ;
     RECT  40.32 23.769 41.328 23.783 ;
     RECT  17.928 23.783 19.344 25.139 ;
     RECT  19.368 24.515 20.592 25.139 ;
  END
END dsfd_vm_fxr
END LIBRARY
